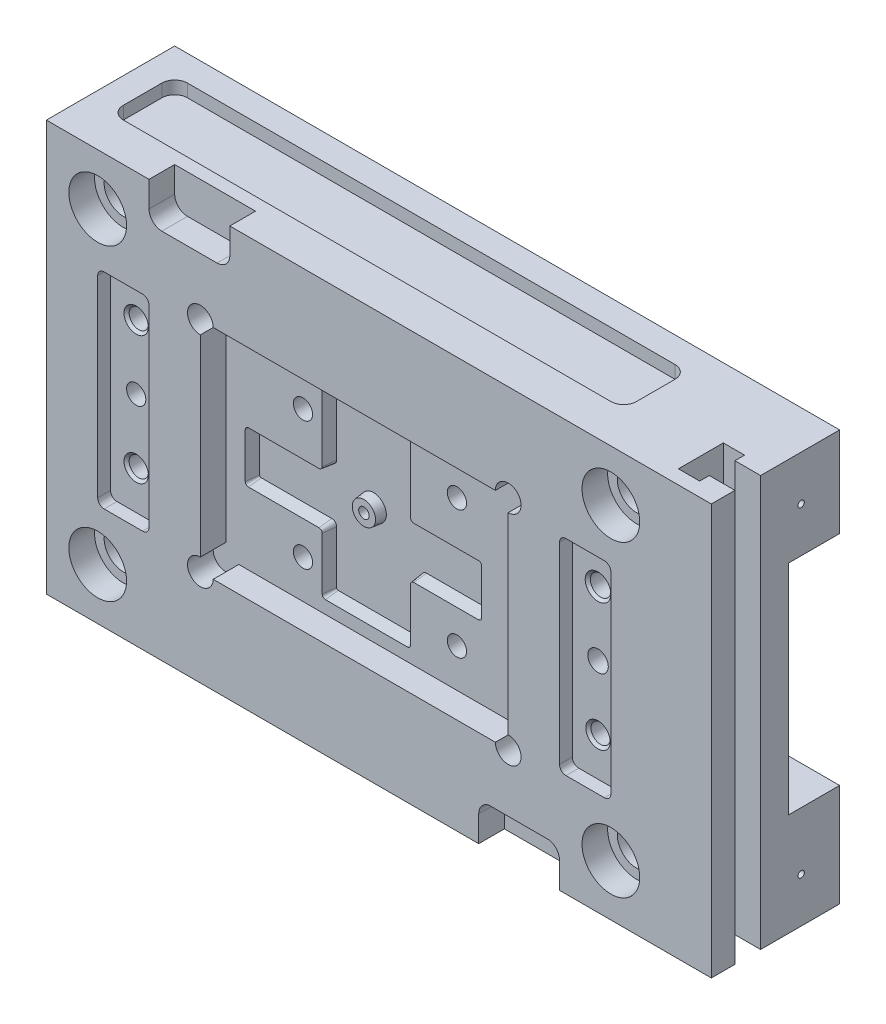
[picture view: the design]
ISO-10303-21;
HEADER;
FILE_DESCRIPTION(('STEP AP214'),'2;1');
FILE_NAME('part.step','',(''),(''),'','','');
FILE_SCHEMA(('AUTOMOTIVE_DESIGN { 1 0 10303 214 1 1 1 1 }'));
ENDSEC;
DATA;
#1=APPLICATION_CONTEXT('core data for automotive mechanical design processes');
#2=APPLICATION_PROTOCOL_DEFINITION('international standard','automotive_design',2000,#1);
#3=PRODUCT_CONTEXT('',#1,'mechanical');
#4=PRODUCT('Part','Part','',(#3));
#5=PRODUCT_RELATED_PRODUCT_CATEGORY('part','',(#4));
#6=PRODUCT_DEFINITION_FORMATION('','',#4);
#7=PRODUCT_DEFINITION_CONTEXT('part definition',#1,'design');
#8=PRODUCT_DEFINITION('design','',#6,#7);
#9=PRODUCT_DEFINITION_SHAPE('','',#8);
#10=(LENGTH_UNIT() NAMED_UNIT(*) SI_UNIT(.MILLI.,.METRE.));
#11=(NAMED_UNIT(*) PLANE_ANGLE_UNIT() SI_UNIT($,.RADIAN.));
#12=(NAMED_UNIT(*) SI_UNIT($,.STERADIAN.) SOLID_ANGLE_UNIT());
#13=UNCERTAINTY_MEASURE_WITH_UNIT(LENGTH_MEASURE(1.E-05),#10,'distance_accuracy_value','');
#14=(GEOMETRIC_REPRESENTATION_CONTEXT(3) GLOBAL_UNCERTAINTY_ASSIGNED_CONTEXT((#13)) GLOBAL_UNIT_ASSIGNED_CONTEXT((#10,
#11,#12)) REPRESENTATION_CONTEXT('',''));
#15=CARTESIAN_POINT('',(0.,0.,0.));
#16=DIRECTION('',(0.,0.,1.));
#17=DIRECTION('',(1.,0.,0.));
#18=AXIS2_PLACEMENT_3D('',#15,#16,#17);
#19=CARTESIAN_POINT('',(658.256146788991,406.4,0.));
#20=DIRECTION('',(1.,0.,0.));
#21=DIRECTION('',(0.,0.,-1.));
#22=AXIS2_PLACEMENT_3D('',#19,#20,#21);
#23=PLANE('',#22);
#24=CARTESIAN_POINT('',(658.256146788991,361.95,-88.9));
#25=DIRECTION('',(1.,0.,0.));
#26=DIRECTION('',(0.,0.,-1.));
#27=AXIS2_PLACEMENT_3D('',#24,#25,#26);
#28=CIRCLE('',#27,3.17500000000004);
#29=CARTESIAN_POINT('',(658.256146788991,361.95,-92.075));
#30=VERTEX_POINT('',#29);
#31=EDGE_CURVE('E745',#30,#30,#28,.T.);
#32=ORIENTED_EDGE('',*,*,#31,.F.);
#33=EDGE_LOOP('',(#32));
#34=FACE_BOUND('',#33,.T.);
#35=CARTESIAN_POINT('',(658.256146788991,44.45,-88.9));
#36=DIRECTION('',(1.,0.,0.));
#37=DIRECTION('',(0.,0.,-1.));
#38=AXIS2_PLACEMENT_3D('',#35,#36,#37);
#39=CIRCLE('',#38,3.17500000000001);
#40=CARTESIAN_POINT('',(658.256146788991,44.45,-92.075));
#41=VERTEX_POINT('',#40);
#42=EDGE_CURVE('E709',#41,#41,#39,.T.);
#43=ORIENTED_EDGE('',*,*,#42,.F.);
#44=EDGE_LOOP('',(#43));
#45=FACE_BOUND('',#44,.T.);
#46=DIRECTION('',(0.,1.,0.));
#47=VECTOR('',#46,1.);
#48=CARTESIAN_POINT('',(658.256146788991,406.4,-48.7717322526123));
#49=LINE('',#48,#47);
#50=CARTESIAN_POINT('',(658.256146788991,0.,-48.7717322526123));
#51=VERTEX_POINT('',#50);
#52=CARTESIAN_POINT('',(658.256146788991,406.4,-48.7717322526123));
#53=VERTEX_POINT('',#52);
#54=EDGE_CURVE('E760',#51,#53,#49,.T.);
#55=ORIENTED_EDGE('',*,*,#54,.F.);
#56=DIRECTION('',(0.,0.,-1.));
#57=VECTOR('',#56,1.);
#58=CARTESIAN_POINT('',(658.256146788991,0.,0.));
#59=LINE('',#58,#57);
#60=CARTESIAN_POINT('',(658.256146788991,0.,-127.));
#61=VERTEX_POINT('',#60);
#62=EDGE_CURVE('E763',#51,#61,#59,.T.);
#63=ORIENTED_EDGE('',*,*,#62,.T.);
#64=DIRECTION('',(0.,-1.,0.));
#65=VECTOR('',#64,1.);
#66=CARTESIAN_POINT('',(658.256146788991,406.4,-127.));
#67=LINE('',#66,#65);
#68=CARTESIAN_POINT('',(658.256146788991,101.6,-127.));
#69=VERTEX_POINT('',#68);
#70=EDGE_CURVE('E808',#69,#61,#67,.T.);
#71=ORIENTED_EDGE('',*,*,#70,.F.);
#72=DIRECTION('',(0.,0.,-1.));
#73=VECTOR('',#72,1.);
#74=CARTESIAN_POINT('',(658.256146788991,101.6,-76.2));
#75=LINE('',#74,#73);
#76=CARTESIAN_POINT('',(658.256146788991,101.6,-76.2));
#77=VERTEX_POINT('',#76);
#78=EDGE_CURVE('E1330',#77,#69,#75,.T.);
#79=ORIENTED_EDGE('',*,*,#78,.F.);
#80=DIRECTION('',(0.,-1.,0.));
#81=VECTOR('',#80,1.);
#82=CARTESIAN_POINT('',(658.256146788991,317.5,-76.2));
#83=LINE('',#82,#81);
#84=CARTESIAN_POINT('',(658.256146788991,317.5,-76.2));
#85=VERTEX_POINT('',#84);
#86=EDGE_CURVE('E1318',#85,#77,#83,.T.);
#87=ORIENTED_EDGE('',*,*,#86,.F.);
#88=DIRECTION('',(0.,0.,1.));
#89=VECTOR('',#88,1.);
#90=CARTESIAN_POINT('',(658.256146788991,317.5,-127.));
#91=LINE('',#90,#89);
#92=CARTESIAN_POINT('',(658.256146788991,317.5,-127.));
#93=VERTEX_POINT('',#92);
#94=EDGE_CURVE('E1328',#93,#85,#91,.T.);
#95=ORIENTED_EDGE('',*,*,#94,.F.);
#96=CARTESIAN_POINT('',(658.256146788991,406.4,-127.));
#97=VERTEX_POINT('',#96);
#98=EDGE_CURVE('E804',#97,#93,#67,.T.);
#99=ORIENTED_EDGE('',*,*,#98,.F.);
#100=DIRECTION('',(0.,0.,-1.));
#101=VECTOR('',#100,1.);
#102=CARTESIAN_POINT('',(658.256146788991,406.4,0.));
#103=LINE('',#102,#101);
#104=EDGE_CURVE('E766',#53,#97,#103,.T.);
#105=ORIENTED_EDGE('',*,*,#104,.F.);
#106=EDGE_LOOP('',(#55,#63,#71,#79,#87,#95,#99,#105));
#107=FACE_BOUND('',#106,.T.);
#108=ADVANCED_FACE('F39',(#34,#45,#107),#23,.T.);
#109=CARTESIAN_POINT('',(250.825,288.925,-38.1000000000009));
#110=DIRECTION('',(0.,0.,1.));
#111=DIRECTION('',(1.,0.,0.));
#112=AXIS2_PLACEMENT_3D('',#109,#110,#111);
#113=PLANE('',#112);
#114=CARTESIAN_POINT('',(250.825,288.925,-38.1000000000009));
#115=DIRECTION('',(0.,0.,1.));
#116=DIRECTION('',(1.,0.,0.));
#117=AXIS2_PLACEMENT_3D('',#114,#115,#116);
#118=CIRCLE('',#117,1.61563607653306);
#119=CARTESIAN_POINT('',(250.825,290.540636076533,-38.1000000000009));
#120=VERTEX_POINT('',#119);
#121=CARTESIAN_POINT('',(249.209363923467,288.925,-38.1000000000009));
#122=VERTEX_POINT('',#121);
#123=EDGE_CURVE('E3355',#120,#122,#118,.T.);
#124=ORIENTED_EDGE('',*,*,#123,.T.);
#125=DIRECTION('',(0.,-1.,0.));
#126=VECTOR('',#125,1.);
#127=CARTESIAN_POINT('',(249.209363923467,288.925,-38.1000000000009));
#128=LINE('',#127,#126);
#129=CARTESIAN_POINT('',(249.209363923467,220.400978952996,-38.1000000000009));
#130=VERTEX_POINT('',#129);
#131=EDGE_CURVE('E3359',#122,#130,#128,.T.);
#132=ORIENTED_EDGE('',*,*,#131,.T.);
#133=CARTESIAN_POINT('',(244.475,220.400978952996,-38.1000000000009));
#134=DIRECTION('',(0.,0.,1.));
#135=DIRECTION('',(1.,0.,0.));
#136=AXIS2_PLACEMENT_3D('',#133,#134,#135);
#137=CIRCLE('',#136,4.73436392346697);
#138=CARTESIAN_POINT('',(244.475,215.666615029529,-38.1000000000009));
#139=VERTEX_POINT('',#138);
#140=EDGE_CURVE('E3456',#130,#139,#137,.F.);
#141=ORIENTED_EDGE('',*,*,#140,.T.);
#142=DIRECTION('',(-1.,0.,0.));
#143=VECTOR('',#142,1.);
#144=CARTESIAN_POINT('',(250.825,215.666615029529,-38.1000000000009));
#145=LINE('',#144,#143);
#146=CARTESIAN_POINT('',(174.625,215.666615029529,-38.1000000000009));
#147=VERTEX_POINT('',#146);
#148=EDGE_CURVE('E3452',#139,#147,#145,.T.);
#149=ORIENTED_EDGE('',*,*,#148,.T.);
#150=CARTESIAN_POINT('',(174.625,214.050978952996,-38.1000000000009));
#151=DIRECTION('',(0.,0.,1.));
#152=DIRECTION('',(1.,0.,0.));
#153=AXIS2_PLACEMENT_3D('',#150,#151,#152);
#154=CIRCLE('',#153,1.61563607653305);
#155=CARTESIAN_POINT('',(173.009363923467,214.050978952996,-38.1000000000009));
#156=VERTEX_POINT('',#155);
#157=EDGE_CURVE('E3448',#147,#156,#154,.T.);
#158=ORIENTED_EDGE('',*,*,#157,.T.);
#159=DIRECTION('',(0.,-1.,0.));
#160=VECTOR('',#159,1.);
#161=CARTESIAN_POINT('',(173.009363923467,288.925,-38.1000000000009));
#162=LINE('',#161,#160);
#163=CARTESIAN_POINT('',(173.009363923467,169.600978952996,-38.1000000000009));
#164=VERTEX_POINT('',#163);
#165=EDGE_CURVE('E3445',#156,#164,#162,.T.);
#166=ORIENTED_EDGE('',*,*,#165,.T.);
#167=CARTESIAN_POINT('',(174.625,169.600978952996,-38.1000000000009));
#168=DIRECTION('',(0.,0.,1.));
#169=DIRECTION('',(1.,0.,0.));
#170=AXIS2_PLACEMENT_3D('',#167,#168,#169);
#171=CIRCLE('',#170,1.61563607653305);
#172=CARTESIAN_POINT('',(174.625,167.985342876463,-38.1000000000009));
#173=VERTEX_POINT('',#172);
#174=EDGE_CURVE('E3438',#164,#173,#171,.T.);
#175=ORIENTED_EDGE('',*,*,#174,.T.);
#176=DIRECTION('',(1.,0.,0.));
#177=VECTOR('',#176,1.);
#178=CARTESIAN_POINT('',(250.825,167.985342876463,-38.1000000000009));
#179=LINE('',#178,#177);
#180=CARTESIAN_POINT('',(244.475,167.985342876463,-38.1000000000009));
#181=VERTEX_POINT('',#180);
#182=EDGE_CURVE('E3434',#173,#181,#179,.T.);
#183=ORIENTED_EDGE('',*,*,#182,.T.);
#184=CARTESIAN_POINT('',(244.475,163.250978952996,-38.1000000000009));
#185=DIRECTION('',(0.,0.,1.));
#186=DIRECTION('',(1.,0.,0.));
#187=AXIS2_PLACEMENT_3D('',#184,#185,#186);
#188=CIRCLE('',#187,4.73436392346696);
#189=CARTESIAN_POINT('',(249.209363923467,163.250978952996,-38.1000000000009));
#190=VERTEX_POINT('',#189);
#191=EDGE_CURVE('E3431',#181,#190,#188,.F.);
#192=ORIENTED_EDGE('',*,*,#191,.T.);
#193=DIRECTION('',(0.,-1.,0.));
#194=VECTOR('',#193,1.);
#195=CARTESIAN_POINT('',(249.209363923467,288.925,-38.1000000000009));
#196=LINE('',#195,#194);
#197=CARTESIAN_POINT('',(249.209363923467,111.125,-38.1000000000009));
#198=VERTEX_POINT('',#197);
#199=EDGE_CURVE('E3427',#190,#198,#196,.T.);
#200=ORIENTED_EDGE('',*,*,#199,.T.);
#201=CARTESIAN_POINT('',(250.825,111.125,-38.1000000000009));
#202=DIRECTION('',(0.,0.,1.));
#203=DIRECTION('',(1.,0.,0.));
#204=AXIS2_PLACEMENT_3D('',#201,#202,#203);
#205=CIRCLE('',#204,1.61563607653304);
#206=CARTESIAN_POINT('',(250.825,109.509363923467,-38.1000000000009));
#207=VERTEX_POINT('',#206);
#208=EDGE_CURVE('E3424',#198,#207,#205,.T.);
#209=ORIENTED_EDGE('',*,*,#208,.T.);
#210=DIRECTION('',(1.,0.,0.));
#211=VECTOR('',#210,1.);
#212=CARTESIAN_POINT('',(250.825,109.509363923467,-38.1000000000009));
#213=LINE('',#212,#211);
#214=CARTESIAN_POINT('',(331.909563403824,109.509363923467,-38.1000000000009));
#215=VERTEX_POINT('',#214);
#216=EDGE_CURVE('E3416',#207,#215,#213,.T.);
#217=ORIENTED_EDGE('',*,*,#216,.T.);
#218=CARTESIAN_POINT('',(331.909563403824,111.125,-38.1000000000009));
#219=DIRECTION('',(0.,0.,1.));
#220=DIRECTION('',(1.,0.,0.));
#221=AXIS2_PLACEMENT_3D('',#218,#219,#220);
#222=CIRCLE('',#221,1.61563607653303);
#223=CARTESIAN_POINT('',(333.525199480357,111.125,-38.1000000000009));
#224=VERTEX_POINT('',#223);
#225=EDGE_CURVE('E3412',#215,#224,#222,.T.);
#226=ORIENTED_EDGE('',*,*,#225,.T.);
#227=DIRECTION('',(0.,1.,0.));
#228=VECTOR('',#227,1.);
#229=CARTESIAN_POINT('',(333.525199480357,288.925,-38.1000000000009));
#230=LINE('',#229,#228);
#231=CARTESIAN_POINT('',(333.525199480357,163.250978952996,-38.1000000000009));
#232=VERTEX_POINT('',#231);
#233=EDGE_CURVE('E3408',#224,#232,#230,.T.);
#234=ORIENTED_EDGE('',*,*,#233,.T.);
#235=CARTESIAN_POINT('',(338.259563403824,163.250978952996,-38.1000000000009));
#236=DIRECTION('',(0.,0.,1.));
#237=DIRECTION('',(1.,0.,0.));
#238=AXIS2_PLACEMENT_3D('',#235,#236,#237);
#239=CIRCLE('',#238,4.73436392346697);
#240=CARTESIAN_POINT('',(338.259563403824,167.985342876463,-38.1000000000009));
#241=VERTEX_POINT('',#240);
#242=EDGE_CURVE('E3406',#232,#241,#239,.F.);
#243=ORIENTED_EDGE('',*,*,#242,.T.);
#244=DIRECTION('',(1.,0.,0.));
#245=VECTOR('',#244,1.);
#246=CARTESIAN_POINT('',(250.824999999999,167.985342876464,-38.1000000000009));
#247=LINE('',#246,#245);
#248=CARTESIAN_POINT('',(402.352375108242,167.985342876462,-38.1000000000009));
#249=VERTEX_POINT('',#248);
#250=EDGE_CURVE('E3402',#241,#249,#247,.T.);
#251=ORIENTED_EDGE('',*,*,#250,.T.);
#252=CARTESIAN_POINT('',(402.352375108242,169.600978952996,-38.1000000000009));
#253=DIRECTION('',(0.,0.,1.));
#254=DIRECTION('',(1.,0.,0.));
#255=AXIS2_PLACEMENT_3D('',#252,#253,#254);
#256=CIRCLE('',#255,1.61563607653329);
#257=CARTESIAN_POINT('',(403.968011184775,169.600978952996,-38.1000000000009));
#258=VERTEX_POINT('',#257);
#259=EDGE_CURVE('E3394',#249,#258,#256,.T.);
#260=ORIENTED_EDGE('',*,*,#259,.T.);
#261=DIRECTION('',(0.,1.,0.));
#262=VECTOR('',#261,1.);
#263=CARTESIAN_POINT('',(403.968011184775,288.925,-38.1000000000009));
#264=LINE('',#263,#262);
#265=CARTESIAN_POINT('',(403.968011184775,214.050978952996,-38.1000000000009));
#266=VERTEX_POINT('',#265);
#267=EDGE_CURVE('E3390',#258,#266,#264,.T.);
#268=ORIENTED_EDGE('',*,*,#267,.T.);
#269=CARTESIAN_POINT('',(402.352375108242,214.050978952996,-38.1000000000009));
#270=DIRECTION('',(0.,0.,1.));
#271=DIRECTION('',(1.,0.,0.));
#272=AXIS2_PLACEMENT_3D('',#269,#270,#271);
#273=CIRCLE('',#272,1.61563607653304);
#274=CARTESIAN_POINT('',(402.352375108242,215.666615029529,-38.1000000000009));
#275=VERTEX_POINT('',#274);
#276=EDGE_CURVE('E3386',#266,#275,#273,.T.);
#277=ORIENTED_EDGE('',*,*,#276,.T.);
#278=DIRECTION('',(-1.,0.,0.));
#279=VECTOR('',#278,1.);
#280=CARTESIAN_POINT('',(250.825,215.666615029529,-38.1000000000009));
#281=LINE('',#280,#279);
#282=CARTESIAN_POINT('',(338.259563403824,215.666615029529,-38.1000000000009));
#283=VERTEX_POINT('',#282);
#284=EDGE_CURVE('E3382',#275,#283,#281,.T.);
#285=ORIENTED_EDGE('',*,*,#284,.T.);
#286=CARTESIAN_POINT('',(338.259563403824,220.400978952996,-38.1000000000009));
#287=DIRECTION('',(0.,0.,1.));
#288=DIRECTION('',(1.,0.,0.));
#289=AXIS2_PLACEMENT_3D('',#286,#287,#288);
#290=CIRCLE('',#289,4.73436392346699);
#291=CARTESIAN_POINT('',(333.525199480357,220.400978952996,-38.1000000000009));
#292=VERTEX_POINT('',#291);
#293=EDGE_CURVE('E3385',#283,#292,#290,.F.);
#294=ORIENTED_EDGE('',*,*,#293,.T.);
#295=DIRECTION('',(0.,1.,0.));
#296=VECTOR('',#295,1.);
#297=CARTESIAN_POINT('',(333.525199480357,288.925,-38.1000000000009));
#298=LINE('',#297,#296);
#299=CARTESIAN_POINT('',(333.525199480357,288.925,-38.1000000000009));
#300=VERTEX_POINT('',#299);
#301=EDGE_CURVE('E3373',#292,#300,#298,.T.);
#302=ORIENTED_EDGE('',*,*,#301,.T.);
#303=CARTESIAN_POINT('',(331.909563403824,288.925,-38.1000000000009));
#304=DIRECTION('',(0.,0.,1.));
#305=DIRECTION('',(1.,0.,0.));
#306=AXIS2_PLACEMENT_3D('',#303,#304,#305);
#307=CIRCLE('',#306,1.61563607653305);
#308=CARTESIAN_POINT('',(331.909563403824,290.540636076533,-38.1000000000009));
#309=VERTEX_POINT('',#308);
#310=EDGE_CURVE('E3369',#300,#309,#307,.T.);
#311=ORIENTED_EDGE('',*,*,#310,.T.);
#312=DIRECTION('',(-1.,0.,0.));
#313=VECTOR('',#312,1.);
#314=CARTESIAN_POINT('',(250.825,290.540636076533,-38.1000000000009));
#315=LINE('',#314,#313);
#316=EDGE_CURVE('E3364',#309,#120,#315,.T.);
#317=ORIENTED_EDGE('',*,*,#316,.T.);
#318=EDGE_LOOP('',(#124,#132,#141,#149,#158,#166,#175,#183,#192,#200,#209,#217,#226,#234,#243,
#251,#260,#268,#277,#285,#294,#302,#311,#317));
#319=FACE_BOUND('',#318,.T.);
#320=CARTESIAN_POINT('',(285.75,198.175978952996,-38.1000000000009));
#321=DIRECTION('',(0.,0.,1.));
#322=DIRECTION('',(1.,0.,0.));
#323=AXIS2_PLACEMENT_3D('',#320,#321,#322);
#324=CIRCLE('',#323,12.7);
#325=CARTESIAN_POINT('',(298.45,198.175978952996,-38.1000000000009));
#326=VERTEX_POINT('',#325);
#327=EDGE_CURVE('E3875',#326,#326,#324,.T.);
#328=ORIENTED_EDGE('',*,*,#327,.F.);
#329=EDGE_LOOP('',(#328));
#330=FACE_BOUND('',#329,.T.);
#331=ADVANCED_FACE('F756',(#319,#330),#113,.T.);
#332=CARTESIAN_POINT('',(152.4,95.25,-25.4));
#333=DIRECTION('',(0.,0.,1.));
#334=DIRECTION('',(1.,0.,0.));
#335=AXIS2_PLACEMENT_3D('',#332,#333,#334);
#336=PLANE('',#335);
#337=CARTESIAN_POINT('',(250.825,288.925,-25.4));
#338=DIRECTION('',(0.,0.,1.));
#339=DIRECTION('',(1.,0.,0.));
#340=AXIS2_PLACEMENT_3D('',#337,#338,#339);
#341=CIRCLE('',#340,3.17500000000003);
#342=CARTESIAN_POINT('',(250.825,292.1,-25.4));
#343=VERTEX_POINT('',#342);
#344=CARTESIAN_POINT('',(247.65,288.925,-25.4));
#345=VERTEX_POINT('',#344);
#346=EDGE_CURVE('E3888',#343,#345,#341,.T.);
#347=ORIENTED_EDGE('',*,*,#346,.F.);
#348=DIRECTION('',(-1.,0.,0.));
#349=VECTOR('',#348,1.);
#350=CARTESIAN_POINT('',(331.909563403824,292.1,-25.4));
#351=LINE('',#350,#349);
#352=CARTESIAN_POINT('',(331.909563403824,292.1,-25.4));
#353=VERTEX_POINT('',#352);
#354=EDGE_CURVE('E3360',#353,#343,#351,.T.);
#355=ORIENTED_EDGE('',*,*,#354,.F.);
#356=CARTESIAN_POINT('',(331.909563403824,288.925,-25.4));
#357=DIRECTION('',(0.,0.,1.));
#358=DIRECTION('',(1.,0.,0.));
#359=AXIS2_PLACEMENT_3D('',#356,#357,#358);
#360=CIRCLE('',#359,3.17500000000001);
#361=CARTESIAN_POINT('',(335.084563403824,288.925,-25.4));
#362=VERTEX_POINT('',#361);
#363=EDGE_CURVE('E3583',#362,#353,#360,.T.);
#364=ORIENTED_EDGE('',*,*,#363,.F.);
#365=DIRECTION('',(0.,1.,0.));
#366=VECTOR('',#365,1.);
#367=CARTESIAN_POINT('',(335.084563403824,220.400978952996,-25.4));
#368=LINE('',#367,#366);
#369=CARTESIAN_POINT('',(335.084563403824,220.400978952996,-25.4));
#370=VERTEX_POINT('',#369);
#371=EDGE_CURVE('E3580',#370,#362,#368,.T.);
#372=ORIENTED_EDGE('',*,*,#371,.F.);
#373=CARTESIAN_POINT('',(338.259563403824,220.400978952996,-25.4));
#374=DIRECTION('',(0.,0.,-1.));
#375=DIRECTION('',(-1.,0.,0.));
#376=AXIS2_PLACEMENT_3D('',#373,#374,#375);
#377=CIRCLE('',#376,3.17500000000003);
#378=CARTESIAN_POINT('',(338.259563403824,217.225978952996,-25.4));
#379=VERTEX_POINT('',#378);
#380=EDGE_CURVE('E3948',#379,#370,#377,.T.);
#381=ORIENTED_EDGE('',*,*,#380,.F.);
#382=DIRECTION('',(-1.,0.,0.));
#383=VECTOR('',#382,1.);
#384=CARTESIAN_POINT('',(402.352375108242,217.225978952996,-25.4));
#385=LINE('',#384,#383);
#386=CARTESIAN_POINT('',(402.352375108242,217.225978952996,-25.4));
#387=VERTEX_POINT('',#386);
#388=EDGE_CURVE('E3569',#387,#379,#385,.T.);
#389=ORIENTED_EDGE('',*,*,#388,.F.);
#390=CARTESIAN_POINT('',(402.352375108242,214.050978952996,-25.4));
#391=DIRECTION('',(0.,0.,1.));
#392=DIRECTION('',(1.,0.,0.));
#393=AXIS2_PLACEMENT_3D('',#390,#391,#392);
#394=CIRCLE('',#393,3.175);
#395=CARTESIAN_POINT('',(405.527375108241,214.050978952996,-25.4));
#396=VERTEX_POINT('',#395);
#397=EDGE_CURVE('E3943',#396,#387,#394,.T.);
#398=ORIENTED_EDGE('',*,*,#397,.F.);
#399=DIRECTION('',(0.,1.,0.));
#400=VECTOR('',#399,1.);
#401=CARTESIAN_POINT('',(405.527375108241,169.600978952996,-25.4));
#402=LINE('',#401,#400);
#403=CARTESIAN_POINT('',(405.527375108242,169.600978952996,-25.4));
#404=VERTEX_POINT('',#403);
#405=EDGE_CURVE('E3557',#404,#396,#402,.T.);
#406=ORIENTED_EDGE('',*,*,#405,.F.);
#407=CARTESIAN_POINT('',(402.352375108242,169.600978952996,-25.4));
#408=DIRECTION('',(0.,0.,1.));
#409=DIRECTION('',(1.,0.,0.));
#410=AXIS2_PLACEMENT_3D('',#407,#408,#409);
#411=CIRCLE('',#410,3.17500000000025);
#412=CARTESIAN_POINT('',(402.352375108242,166.425978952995,-25.4));
#413=VERTEX_POINT('',#412);
#414=EDGE_CURVE('E3551',#413,#404,#411,.T.);
#415=ORIENTED_EDGE('',*,*,#414,.F.);
#416=DIRECTION('',(1.,0.,0.));
#417=VECTOR('',#416,1.);
#418=CARTESIAN_POINT('',(338.259563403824,166.425978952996,-25.4));
#419=LINE('',#418,#417);
#420=CARTESIAN_POINT('',(338.259563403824,166.425978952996,-25.4));
#421=VERTEX_POINT('',#420);
#422=EDGE_CURVE('E3932',#421,#413,#419,.T.);
#423=ORIENTED_EDGE('',*,*,#422,.F.);
#424=CARTESIAN_POINT('',(338.259563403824,163.250978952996,-25.4));
#425=DIRECTION('',(0.,0.,-1.));
#426=DIRECTION('',(-1.,0.,0.));
#427=AXIS2_PLACEMENT_3D('',#424,#425,#426);
#428=CIRCLE('',#427,3.17500000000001);
#429=CARTESIAN_POINT('',(335.084563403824,163.250978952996,-25.4));
#430=VERTEX_POINT('',#429);
#431=EDGE_CURVE('E3540',#430,#421,#428,.T.);
#432=ORIENTED_EDGE('',*,*,#431,.F.);
#433=DIRECTION('',(0.,1.,0.));
#434=VECTOR('',#433,1.);
#435=CARTESIAN_POINT('',(335.084563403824,111.125,-25.4));
#436=LINE('',#435,#434);
#437=CARTESIAN_POINT('',(335.084563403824,111.125,-25.4));
#438=VERTEX_POINT('',#437);
#439=EDGE_CURVE('E3534',#438,#430,#436,.T.);
#440=ORIENTED_EDGE('',*,*,#439,.F.);
#441=CARTESIAN_POINT('',(331.909563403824,111.125,-25.4));
#442=DIRECTION('',(0.,0.,1.));
#443=DIRECTION('',(1.,0.,0.));
#444=AXIS2_PLACEMENT_3D('',#441,#442,#443);
#445=CIRCLE('',#444,3.17499999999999);
#446=CARTESIAN_POINT('',(331.909563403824,107.95,-25.4));
#447=VERTEX_POINT('',#446);
#448=EDGE_CURVE('E3921',#447,#438,#445,.T.);
#449=ORIENTED_EDGE('',*,*,#448,.F.);
#450=DIRECTION('',(1.,0.,0.));
#451=VECTOR('',#450,1.);
#452=CARTESIAN_POINT('',(250.825,107.95,-25.4));
#453=LINE('',#452,#451);
#454=CARTESIAN_POINT('',(250.825,107.95,-25.4));
#455=VERTEX_POINT('',#454);
#456=EDGE_CURVE('E3524',#455,#447,#453,.T.);
#457=ORIENTED_EDGE('',*,*,#456,.F.);
#458=CARTESIAN_POINT('',(250.825,111.125,-25.4));
#459=DIRECTION('',(0.,0.,1.));
#460=DIRECTION('',(1.,0.,0.));
#461=AXIS2_PLACEMENT_3D('',#458,#459,#460);
#462=CIRCLE('',#461,3.175);
#463=CARTESIAN_POINT('',(247.65,111.125,-25.4));
#464=VERTEX_POINT('',#463);
#465=EDGE_CURVE('E3518',#464,#455,#462,.T.);
#466=ORIENTED_EDGE('',*,*,#465,.F.);
#467=DIRECTION('',(0.,-1.,0.));
#468=VECTOR('',#467,1.);
#469=CARTESIAN_POINT('',(247.65,163.250978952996,-25.4));
#470=LINE('',#469,#468);
#471=CARTESIAN_POINT('',(247.65,163.250978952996,-25.4));
#472=VERTEX_POINT('',#471);
#473=EDGE_CURVE('E3915',#472,#464,#470,.T.);
#474=ORIENTED_EDGE('',*,*,#473,.F.);
#475=CARTESIAN_POINT('',(244.475,163.250978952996,-25.4));
#476=DIRECTION('',(0.,0.,-1.));
#477=DIRECTION('',(-1.,0.,0.));
#478=AXIS2_PLACEMENT_3D('',#475,#476,#477);
#479=CIRCLE('',#478,3.175);
#480=CARTESIAN_POINT('',(244.475,166.425978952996,-25.4));
#481=VERTEX_POINT('',#480);
#482=EDGE_CURVE('E3507',#481,#472,#479,.T.);
#483=ORIENTED_EDGE('',*,*,#482,.F.);
#484=DIRECTION('',(1.,0.,0.));
#485=VECTOR('',#484,1.);
#486=CARTESIAN_POINT('',(174.625,166.425978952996,-25.4));
#487=LINE('',#486,#485);
#488=CARTESIAN_POINT('',(174.625,166.425978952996,-25.4));
#489=VERTEX_POINT('',#488);
#490=EDGE_CURVE('E3501',#489,#481,#487,.T.);
#491=ORIENTED_EDGE('',*,*,#490,.F.);
#492=CARTESIAN_POINT('',(174.625,169.600978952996,-25.4));
#493=DIRECTION('',(0.,0.,1.));
#494=DIRECTION('',(1.,0.,0.));
#495=AXIS2_PLACEMENT_3D('',#492,#493,#494);
#496=CIRCLE('',#495,3.17500000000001);
#497=CARTESIAN_POINT('',(171.45,169.600978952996,-25.4));
#498=VERTEX_POINT('',#497);
#499=EDGE_CURVE('E3903',#498,#489,#496,.T.);
#500=ORIENTED_EDGE('',*,*,#499,.F.);
#501=DIRECTION('',(0.,-1.,0.));
#502=VECTOR('',#501,1.);
#503=CARTESIAN_POINT('',(171.45,214.050978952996,-25.4));
#504=LINE('',#503,#502);
#505=CARTESIAN_POINT('',(171.45,214.050978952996,-25.4));
#506=VERTEX_POINT('',#505);
#507=EDGE_CURVE('E3491',#506,#498,#504,.T.);
#508=ORIENTED_EDGE('',*,*,#507,.F.);
#509=CARTESIAN_POINT('',(174.625,214.050978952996,-25.4));
#510=DIRECTION('',(0.,0.,1.));
#511=DIRECTION('',(1.,0.,0.));
#512=AXIS2_PLACEMENT_3D('',#509,#510,#511);
#513=CIRCLE('',#512,3.17500000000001);
#514=CARTESIAN_POINT('',(174.625,217.225978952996,-25.4));
#515=VERTEX_POINT('',#514);
#516=EDGE_CURVE('E3485',#515,#506,#513,.T.);
#517=ORIENTED_EDGE('',*,*,#516,.F.);
#518=DIRECTION('',(-1.,0.,0.));
#519=VECTOR('',#518,1.);
#520=CARTESIAN_POINT('',(244.475,217.225978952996,-25.4));
#521=LINE('',#520,#519);
#522=CARTESIAN_POINT('',(244.475,217.225978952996,-25.4));
#523=VERTEX_POINT('',#522);
#524=EDGE_CURVE('E3892',#523,#515,#521,.T.);
#525=ORIENTED_EDGE('',*,*,#524,.F.);
#526=CARTESIAN_POINT('',(244.475,220.400978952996,-25.4));
#527=DIRECTION('',(0.,0.,-1.));
#528=DIRECTION('',(-1.,0.,0.));
#529=AXIS2_PLACEMENT_3D('',#526,#527,#528);
#530=CIRCLE('',#529,3.17500000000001);
#531=CARTESIAN_POINT('',(247.65,220.400978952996,-25.4));
#532=VERTEX_POINT('',#531);
#533=EDGE_CURVE('E3474',#532,#523,#530,.T.);
#534=ORIENTED_EDGE('',*,*,#533,.F.);
#535=DIRECTION('',(0.,-1.,0.));
#536=VECTOR('',#535,1.);
#537=CARTESIAN_POINT('',(247.65,288.925,-25.4));
#538=LINE('',#537,#536);
#539=EDGE_CURVE('E3468',#345,#532,#538,.T.);
#540=ORIENTED_EDGE('',*,*,#539,.F.);
#541=EDGE_LOOP('',(#347,#355,#364,#372,#381,#389,#398,#406,#415,#423,#432,#440,#449,#457,#466,
#474,#483,#491,#500,#508,#517,#525,#534,#540));
#542=FACE_BOUND('',#541,.T.);
#543=CARTESIAN_POINT('',(228.6,133.35,-25.4));
#544=DIRECTION('',(0.,0.,-1.));
#545=DIRECTION('',(-1.,0.,0.));
#546=AXIS2_PLACEMENT_3D('',#543,#544,#545);
#547=CIRCLE('',#546,9.52500000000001);
#548=CARTESIAN_POINT('',(219.075,133.35,-25.4));
#549=VERTEX_POINT('',#548);
#550=EDGE_CURVE('E3197',#549,#549,#547,.T.);
#551=ORIENTED_EDGE('',*,*,#550,.T.);
#552=EDGE_LOOP('',(#551));
#553=FACE_BOUND('',#552,.T.);
#554=CARTESIAN_POINT('',(381.,260.35,-25.4));
#555=DIRECTION('',(0.,0.,-1.));
#556=DIRECTION('',(-1.,0.,0.));
#557=AXIS2_PLACEMENT_3D('',#554,#555,#556);
#558=CIRCLE('',#557,9.52500000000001);
#559=CARTESIAN_POINT('',(371.475,260.35,-25.4));
#560=VERTEX_POINT('',#559);
#561=EDGE_CURVE('E3969',#560,#560,#558,.T.);
#562=ORIENTED_EDGE('',*,*,#561,.T.);
#563=EDGE_LOOP('',(#562));
#564=FACE_BOUND('',#563,.T.);
#565=CARTESIAN_POINT('',(152.4,95.25,-25.4));
#566=DIRECTION('',(0.,0.,1.));
#567=DIRECTION('',(1.,0.,0.));
#568=AXIS2_PLACEMENT_3D('',#565,#566,#567);
#569=CIRCLE('',#568,12.7);
#570=CARTESIAN_POINT('',(152.4,107.95,-25.4));
#571=VERTEX_POINT('',#570);
#572=CARTESIAN_POINT('',(165.1,95.25,-25.4));
#573=VERTEX_POINT('',#572);
#574=EDGE_CURVE('E3280',#571,#573,#569,.T.);
#575=ORIENTED_EDGE('',*,*,#574,.T.);
#576=DIRECTION('',(1.,0.,0.));
#577=VECTOR('',#576,1.);
#578=CARTESIAN_POINT('',(165.1,95.25,-25.4));
#579=LINE('',#578,#577);
#580=CARTESIAN_POINT('',(444.5,95.25,-25.4));
#581=VERTEX_POINT('',#580);
#582=EDGE_CURVE('E3287',#573,#581,#579,.T.);
#583=ORIENTED_EDGE('',*,*,#582,.T.);
#584=CARTESIAN_POINT('',(457.2,95.25,-25.4));
#585=DIRECTION('',(0.,0.,1.));
#586=DIRECTION('',(1.,0.,0.));
#587=AXIS2_PLACEMENT_3D('',#584,#585,#586);
#588=CIRCLE('',#587,12.7);
#589=CARTESIAN_POINT('',(457.2,107.95,-25.4));
#590=VERTEX_POINT('',#589);
#591=EDGE_CURVE('E3299',#581,#590,#588,.T.);
#592=ORIENTED_EDGE('',*,*,#591,.T.);
#593=DIRECTION('',(0.,1.,0.));
#594=VECTOR('',#593,1.);
#595=CARTESIAN_POINT('',(457.2,107.95,-25.4));
#596=LINE('',#595,#594);
#597=CARTESIAN_POINT('',(457.2,298.45,-25.4));
#598=VERTEX_POINT('',#597);
#599=EDGE_CURVE('E3302',#590,#598,#596,.T.);
#600=ORIENTED_EDGE('',*,*,#599,.T.);
#601=CARTESIAN_POINT('',(457.2,311.15,-25.4));
#602=DIRECTION('',(0.,0.,1.));
#603=DIRECTION('',(1.,0.,0.));
#604=AXIS2_PLACEMENT_3D('',#601,#602,#603);
#605=CIRCLE('',#604,12.7);
#606=CARTESIAN_POINT('',(444.5,311.15,-25.4));
#607=VERTEX_POINT('',#606);
#608=EDGE_CURVE('E3306',#598,#607,#605,.T.);
#609=ORIENTED_EDGE('',*,*,#608,.T.);
#610=DIRECTION('',(-1.,0.,0.));
#611=VECTOR('',#610,1.);
#612=CARTESIAN_POINT('',(444.5,311.15,-25.4));
#613=LINE('',#612,#611);
#614=CARTESIAN_POINT('',(165.1,311.15,-25.4));
#615=VERTEX_POINT('',#614);
#616=EDGE_CURVE('E3309',#607,#615,#613,.T.);
#617=ORIENTED_EDGE('',*,*,#616,.T.);
#618=CARTESIAN_POINT('',(152.4,311.15,-25.4));
#619=DIRECTION('',(0.,0.,1.));
#620=DIRECTION('',(1.,0.,0.));
#621=AXIS2_PLACEMENT_3D('',#618,#619,#620);
#622=CIRCLE('',#621,12.7);
#623=CARTESIAN_POINT('',(152.4,298.45,-25.4));
#624=VERTEX_POINT('',#623);
#625=EDGE_CURVE('E1191',#615,#624,#622,.T.);
#626=ORIENTED_EDGE('',*,*,#625,.T.);
#627=DIRECTION('',(0.,-1.,0.));
#628=VECTOR('',#627,1.);
#629=CARTESIAN_POINT('',(152.4,298.45,-25.4));
#630=LINE('',#629,#628);
#631=EDGE_CURVE('E1186',#624,#571,#630,.T.);
#632=ORIENTED_EDGE('',*,*,#631,.T.);
#633=EDGE_LOOP('',(#575,#583,#592,#600,#609,#617,#626,#632));
#634=FACE_BOUND('',#633,.T.);
#635=CARTESIAN_POINT('',(381.,133.35,-25.4));
#636=DIRECTION('',(0.,0.,-1.));
#637=DIRECTION('',(-1.,0.,0.));
#638=AXIS2_PLACEMENT_3D('',#635,#636,#637);
#639=CIRCLE('',#638,9.52500000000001);
#640=CARTESIAN_POINT('',(371.475,133.35,-25.4));
#641=VERTEX_POINT('',#640);
#642=EDGE_CURVE('E3239',#641,#641,#639,.T.);
#643=ORIENTED_EDGE('',*,*,#642,.T.);
#644=EDGE_LOOP('',(#643));
#645=FACE_BOUND('',#644,.T.);
#646=CARTESIAN_POINT('',(228.6,260.35,-25.4));
#647=DIRECTION('',(0.,0.,-1.));
#648=DIRECTION('',(-1.,0.,0.));
#649=AXIS2_PLACEMENT_3D('',#646,#647,#648);
#650=CIRCLE('',#649,9.52500000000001);
#651=CARTESIAN_POINT('',(219.075,260.35,-25.4));
#652=VERTEX_POINT('',#651);
#653=EDGE_CURVE('E3231',#652,#652,#650,.T.);
#654=ORIENTED_EDGE('',*,*,#653,.T.);
#655=EDGE_LOOP('',(#654));
#656=FACE_BOUND('',#655,.T.);
#657=ADVANCED_FACE('F1801',(#542,#553,#564,#634,#645,#656),#336,.T.);
#658=CARTESIAN_POINT('',(658.256146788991,0.,-127.));
#659=DIRECTION('',(0.,0.,-1.));
#660=DIRECTION('',(-1.,0.,0.));
#661=AXIS2_PLACEMENT_3D('',#658,#659,#660);
#662=PLANE('',#661);
#663=CARTESIAN_POINT('',(558.8,50.8,-127.));
#664=DIRECTION('',(0.,0.,1.));
#665=DIRECTION('',(1.,0.,0.));
#666=AXIS2_PLACEMENT_3D('',#663,#664,#665);
#667=CIRCLE('',#666,19.05);
#668=CARTESIAN_POINT('',(577.85,50.8,-127.));
#669=VERTEX_POINT('',#668);
#670=EDGE_CURVE('E3169',#669,#669,#667,.T.);
#671=ORIENTED_EDGE('',*,*,#670,.T.);
#672=EDGE_LOOP('',(#671));
#673=FACE_BOUND('',#672,.T.);
#674=CARTESIAN_POINT('',(50.8,50.8,-127.));
#675=DIRECTION('',(0.,0.,1.));
#676=DIRECTION('',(1.,0.,0.));
#677=AXIS2_PLACEMENT_3D('',#674,#675,#676);
#678=CIRCLE('',#677,19.05);
#679=CARTESIAN_POINT('',(69.85,50.8,-127.));
#680=VERTEX_POINT('',#679);
#681=EDGE_CURVE('E4059',#680,#680,#678,.T.);
#682=ORIENTED_EDGE('',*,*,#681,.T.);
#683=EDGE_LOOP('',(#682));
#684=FACE_BOUND('',#683,.T.);
#685=DIRECTION('',(1.,0.,0.));
#686=VECTOR('',#685,1.);
#687=CARTESIAN_POINT('',(-0.00100000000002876,101.6,-127.));
#688=LINE('',#687,#686);
#689=CARTESIAN_POINT('',(0.,101.6,-127.));
#690=VERTEX_POINT('',#689);
#691=EDGE_CURVE('E809',#690,#69,#688,.T.);
#692=ORIENTED_EDGE('',*,*,#691,.T.);
#693=ORIENTED_EDGE('',*,*,#70,.T.);
#694=DIRECTION('',(-1.,0.,0.));
#695=VECTOR('',#694,1.);
#696=CARTESIAN_POINT('',(658.256146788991,0.,-127.));
#697=LINE('',#696,#695);
#698=CARTESIAN_POINT('',(0.,0.,-127.));
#699=VERTEX_POINT('',#698);
#700=EDGE_CURVE('E776',#61,#699,#697,.T.);
#701=ORIENTED_EDGE('',*,*,#700,.T.);
#702=DIRECTION('',(0.,1.,0.));
#703=VECTOR('',#702,1.);
#704=CARTESIAN_POINT('',(0.,0.,-127.));
#705=LINE('',#704,#703);
#706=EDGE_CURVE('E815',#699,#690,#705,.T.);
#707=ORIENTED_EDGE('',*,*,#706,.T.);
#708=EDGE_LOOP('',(#692,#693,#701,#707));
#709=FACE_BOUND('',#708,.T.);
#710=ADVANCED_FACE('F1949',(#673,#684,#709),#662,.T.);
#711=DIRECTION('',(0.,-1.,0.));
#712=VECTOR('',#711,1.);
#713=CARTESIAN_POINT('',(658.256146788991,406.4,-23.3717322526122));
#714=LINE('',#713,#712);
#715=CARTESIAN_POINT('',(658.256146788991,406.4,-23.3717322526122));
#716=VERTEX_POINT('',#715);
#717=CARTESIAN_POINT('',(658.256146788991,0.,-23.3717322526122));
#718=VERTEX_POINT('',#717);
#719=EDGE_CURVE('E54',#716,#718,#714,.T.);
#720=ORIENTED_EDGE('',*,*,#719,.F.);
#721=CARTESIAN_POINT('',(658.256146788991,406.4,0.));
#722=VERTEX_POINT('',#721);
#723=EDGE_CURVE('E843',#722,#716,#103,.T.);
#724=ORIENTED_EDGE('',*,*,#723,.F.);
#725=DIRECTION('',(0.,-1.,0.));
#726=VECTOR('',#725,1.);
#727=CARTESIAN_POINT('',(658.256146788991,406.4,0.));
#728=LINE('',#727,#726);
#729=CARTESIAN_POINT('',(658.256146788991,0.,0.));
#730=VERTEX_POINT('',#729);
#731=EDGE_CURVE('E824',#722,#730,#728,.T.);
#732=ORIENTED_EDGE('',*,*,#731,.T.);
#733=EDGE_CURVE('E777',#730,#718,#59,.T.);
#734=ORIENTED_EDGE('',*,*,#733,.T.);
#735=EDGE_LOOP('',(#720,#724,#732,#734));
#736=FACE_BOUND('',#735,.T.);
#737=ADVANCED_FACE('F41',(#736),#23,.T.);
#738=CARTESIAN_POINT('',(0.,406.4,0.));
#739=DIRECTION('',(0.,1.,0.));
#740=DIRECTION('',(0.,0.,1.));
#741=AXIS2_PLACEMENT_3D('',#738,#739,#740);
#742=PLANE('',#741);
#743=DIRECTION('',(1.,0.,0.));
#744=VECTOR('',#743,1.);
#745=CARTESIAN_POINT('',(670.956146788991,406.4,-48.7717322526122));
#746=LINE('',#745,#744);
#747=CARTESIAN_POINT('',(632.856146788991,406.4,-48.7717322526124));
#748=VERTEX_POINT('',#747);
#749=EDGE_CURVE('E719',#748,#53,#746,.T.);
#750=ORIENTED_EDGE('',*,*,#749,.T.);
#751=ORIENTED_EDGE('',*,*,#104,.T.);
#752=DIRECTION('',(1.,0.,0.));
#753=VECTOR('',#752,1.);
#754=CARTESIAN_POINT('',(0.,406.4,-127.));
#755=LINE('',#754,#753);
#756=CARTESIAN_POINT('',(0.,406.4,-127.));
#757=VERTEX_POINT('',#756);
#758=EDGE_CURVE('E819',#757,#97,#755,.T.);
#759=ORIENTED_EDGE('',*,*,#758,.F.);
#760=DIRECTION('',(0.,0.,-1.));
#761=VECTOR('',#760,1.);
#762=CARTESIAN_POINT('',(0.,406.4,0.));
#763=LINE('',#762,#761);
#764=CARTESIAN_POINT('',(0.,406.4,0.));
#765=VERTEX_POINT('',#764);
#766=EDGE_CURVE('E1161',#765,#757,#763,.T.);
#767=ORIENTED_EDGE('',*,*,#766,.F.);
#768=DIRECTION('',(1.,0.,0.));
#769=VECTOR('',#768,1.);
#770=CARTESIAN_POINT('',(0.,406.4,0.));
#771=LINE('',#770,#769);
#772=CARTESIAN_POINT('',(101.6,406.4,-5.6843418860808E-11));
#773=VERTEX_POINT('',#772);
#774=EDGE_CURVE('E778',#765,#773,#771,.T.);
#775=ORIENTED_EDGE('',*,*,#774,.T.);
#776=DIRECTION('',(0.,0.,1.));
#777=VECTOR('',#776,1.);
#778=CARTESIAN_POINT('',(101.6,406.4,-25.4000000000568));
#779=LINE('',#778,#777);
#780=CARTESIAN_POINT('',(101.6,406.4,-25.4000000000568));
#781=VERTEX_POINT('',#780);
#782=EDGE_CURVE('E1138',#781,#773,#779,.T.);
#783=ORIENTED_EDGE('',*,*,#782,.F.);
#784=DIRECTION('',(-1.,0.,0.));
#785=VECTOR('',#784,1.);
#786=CARTESIAN_POINT('',(181.6,406.4,-25.4000000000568));
#787=LINE('',#786,#785);
#788=CARTESIAN_POINT('',(181.6,406.4,-25.4000000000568));
#789=VERTEX_POINT('',#788);
#790=EDGE_CURVE('E1132',#789,#781,#787,.T.);
#791=ORIENTED_EDGE('',*,*,#790,.F.);
#792=DIRECTION('',(0.,0.,-1.));
#793=VECTOR('',#792,1.);
#794=CARTESIAN_POINT('',(181.6,406.4,-5.6843418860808E-11));
#795=LINE('',#794,#793);
#796=CARTESIAN_POINT('',(181.6,406.4,-5.6843418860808E-11));
#797=VERTEX_POINT('',#796);
#798=EDGE_CURVE('E1129',#797,#789,#795,.T.);
#799=ORIENTED_EDGE('',*,*,#798,.F.);
#800=EDGE_CURVE('E782',#797,#722,#771,.T.);
#801=ORIENTED_EDGE('',*,*,#800,.T.);
#802=ORIENTED_EDGE('',*,*,#723,.T.);
#803=DIRECTION('',(-1.,0.,0.));
#804=VECTOR('',#803,1.);
#805=CARTESIAN_POINT('',(670.956146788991,406.4,-23.3717322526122));
#806=LINE('',#805,#804);
#807=CARTESIAN_POINT('',(632.856146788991,406.4,-23.3717322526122));
#808=VERTEX_POINT('',#807);
#809=EDGE_CURVE('E3132',#716,#808,#806,.T.);
#810=ORIENTED_EDGE('',*,*,#809,.T.);
#811=DIRECTION('',(0.,0.,1.));
#812=VECTOR('',#811,1.);
#813=CARTESIAN_POINT('',(632.856146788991,406.4,-13.8467322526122));
#814=LINE('',#813,#812);
#815=CARTESIAN_POINT('',(632.856146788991,406.4,-13.8467322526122));
#816=VERTEX_POINT('',#815);
#817=EDGE_CURVE('E716',#808,#816,#814,.T.);
#818=ORIENTED_EDGE('',*,*,#817,.T.);
#819=DIRECTION('',(-1.,0.,0.));
#820=VECTOR('',#819,1.);
#821=CARTESIAN_POINT('',(632.856146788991,406.4,-13.8467322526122));
#822=LINE('',#821,#820);
#823=CARTESIAN_POINT('',(611.821771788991,406.4,-13.8467322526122));
#824=VERTEX_POINT('',#823);
#825=EDGE_CURVE('E4230',#816,#824,#822,.T.);
#826=ORIENTED_EDGE('',*,*,#825,.T.);
#827=DIRECTION('',(0.,0.,-1.));
#828=VECTOR('',#827,1.);
#829=CARTESIAN_POINT('',(611.821771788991,406.4,-13.8467322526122));
#830=LINE('',#829,#828);
#831=CARTESIAN_POINT('',(611.821771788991,406.4,-58.2967322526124));
#832=VERTEX_POINT('',#831);
#833=EDGE_CURVE('E4234',#824,#832,#830,.T.);
#834=ORIENTED_EDGE('',*,*,#833,.T.);
#835=DIRECTION('',(1.,0.,0.));
#836=VECTOR('',#835,1.);
#837=CARTESIAN_POINT('',(632.856146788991,406.4,-58.2967322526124));
#838=LINE('',#837,#836);
#839=CARTESIAN_POINT('',(632.856146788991,406.4,-58.2967322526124));
#840=VERTEX_POINT('',#839);
#841=EDGE_CURVE('E4239',#832,#840,#838,.T.);
#842=ORIENTED_EDGE('',*,*,#841,.T.);
#843=DIRECTION('',(0.,0.,1.));
#844=VECTOR('',#843,1.);
#845=CARTESIAN_POINT('',(632.856146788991,406.4,-48.7717322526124));
#846=LINE('',#845,#844);
#847=EDGE_CURVE('E4243',#840,#748,#846,.T.);
#848=ORIENTED_EDGE('',*,*,#847,.T.);
#849=EDGE_LOOP('',(#750,#751,#759,#767,#775,#783,#791,#799,#801,#802,#810,#818,#826,#834,#842,#848));
#850=FACE_BOUND('',#849,.T.);
#851=DIRECTION('',(0.,0.,1.));
#852=VECTOR('',#851,1.);
#853=CARTESIAN_POINT('',(25.4,406.4,-101.6));
#854=LINE('',#853,#852);
#855=CARTESIAN_POINT('',(25.4,406.4,-88.9));
#856=VERTEX_POINT('',#855);
#857=CARTESIAN_POINT('',(25.4,406.4,-50.8));
#858=VERTEX_POINT('',#857);
#859=EDGE_CURVE('E770',#856,#858,#854,.T.);
#860=ORIENTED_EDGE('',*,*,#859,.F.);
#861=CARTESIAN_POINT('',(38.1,406.4,-88.9));
#862=DIRECTION('',(0.,1.,0.));
#863=DIRECTION('',(0.,0.,1.));
#864=AXIS2_PLACEMENT_3D('',#861,#862,#863);
#865=CIRCLE('',#864,12.7);
#866=CARTESIAN_POINT('',(38.1,406.4,-101.6));
#867=VERTEX_POINT('',#866);
#868=EDGE_CURVE('E1039',#856,#867,#865,.F.);
#869=ORIENTED_EDGE('',*,*,#868,.T.);
#870=DIRECTION('',(-1.,0.,0.));
#871=VECTOR('',#870,1.);
#872=CARTESIAN_POINT('',(533.4,406.4,-101.6));
#873=LINE('',#872,#871);
#874=CARTESIAN_POINT('',(520.7,406.4,-101.6));
#875=VERTEX_POINT('',#874);
#876=EDGE_CURVE('E967',#875,#867,#873,.T.);
#877=ORIENTED_EDGE('',*,*,#876,.F.);
#878=CARTESIAN_POINT('',(520.7,406.4,-88.9));
#879=DIRECTION('',(0.,1.,0.));
#880=DIRECTION('',(0.,0.,1.));
#881=AXIS2_PLACEMENT_3D('',#878,#879,#880);
#882=CIRCLE('',#881,12.7);
#883=CARTESIAN_POINT('',(533.4,406.4,-88.9));
#884=VERTEX_POINT('',#883);
#885=EDGE_CURVE('E1540',#875,#884,#882,.F.);
#886=ORIENTED_EDGE('',*,*,#885,.T.);
#887=DIRECTION('',(0.,0.,-1.));
#888=VECTOR('',#887,1.);
#889=CARTESIAN_POINT('',(533.4,406.4,-38.1));
#890=LINE('',#889,#888);
#891=CARTESIAN_POINT('',(533.4,406.4,-50.8));
#892=VERTEX_POINT('',#891);
#893=EDGE_CURVE('E973',#892,#884,#890,.T.);
#894=ORIENTED_EDGE('',*,*,#893,.F.);
#895=CARTESIAN_POINT('',(520.7,406.4,-50.8));
#896=DIRECTION('',(0.,1.,0.));
#897=DIRECTION('',(0.,0.,1.));
#898=AXIS2_PLACEMENT_3D('',#895,#896,#897);
#899=CIRCLE('',#898,12.7);
#900=CARTESIAN_POINT('',(520.7,406.4,-38.1));
#901=VERTEX_POINT('',#900);
#902=EDGE_CURVE('E1546',#892,#901,#899,.F.);
#903=ORIENTED_EDGE('',*,*,#902,.T.);
#904=DIRECTION('',(1.,0.,0.));
#905=VECTOR('',#904,1.);
#906=CARTESIAN_POINT('',(25.4,406.4,-38.1));
#907=LINE('',#906,#905);
#908=CARTESIAN_POINT('',(38.1,406.4,-38.1));
#909=VERTEX_POINT('',#908);
#910=EDGE_CURVE('E1525',#909,#901,#907,.T.);
#911=ORIENTED_EDGE('',*,*,#910,.F.);
#912=CARTESIAN_POINT('',(38.1,406.4,-50.8));
#913=DIRECTION('',(0.,1.,0.));
#914=DIRECTION('',(0.,0.,1.));
#915=AXIS2_PLACEMENT_3D('',#912,#913,#914);
#916=CIRCLE('',#915,12.7);
#917=EDGE_CURVE('E1557',#909,#858,#916,.F.);
#918=ORIENTED_EDGE('',*,*,#917,.T.);
#919=EDGE_LOOP('',(#860,#869,#877,#886,#894,#903,#911,#918));
#920=FACE_BOUND('',#919,.T.);
#921=ADVANCED_FACE('F1156',(#850,#920),#742,.T.);
#922=CARTESIAN_POINT('',(0.,0.,0.));
#923=DIRECTION('',(-1.,0.,0.));
#924=DIRECTION('',(0.,0.,1.));
#925=AXIS2_PLACEMENT_3D('',#922,#923,#924);
#926=PLANE('',#925);
#927=CARTESIAN_POINT('',(0.,19.05,-19.05));
#928=DIRECTION('',(-1.,0.,0.));
#929=DIRECTION('',(0.,0.,1.));
#930=AXIS2_PLACEMENT_3D('',#927,#928,#929);
#931=CIRCLE('',#930,6.35);
#932=CARTESIAN_POINT('',(0.,12.7,-19.05));
#933=VERTEX_POINT('',#932);
#934=CARTESIAN_POINT('',(0.,19.05,-12.7));
#935=VERTEX_POINT('',#934);
#936=EDGE_CURVE('E941',#933,#935,#931,.T.);
#937=ORIENTED_EDGE('',*,*,#936,.F.);
#938=DIRECTION('',(0.,0.,1.));
#939=VECTOR('',#938,1.);
#940=CARTESIAN_POINT('',(0.,12.7,-107.95));
#941=LINE('',#940,#939);
#942=CARTESIAN_POINT('',(0.,12.7,-107.95));
#943=VERTEX_POINT('',#942);
#944=EDGE_CURVE('E3669',#943,#933,#941,.T.);
#945=ORIENTED_EDGE('',*,*,#944,.F.);
#946=CARTESIAN_POINT('',(0.,19.05,-107.95));
#947=DIRECTION('',(-1.,0.,0.));
#948=DIRECTION('',(0.,0.,1.));
#949=AXIS2_PLACEMENT_3D('',#946,#947,#948);
#950=CIRCLE('',#949,6.35);
#951=CARTESIAN_POINT('',(0.,19.05,-114.3));
#952=VERTEX_POINT('',#951);
#953=EDGE_CURVE('E3672',#952,#943,#950,.T.);
#954=ORIENTED_EDGE('',*,*,#953,.F.);
#955=DIRECTION('',(0.,-1.,0.));
#956=VECTOR('',#955,1.);
#957=CARTESIAN_POINT('',(0.,82.55,-114.3));
#958=LINE('',#957,#956);
#959=CARTESIAN_POINT('',(0.,82.55,-114.3));
#960=VERTEX_POINT('',#959);
#961=EDGE_CURVE('E3676',#960,#952,#958,.T.);
#962=ORIENTED_EDGE('',*,*,#961,.F.);
#963=CARTESIAN_POINT('',(0.,82.55,-107.95));
#964=DIRECTION('',(-1.,0.,0.));
#965=DIRECTION('',(0.,0.,1.));
#966=AXIS2_PLACEMENT_3D('',#963,#964,#965);
#967=CIRCLE('',#966,6.35);
#968=CARTESIAN_POINT('',(0.,88.9,-107.95));
#969=VERTEX_POINT('',#968);
#970=EDGE_CURVE('E3680',#969,#960,#967,.T.);
#971=ORIENTED_EDGE('',*,*,#970,.F.);
#972=DIRECTION('',(0.,0.,-1.));
#973=VECTOR('',#972,1.);
#974=CARTESIAN_POINT('',(0.,88.9,-69.85));
#975=LINE('',#974,#973);
#976=CARTESIAN_POINT('',(0.,88.9,-69.85));
#977=VERTEX_POINT('',#976);
#978=EDGE_CURVE('E3688',#977,#969,#975,.T.);
#979=ORIENTED_EDGE('',*,*,#978,.F.);
#980=CARTESIAN_POINT('',(0.,95.25,-69.85));
#981=DIRECTION('',(1.,0.,0.));
#982=DIRECTION('',(0.,0.,-1.));
#983=AXIS2_PLACEMENT_3D('',#980,#981,#982);
#984=CIRCLE('',#983,6.34999999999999);
#985=CARTESIAN_POINT('',(0.,95.25,-63.5));
#986=VERTEX_POINT('',#985);
#987=EDGE_CURVE('E3691',#986,#977,#984,.T.);
#988=ORIENTED_EDGE('',*,*,#987,.F.);
#989=DIRECTION('',(0.,-1.,0.));
#990=VECTOR('',#989,1.);
#991=CARTESIAN_POINT('',(0.,323.85,-63.5));
#992=LINE('',#991,#990);
#993=CARTESIAN_POINT('',(0.,323.85,-63.5));
#994=VERTEX_POINT('',#993);
#995=EDGE_CURVE('E3695',#994,#986,#992,.T.);
#996=ORIENTED_EDGE('',*,*,#995,.F.);
#997=CARTESIAN_POINT('',(0.,323.85,-69.85));
#998=DIRECTION('',(1.,0.,0.));
#999=DIRECTION('',(0.,0.,-1.));
#1000=AXIS2_PLACEMENT_3D('',#997,#998,#999);
#1001=CIRCLE('',#1000,6.34999999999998);
#1002=CARTESIAN_POINT('',(0.,330.2,-69.85));
#1003=VERTEX_POINT('',#1002);
#1004=EDGE_CURVE('E3699',#1003,#994,#1001,.T.);
#1005=ORIENTED_EDGE('',*,*,#1004,.F.);
#1006=DIRECTION('',(0.,0.,1.));
#1007=VECTOR('',#1006,1.);
#1008=CARTESIAN_POINT('',(0.,330.2,-107.95));
#1009=LINE('',#1008,#1007);
#1010=CARTESIAN_POINT('',(0.,330.2,-107.95));
#1011=VERTEX_POINT('',#1010);
#1012=EDGE_CURVE('E3707',#1011,#1003,#1009,.T.);
#1013=ORIENTED_EDGE('',*,*,#1012,.F.);
#1014=CARTESIAN_POINT('',(0.,336.55,-107.95));
#1015=DIRECTION('',(-1.,0.,0.));
#1016=DIRECTION('',(0.,0.,1.));
#1017=AXIS2_PLACEMENT_3D('',#1014,#1015,#1016);
#1018=CIRCLE('',#1017,6.35000000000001);
#1019=CARTESIAN_POINT('',(0.,336.55,-114.3));
#1020=VERTEX_POINT('',#1019);
#1021=EDGE_CURVE('E3710',#1020,#1011,#1018,.T.);
#1022=ORIENTED_EDGE('',*,*,#1021,.F.);
#1023=DIRECTION('',(0.,-1.,0.));
#1024=VECTOR('',#1023,1.);
#1025=CARTESIAN_POINT('',(0.,387.35,-114.3));
#1026=LINE('',#1025,#1024);
#1027=CARTESIAN_POINT('',(0.,387.35,-114.3));
#1028=VERTEX_POINT('',#1027);
#1029=EDGE_CURVE('E3714',#1028,#1020,#1026,.T.);
#1030=ORIENTED_EDGE('',*,*,#1029,.F.);
#1031=CARTESIAN_POINT('',(0.,387.35,-107.95));
#1032=DIRECTION('',(-1.,0.,0.));
#1033=DIRECTION('',(0.,0.,1.));
#1034=AXIS2_PLACEMENT_3D('',#1031,#1032,#1033);
#1035=CIRCLE('',#1034,6.34999999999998);
#1036=CARTESIAN_POINT('',(0.,393.7,-107.95));
#1037=VERTEX_POINT('',#1036);
#1038=EDGE_CURVE('E3718',#1037,#1028,#1035,.T.);
#1039=ORIENTED_EDGE('',*,*,#1038,.F.);
#1040=DIRECTION('',(0.,0.,-1.));
#1041=VECTOR('',#1040,1.);
#1042=CARTESIAN_POINT('',(0.,393.7,-19.05));
#1043=LINE('',#1042,#1041);
#1044=CARTESIAN_POINT('',(0.,393.7,-19.05));
#1045=VERTEX_POINT('',#1044);
#1046=EDGE_CURVE('E3726',#1045,#1037,#1043,.T.);
#1047=ORIENTED_EDGE('',*,*,#1046,.F.);
#1048=CARTESIAN_POINT('',(0.,387.35,-19.05));
#1049=DIRECTION('',(-1.,0.,0.));
#1050=DIRECTION('',(0.,0.,1.));
#1051=AXIS2_PLACEMENT_3D('',#1048,#1049,#1050);
#1052=CIRCLE('',#1051,6.34999999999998);
#1053=CARTESIAN_POINT('',(0.,387.35,-12.7));
#1054=VERTEX_POINT('',#1053);
#1055=EDGE_CURVE('E3729',#1054,#1045,#1052,.T.);
#1056=ORIENTED_EDGE('',*,*,#1055,.F.);
#1057=DIRECTION('',(0.,1.,0.));
#1058=VECTOR('',#1057,1.);
#1059=CARTESIAN_POINT('',(0.,19.05,-12.7));
#1060=LINE('',#1059,#1058);
#1061=EDGE_CURVE('E3732',#935,#1054,#1060,.T.);
#1062=ORIENTED_EDGE('',*,*,#1061,.F.);
#1063=EDGE_LOOP('',(#937,#945,#954,#962,#971,#979,#988,#996,#1005,#1013,#1022,#1030,#1039,#1047,
#1056,#1062));
#1064=FACE_BOUND('',#1063,.T.);
#1065=DIRECTION('',(0.,0.,-1.));
#1066=VECTOR('',#1065,1.);
#1067=CARTESIAN_POINT('',(0.,101.6,-76.2));
#1068=LINE('',#1067,#1066);
#1069=CARTESIAN_POINT('',(0.,101.6,-76.2));
#1070=VERTEX_POINT('',#1069);
#1071=EDGE_CURVE('E1348',#1070,#690,#1068,.T.);
#1072=ORIENTED_EDGE('',*,*,#1071,.T.);
#1073=ORIENTED_EDGE('',*,*,#706,.F.);
#1074=DIRECTION('',(0.,0.,-1.));
#1075=VECTOR('',#1074,1.);
#1076=CARTESIAN_POINT('',(0.,0.,0.));
#1077=LINE('',#1076,#1075);
#1078=CARTESIAN_POINT('',(0.,0.,0.));
#1079=VERTEX_POINT('',#1078);
#1080=EDGE_CURVE('E780',#1079,#699,#1077,.T.);
#1081=ORIENTED_EDGE('',*,*,#1080,.F.);
#1082=DIRECTION('',(0.,1.,0.));
#1083=VECTOR('',#1082,1.);
#1084=CARTESIAN_POINT('',(0.,0.,0.));
#1085=LINE('',#1084,#1083);
#1086=EDGE_CURVE('E841',#1079,#765,#1085,.T.);
#1087=ORIENTED_EDGE('',*,*,#1086,.T.);
#1088=ORIENTED_EDGE('',*,*,#766,.T.);
#1089=CARTESIAN_POINT('',(0.,317.5,-127.));
#1090=VERTEX_POINT('',#1089);
#1091=EDGE_CURVE('E814',#1090,#757,#705,.T.);
#1092=ORIENTED_EDGE('',*,*,#1091,.F.);
#1093=DIRECTION('',(0.,0.,1.));
#1094=VECTOR('',#1093,1.);
#1095=CARTESIAN_POINT('',(0.,317.5,-127.));
#1096=LINE('',#1095,#1094);
#1097=CARTESIAN_POINT('',(0.,317.5,-76.2));
#1098=VERTEX_POINT('',#1097);
#1099=EDGE_CURVE('E1349',#1090,#1098,#1096,.T.);
#1100=ORIENTED_EDGE('',*,*,#1099,.T.);
#1101=DIRECTION('',(0.,-1.,0.));
#1102=VECTOR('',#1101,1.);
#1103=CARTESIAN_POINT('',(0.,317.5,-76.2));
#1104=LINE('',#1103,#1102);
#1105=EDGE_CURVE('E1321',#1098,#1070,#1104,.T.);
#1106=ORIENTED_EDGE('',*,*,#1105,.T.);
#1107=EDGE_LOOP('',(#1072,#1073,#1081,#1087,#1088,#1092,#1100,#1106));
#1108=FACE_BOUND('',#1107,.T.);
#1109=ADVANCED_FACE('F2139',(#1064,#1108),#926,.T.);
#1110=CARTESIAN_POINT('',(658.256146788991,0.,0.));
#1111=DIRECTION('',(0.,-1.,0.));
#1112=DIRECTION('',(0.,0.,-1.));
#1113=AXIS2_PLACEMENT_3D('',#1110,#1111,#1112);
#1114=PLANE('',#1113);
#1115=DIRECTION('',(1.,0.,0.));
#1116=VECTOR('',#1115,1.);
#1117=CARTESIAN_POINT('',(670.956146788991,0.,-48.7717322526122));
#1118=LINE('',#1117,#1116);
#1119=CARTESIAN_POINT('',(632.856146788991,0.,-48.7717322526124));
#1120=VERTEX_POINT('',#1119);
#1121=EDGE_CURVE('E774',#1120,#51,#1118,.T.);
#1122=ORIENTED_EDGE('',*,*,#1121,.F.);
#1123=DIRECTION('',(0.,0.,1.));
#1124=VECTOR('',#1123,1.);
#1125=CARTESIAN_POINT('',(632.856146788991,0.,-48.7717322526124));
#1126=LINE('',#1125,#1124);
#1127=CARTESIAN_POINT('',(632.856146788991,0.,-58.2967322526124));
#1128=VERTEX_POINT('',#1127);
#1129=EDGE_CURVE('E4259',#1128,#1120,#1126,.T.);
#1130=ORIENTED_EDGE('',*,*,#1129,.F.);
#1131=DIRECTION('',(1.,0.,0.));
#1132=VECTOR('',#1131,1.);
#1133=CARTESIAN_POINT('',(632.856146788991,0.,-58.2967322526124));
#1134=LINE('',#1133,#1132);
#1135=CARTESIAN_POINT('',(611.821771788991,0.,-58.2967322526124));
#1136=VERTEX_POINT('',#1135);
#1137=EDGE_CURVE('E4269',#1136,#1128,#1134,.T.);
#1138=ORIENTED_EDGE('',*,*,#1137,.F.);
#1139=DIRECTION('',(0.,0.,-1.));
#1140=VECTOR('',#1139,1.);
#1141=CARTESIAN_POINT('',(611.821771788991,0.,-13.8467322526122));
#1142=LINE('',#1141,#1140);
#1143=CARTESIAN_POINT('',(611.821771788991,0.,-13.8467322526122));
#1144=VERTEX_POINT('',#1143);
#1145=EDGE_CURVE('E727',#1144,#1136,#1142,.T.);
#1146=ORIENTED_EDGE('',*,*,#1145,.F.);
#1147=DIRECTION('',(-1.,0.,0.));
#1148=VECTOR('',#1147,1.);
#1149=CARTESIAN_POINT('',(632.856146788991,0.,-13.8467322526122));
#1150=LINE('',#1149,#1148);
#1151=CARTESIAN_POINT('',(632.856146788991,0.,-13.8467322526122));
#1152=VERTEX_POINT('',#1151);
#1153=EDGE_CURVE('E725',#1152,#1144,#1150,.T.);
#1154=ORIENTED_EDGE('',*,*,#1153,.F.);
#1155=DIRECTION('',(0.,0.,1.));
#1156=VECTOR('',#1155,1.);
#1157=CARTESIAN_POINT('',(632.856146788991,0.,-13.8467322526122));
#1158=LINE('',#1157,#1156);
#1159=CARTESIAN_POINT('',(632.856146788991,0.,-23.3717322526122));
#1160=VERTEX_POINT('',#1159);
#1161=EDGE_CURVE('E708',#1160,#1152,#1158,.T.);
#1162=ORIENTED_EDGE('',*,*,#1161,.F.);
#1163=DIRECTION('',(-1.,0.,0.));
#1164=VECTOR('',#1163,1.);
#1165=CARTESIAN_POINT('',(670.956146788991,0.,-23.3717322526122));
#1166=LINE('',#1165,#1164);
#1167=EDGE_CURVE('E700',#718,#1160,#1166,.T.);
#1168=ORIENTED_EDGE('',*,*,#1167,.F.);
#1169=ORIENTED_EDGE('',*,*,#733,.F.);
#1170=DIRECTION('',(-1.,0.,0.));
#1171=VECTOR('',#1170,1.);
#1172=CARTESIAN_POINT('',(658.256146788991,0.,0.));
#1173=LINE('',#1172,#1171);
#1174=CARTESIAN_POINT('',(508.,0.,0.));
#1175=VERTEX_POINT('',#1174);
#1176=EDGE_CURVE('E829',#730,#1175,#1173,.T.);
#1177=ORIENTED_EDGE('',*,*,#1176,.T.);
#1178=DIRECTION('',(0.,0.,1.));
#1179=VECTOR('',#1178,1.);
#1180=CARTESIAN_POINT('',(508.,0.,-25.4000000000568));
#1181=LINE('',#1180,#1179);
#1182=CARTESIAN_POINT('',(508.,0.,-25.4000000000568));
#1183=VERTEX_POINT('',#1182);
#1184=EDGE_CURVE('E4298',#1183,#1175,#1181,.T.);
#1185=ORIENTED_EDGE('',*,*,#1184,.F.);
#1186=DIRECTION('',(1.,0.,0.));
#1187=VECTOR('',#1186,1.);
#1188=CARTESIAN_POINT('',(428.,0.,-25.4000000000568));
#1189=LINE('',#1188,#1187);
#1190=CARTESIAN_POINT('',(428.,0.,-25.4000000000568));
#1191=VERTEX_POINT('',#1190);
#1192=EDGE_CURVE('E890',#1191,#1183,#1189,.T.);
#1193=ORIENTED_EDGE('',*,*,#1192,.F.);
#1194=DIRECTION('',(0.,0.,1.));
#1195=VECTOR('',#1194,1.);
#1196=CARTESIAN_POINT('',(428.,0.,-25.4000000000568));
#1197=LINE('',#1196,#1195);
#1198=CARTESIAN_POINT('',(428.,0.,0.));
#1199=VERTEX_POINT('',#1198);
#1200=EDGE_CURVE('E3652',#1191,#1199,#1197,.T.);
#1201=ORIENTED_EDGE('',*,*,#1200,.T.);
#1202=EDGE_CURVE('E828',#1199,#1079,#1173,.T.);
#1203=ORIENTED_EDGE('',*,*,#1202,.T.);
#1204=ORIENTED_EDGE('',*,*,#1080,.T.);
#1205=ORIENTED_EDGE('',*,*,#700,.F.);
#1206=ORIENTED_EDGE('',*,*,#62,.F.);
#1207=EDGE_LOOP('',(#1122,#1130,#1138,#1146,#1154,#1162,#1168,#1169,#1177,#1185,#1193,#1201,
#1203,#1204,#1205,#1206));
#1208=FACE_BOUND('',#1207,.T.);
#1209=DIRECTION('',(-1.,0.,0.));
#1210=VECTOR('',#1209,1.);
#1211=CARTESIAN_POINT('',(533.4,0.,-38.0999999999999));
#1212=LINE('',#1211,#1210);
#1213=CARTESIAN_POINT('',(520.7,0.,-38.0999999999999));
#1214=VERTEX_POINT('',#1213);
#1215=CARTESIAN_POINT('',(38.1,0.,-38.1));
#1216=VERTEX_POINT('',#1215);
#1217=EDGE_CURVE('E956',#1214,#1216,#1212,.T.);
#1218=ORIENTED_EDGE('',*,*,#1217,.F.);
#1219=CARTESIAN_POINT('',(520.7,0.,-50.7999999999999));
#1220=DIRECTION('',(0.,-1.,0.));
#1221=DIRECTION('',(0.,0.,-1.));
#1222=AXIS2_PLACEMENT_3D('',#1219,#1220,#1221);
#1223=CIRCLE('',#1222,12.7);
#1224=CARTESIAN_POINT('',(533.4,0.,-50.7999999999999));
#1225=VERTEX_POINT('',#1224);
#1226=EDGE_CURVE('E1078',#1214,#1225,#1223,.F.);
#1227=ORIENTED_EDGE('',*,*,#1226,.T.);
#1228=DIRECTION('',(0.,0.,1.));
#1229=VECTOR('',#1228,1.);
#1230=CARTESIAN_POINT('',(533.4,0.,-101.6));
#1231=LINE('',#1230,#1229);
#1232=CARTESIAN_POINT('',(533.4,0.,-88.9));
#1233=VERTEX_POINT('',#1232);
#1234=EDGE_CURVE('E961',#1233,#1225,#1231,.T.);
#1235=ORIENTED_EDGE('',*,*,#1234,.F.);
#1236=CARTESIAN_POINT('',(520.7,0.,-88.9));
#1237=DIRECTION('',(0.,-1.,0.));
#1238=DIRECTION('',(0.,0.,-1.));
#1239=AXIS2_PLACEMENT_3D('',#1236,#1237,#1238);
#1240=CIRCLE('',#1239,12.7);
#1241=CARTESIAN_POINT('',(520.7,0.,-101.6));
#1242=VERTEX_POINT('',#1241);
#1243=EDGE_CURVE('E1045',#1233,#1242,#1240,.F.);
#1244=ORIENTED_EDGE('',*,*,#1243,.T.);
#1245=DIRECTION('',(1.,0.,0.));
#1246=VECTOR('',#1245,1.);
#1247=CARTESIAN_POINT('',(25.4,0.,-101.6));
#1248=LINE('',#1247,#1246);
#1249=CARTESIAN_POINT('',(38.1,0.,-101.6));
#1250=VERTEX_POINT('',#1249);
#1251=EDGE_CURVE('E955',#1250,#1242,#1248,.T.);
#1252=ORIENTED_EDGE('',*,*,#1251,.F.);
#1253=CARTESIAN_POINT('',(38.1,0.,-88.9));
#1254=DIRECTION('',(0.,-1.,0.));
#1255=DIRECTION('',(0.,0.,-1.));
#1256=AXIS2_PLACEMENT_3D('',#1253,#1254,#1255);
#1257=CIRCLE('',#1256,12.7);
#1258=CARTESIAN_POINT('',(25.4,0.,-88.9));
#1259=VERTEX_POINT('',#1258);
#1260=EDGE_CURVE('E12',#1250,#1259,#1257,.F.);
#1261=ORIENTED_EDGE('',*,*,#1260,.T.);
#1262=DIRECTION('',(0.,0.,-1.));
#1263=VECTOR('',#1262,1.);
#1264=CARTESIAN_POINT('',(25.4,0.,-38.1));
#1265=LINE('',#1264,#1263);
#1266=CARTESIAN_POINT('',(25.4,0.,-50.8));
#1267=VERTEX_POINT('',#1266);
#1268=EDGE_CURVE('E951',#1267,#1259,#1265,.T.);
#1269=ORIENTED_EDGE('',*,*,#1268,.F.);
#1270=CARTESIAN_POINT('',(38.1,0.,-50.8));
#1271=DIRECTION('',(0.,-1.,0.));
#1272=DIRECTION('',(0.,0.,-1.));
#1273=AXIS2_PLACEMENT_3D('',#1270,#1271,#1272);
#1274=CIRCLE('',#1273,12.7);
#1275=EDGE_CURVE('E1005',#1267,#1216,#1274,.F.);
#1276=ORIENTED_EDGE('',*,*,#1275,.T.);
#1277=EDGE_LOOP('',(#1218,#1227,#1235,#1244,#1252,#1261,#1269,#1276));
#1278=FACE_BOUND('',#1277,.T.);
#1279=ADVANCED_FACE('F722',(#1208,#1278),#1114,.T.);
#1280=CARTESIAN_POINT('',(658.256146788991,0.,0.));
#1281=DIRECTION('',(0.,0.,-1.));
#1282=DIRECTION('',(-1.,0.,0.));
#1283=AXIS2_PLACEMENT_3D('',#1280,#1281,#1282);
#1284=PLANE('',#1283);
#1285=DIRECTION('',(1.,0.,0.));
#1286=VECTOR('',#1285,1.);
#1287=CARTESIAN_POINT('',(165.1,95.25,0.));
#1288=LINE('',#1287,#1286);
#1289=CARTESIAN_POINT('',(165.1,95.25,0.));
#1290=VERTEX_POINT('',#1289);
#1291=CARTESIAN_POINT('',(444.5,95.25,0.));
#1292=VERTEX_POINT('',#1291);
#1293=EDGE_CURVE('E3267',#1290,#1292,#1288,.T.);
#1294=ORIENTED_EDGE('',*,*,#1293,.F.);
#1295=CARTESIAN_POINT('',(152.4,95.25,0.));
#1296=DIRECTION('',(0.,0.,1.));
#1297=DIRECTION('',(1.,0.,0.));
#1298=AXIS2_PLACEMENT_3D('',#1295,#1296,#1297);
#1299=CIRCLE('',#1298,12.7);
#1300=CARTESIAN_POINT('',(152.4,107.95,0.));
#1301=VERTEX_POINT('',#1300);
#1302=EDGE_CURVE('E3261',#1301,#1290,#1299,.T.);
#1303=ORIENTED_EDGE('',*,*,#1302,.F.);
#1304=DIRECTION('',(0.,-1.,0.));
#1305=VECTOR('',#1304,1.);
#1306=CARTESIAN_POINT('',(152.4,298.45,0.));
#1307=LINE('',#1306,#1305);
#1308=CARTESIAN_POINT('',(152.4,298.45,0.));
#1309=VERTEX_POINT('',#1308);
#1310=EDGE_CURVE('E3276',#1309,#1301,#1307,.T.);
#1311=ORIENTED_EDGE('',*,*,#1310,.F.);
#1312=CARTESIAN_POINT('',(152.4,311.15,0.));
#1313=DIRECTION('',(0.,0.,1.));
#1314=DIRECTION('',(1.,0.,0.));
#1315=AXIS2_PLACEMENT_3D('',#1312,#1313,#1314);
#1316=CIRCLE('',#1315,12.7);
#1317=CARTESIAN_POINT('',(165.1,311.15,0.));
#1318=VERTEX_POINT('',#1317);
#1319=EDGE_CURVE('E3281',#1318,#1309,#1316,.T.);
#1320=ORIENTED_EDGE('',*,*,#1319,.F.);
#1321=DIRECTION('',(-1.,0.,0.));
#1322=VECTOR('',#1321,1.);
#1323=CARTESIAN_POINT('',(444.5,311.15,0.));
#1324=LINE('',#1323,#1322);
#1325=CARTESIAN_POINT('',(444.5,311.15,0.));
#1326=VERTEX_POINT('',#1325);
#1327=EDGE_CURVE('E3339',#1326,#1318,#1324,.T.);
#1328=ORIENTED_EDGE('',*,*,#1327,.F.);
#1329=CARTESIAN_POINT('',(457.2,311.15,0.));
#1330=DIRECTION('',(0.,0.,1.));
#1331=DIRECTION('',(1.,0.,0.));
#1332=AXIS2_PLACEMENT_3D('',#1329,#1330,#1331);
#1333=CIRCLE('',#1332,12.7);
#1334=CARTESIAN_POINT('',(457.2,298.45,0.));
#1335=VERTEX_POINT('',#1334);
#1336=EDGE_CURVE('E3336',#1335,#1326,#1333,.T.);
#1337=ORIENTED_EDGE('',*,*,#1336,.F.);
#1338=DIRECTION('',(0.,1.,0.));
#1339=VECTOR('',#1338,1.);
#1340=CARTESIAN_POINT('',(457.2,107.95,0.));
#1341=LINE('',#1340,#1339);
#1342=CARTESIAN_POINT('',(457.2,107.95,0.));
#1343=VERTEX_POINT('',#1342);
#1344=EDGE_CURVE('E3343',#1343,#1335,#1341,.T.);
#1345=ORIENTED_EDGE('',*,*,#1344,.F.);
#1346=CARTESIAN_POINT('',(457.2,95.25,0.));
#1347=DIRECTION('',(0.,0.,1.));
#1348=DIRECTION('',(1.,0.,0.));
#1349=AXIS2_PLACEMENT_3D('',#1346,#1347,#1348);
#1350=CIRCLE('',#1349,12.7);
#1351=EDGE_CURVE('E3330',#1292,#1343,#1350,.T.);
#1352=ORIENTED_EDGE('',*,*,#1351,.F.);
#1353=EDGE_LOOP('',(#1294,#1303,#1311,#1320,#1328,#1337,#1345,#1352));
#1354=FACE_BOUND('',#1353,.T.);
#1355=DIRECTION('',(1.,0.,0.));
#1356=VECTOR('',#1355,1.);
#1357=CARTESIAN_POINT('',(508.,101.6,0.));
#1358=LINE('',#1357,#1356);
#1359=CARTESIAN_POINT('',(514.35,101.6,0.));
#1360=VERTEX_POINT('',#1359);
#1361=CARTESIAN_POINT('',(552.45,101.6,0.));
#1362=VERTEX_POINT('',#1361);
#1363=EDGE_CURVE('E3994',#1360,#1362,#1358,.T.);
#1364=ORIENTED_EDGE('',*,*,#1363,.F.);
#1365=CARTESIAN_POINT('',(514.35,107.95,0.));
#1366=DIRECTION('',(0.,0.,-1.));
#1367=DIRECTION('',(-1.,0.,0.));
#1368=AXIS2_PLACEMENT_3D('',#1365,#1366,#1367);
#1369=CIRCLE('',#1368,6.35);
#1370=CARTESIAN_POINT('',(508.,107.95,0.));
#1371=VERTEX_POINT('',#1370);
#1372=EDGE_CURVE('E1452',#1360,#1371,#1369,.T.);
#1373=ORIENTED_EDGE('',*,*,#1372,.T.);
#1374=DIRECTION('',(0.,-1.,0.));
#1375=VECTOR('',#1374,1.);
#1376=CARTESIAN_POINT('',(508.,304.8,0.));
#1377=LINE('',#1376,#1375);
#1378=CARTESIAN_POINT('',(508.,298.45,0.));
#1379=VERTEX_POINT('',#1378);
#1380=EDGE_CURVE('E3992',#1379,#1371,#1377,.T.);
#1381=ORIENTED_EDGE('',*,*,#1380,.F.);
#1382=CARTESIAN_POINT('',(514.35,298.45,0.));
#1383=DIRECTION('',(0.,0.,-1.));
#1384=DIRECTION('',(-1.,0.,0.));
#1385=AXIS2_PLACEMENT_3D('',#1382,#1383,#1384);
#1386=CIRCLE('',#1385,6.35);
#1387=CARTESIAN_POINT('',(514.35,304.8,0.));
#1388=VERTEX_POINT('',#1387);
#1389=EDGE_CURVE('E1015',#1379,#1388,#1386,.T.);
#1390=ORIENTED_EDGE('',*,*,#1389,.T.);
#1391=DIRECTION('',(-1.,0.,0.));
#1392=VECTOR('',#1391,1.);
#1393=CARTESIAN_POINT('',(558.8,304.8,0.));
#1394=LINE('',#1393,#1392);
#1395=CARTESIAN_POINT('',(552.45,304.8,0.));
#1396=VERTEX_POINT('',#1395);
#1397=EDGE_CURVE('E1268',#1396,#1388,#1394,.T.);
#1398=ORIENTED_EDGE('',*,*,#1397,.F.);
#1399=CARTESIAN_POINT('',(552.45,298.45,0.));
#1400=DIRECTION('',(0.,0.,-1.));
#1401=DIRECTION('',(-1.,0.,0.));
#1402=AXIS2_PLACEMENT_3D('',#1399,#1400,#1401);
#1403=CIRCLE('',#1402,6.35);
#1404=CARTESIAN_POINT('',(558.8,298.45,0.));
#1405=VERTEX_POINT('',#1404);
#1406=EDGE_CURVE('E1435',#1396,#1405,#1403,.T.);
#1407=ORIENTED_EDGE('',*,*,#1406,.T.);
#1408=DIRECTION('',(0.,1.,0.));
#1409=VECTOR('',#1408,1.);
#1410=CARTESIAN_POINT('',(558.8,101.6,0.));
#1411=LINE('',#1410,#1409);
#1412=CARTESIAN_POINT('',(558.8,107.95,0.));
#1413=VERTEX_POINT('',#1412);
#1414=EDGE_CURVE('E1274',#1413,#1405,#1411,.T.);
#1415=ORIENTED_EDGE('',*,*,#1414,.F.);
#1416=CARTESIAN_POINT('',(552.45,107.95,0.));
#1417=DIRECTION('',(0.,0.,-1.));
#1418=DIRECTION('',(-1.,0.,0.));
#1419=AXIS2_PLACEMENT_3D('',#1416,#1417,#1418);
#1420=CIRCLE('',#1419,6.35);
#1421=EDGE_CURVE('E1441',#1413,#1362,#1420,.T.);
#1422=ORIENTED_EDGE('',*,*,#1421,.T.);
#1423=EDGE_LOOP('',(#1364,#1373,#1381,#1390,#1398,#1407,#1415,#1422));
#1424=FACE_BOUND('',#1423,.T.);
#1425=DIRECTION('',(1.,0.,0.));
#1426=VECTOR('',#1425,1.);
#1427=CARTESIAN_POINT('',(50.8,101.6,0.));
#1428=LINE('',#1427,#1426);
#1429=CARTESIAN_POINT('',(57.15,101.6,0.));
#1430=VERTEX_POINT('',#1429);
#1431=CARTESIAN_POINT('',(95.25,101.6,0.));
#1432=VERTEX_POINT('',#1431);
#1433=EDGE_CURVE('E1467',#1430,#1432,#1428,.T.);
#1434=ORIENTED_EDGE('',*,*,#1433,.F.);
#1435=CARTESIAN_POINT('',(57.15,107.95,0.));
#1436=DIRECTION('',(0.,0.,-1.));
#1437=DIRECTION('',(-1.,0.,0.));
#1438=AXIS2_PLACEMENT_3D('',#1435,#1436,#1437);
#1439=CIRCLE('',#1438,6.35);
#1440=CARTESIAN_POINT('',(50.8,107.95,0.));
#1441=VERTEX_POINT('',#1440);
#1442=EDGE_CURVE('E1393',#1430,#1441,#1439,.T.);
#1443=ORIENTED_EDGE('',*,*,#1442,.T.);
#1444=DIRECTION('',(0.,-1.,0.));
#1445=VECTOR('',#1444,1.);
#1446=CARTESIAN_POINT('',(50.8,304.8,0.));
#1447=LINE('',#1446,#1445);
#1448=CARTESIAN_POINT('',(50.8,298.45,0.));
#1449=VERTEX_POINT('',#1448);
#1450=EDGE_CURVE('E1470',#1449,#1441,#1447,.T.);
#1451=ORIENTED_EDGE('',*,*,#1450,.F.);
#1452=CARTESIAN_POINT('',(57.15,298.45,0.));
#1453=DIRECTION('',(0.,0.,-1.));
#1454=DIRECTION('',(-1.,0.,0.));
#1455=AXIS2_PLACEMENT_3D('',#1452,#1453,#1454);
#1456=CIRCLE('',#1455,6.35);
#1457=CARTESIAN_POINT('',(57.15,304.8,0.));
#1458=VERTEX_POINT('',#1457);
#1459=EDGE_CURVE('E1411',#1449,#1458,#1456,.T.);
#1460=ORIENTED_EDGE('',*,*,#1459,.T.);
#1461=DIRECTION('',(-1.,0.,0.));
#1462=VECTOR('',#1461,1.);
#1463=CARTESIAN_POINT('',(101.6,304.8,0.));
#1464=LINE('',#1463,#1462);
#1465=CARTESIAN_POINT('',(95.25,304.8,0.));
#1466=VERTEX_POINT('',#1465);
#1467=EDGE_CURVE('E1367',#1466,#1458,#1464,.T.);
#1468=ORIENTED_EDGE('',*,*,#1467,.F.);
#1469=CARTESIAN_POINT('',(95.25,298.45,0.));
#1470=DIRECTION('',(0.,0.,-1.));
#1471=DIRECTION('',(-1.,0.,0.));
#1472=AXIS2_PLACEMENT_3D('',#1469,#1470,#1471);
#1473=CIRCLE('',#1472,6.35);
#1474=CARTESIAN_POINT('',(101.6,298.45,0.));
#1475=VERTEX_POINT('',#1474);
#1476=EDGE_CURVE('E1484',#1466,#1475,#1473,.T.);
#1477=ORIENTED_EDGE('',*,*,#1476,.T.);
#1478=DIRECTION('',(0.,1.,0.));
#1479=VECTOR('',#1478,1.);
#1480=CARTESIAN_POINT('',(101.6,101.6,0.));
#1481=LINE('',#1480,#1479);
#1482=CARTESIAN_POINT('',(101.6,107.95,0.));
#1483=VERTEX_POINT('',#1482);
#1484=EDGE_CURVE('E1373',#1483,#1475,#1481,.T.);
#1485=ORIENTED_EDGE('',*,*,#1484,.F.);
#1486=CARTESIAN_POINT('',(95.25,107.95,0.));
#1487=DIRECTION('',(0.,0.,-1.));
#1488=DIRECTION('',(-1.,0.,0.));
#1489=AXIS2_PLACEMENT_3D('',#1486,#1487,#1488);
#1490=CIRCLE('',#1489,6.35);
#1491=EDGE_CURVE('E1491',#1483,#1432,#1490,.T.);
#1492=ORIENTED_EDGE('',*,*,#1491,.T.);
#1493=EDGE_LOOP('',(#1434,#1443,#1451,#1460,#1468,#1477,#1485,#1492));
#1494=FACE_BOUND('',#1493,.T.);
#1495=CARTESIAN_POINT('',(558.8,50.8,0.));
#1496=DIRECTION('',(0.,0.,1.));
#1497=DIRECTION('',(1.,0.,0.));
#1498=AXIS2_PLACEMENT_3D('',#1495,#1496,#1497);
#1499=CIRCLE('',#1498,28.575);
#1500=CARTESIAN_POINT('',(587.375,50.8,0.));
#1501=VERTEX_POINT('',#1500);
#1502=EDGE_CURVE('E1501',#1501,#1501,#1499,.T.);
#1503=ORIENTED_EDGE('',*,*,#1502,.F.);
#1504=EDGE_LOOP('',(#1503));
#1505=FACE_BOUND('',#1504,.T.);
#1506=CARTESIAN_POINT('',(50.8,50.8,0.));
#1507=DIRECTION('',(0.,0.,1.));
#1508=DIRECTION('',(1.,0.,0.));
#1509=AXIS2_PLACEMENT_3D('',#1506,#1507,#1508);
#1510=CIRCLE('',#1509,28.575);
#1511=CARTESIAN_POINT('',(79.375,50.8,0.));
#1512=VERTEX_POINT('',#1511);
#1513=EDGE_CURVE('E4039',#1512,#1512,#1510,.T.);
#1514=ORIENTED_EDGE('',*,*,#1513,.F.);
#1515=EDGE_LOOP('',(#1514));
#1516=FACE_BOUND('',#1515,.T.);
#1517=CARTESIAN_POINT('',(558.8,355.6,0.));
#1518=DIRECTION('',(0.,0.,1.));
#1519=DIRECTION('',(1.,0.,0.));
#1520=AXIS2_PLACEMENT_3D('',#1517,#1518,#1519);
#1521=CIRCLE('',#1520,28.575);
#1522=CARTESIAN_POINT('',(587.375,355.6,0.));
#1523=VERTEX_POINT('',#1522);
#1524=EDGE_CURVE('E3183',#1523,#1523,#1521,.T.);
#1525=ORIENTED_EDGE('',*,*,#1524,.F.);
#1526=EDGE_LOOP('',(#1525));
#1527=FACE_BOUND('',#1526,.T.);
#1528=CARTESIAN_POINT('',(50.8,355.6,0.));
#1529=DIRECTION('',(0.,0.,1.));
#1530=DIRECTION('',(1.,0.,0.));
#1531=AXIS2_PLACEMENT_3D('',#1528,#1529,#1530);
#1532=CIRCLE('',#1531,28.575);
#1533=CARTESIAN_POINT('',(79.375,355.6,0.));
#1534=VERTEX_POINT('',#1533);
#1535=EDGE_CURVE('E4045',#1534,#1534,#1532,.T.);
#1536=ORIENTED_EDGE('',*,*,#1535,.F.);
#1537=EDGE_LOOP('',(#1536));
#1538=FACE_BOUND('',#1537,.T.);
#1539=DIRECTION('',(1.,0.,0.));
#1540=VECTOR('',#1539,1.);
#1541=CARTESIAN_POINT('',(101.6,368.3,-5.6843418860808E-11));
#1542=LINE('',#1541,#1540);
#1543=CARTESIAN_POINT('',(114.3,368.3,-5.6843418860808E-11));
#1544=VERTEX_POINT('',#1543);
#1545=CARTESIAN_POINT('',(168.9,368.3,-5.6843418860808E-11));
#1546=VERTEX_POINT('',#1545);
#1547=EDGE_CURVE('E914',#1544,#1546,#1542,.T.);
#1548=ORIENTED_EDGE('',*,*,#1547,.F.);
#1549=CARTESIAN_POINT('',(114.3,381.,0.));
#1550=DIRECTION('',(0.,0.,-1.));
#1551=DIRECTION('',(-1.,0.,0.));
#1552=AXIS2_PLACEMENT_3D('',#1549,#1550,#1551);
#1553=CIRCLE('',#1552,12.7);
#1554=CARTESIAN_POINT('',(101.6,381.,-5.6843418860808E-11));
#1555=VERTEX_POINT('',#1554);
#1556=EDGE_CURVE('E1168',#1544,#1555,#1553,.T.);
#1557=ORIENTED_EDGE('',*,*,#1556,.T.);
#1558=DIRECTION('',(0.,1.,0.));
#1559=VECTOR('',#1558,1.);
#1560=CARTESIAN_POINT('',(101.6,368.3,-5.6843418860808E-11));
#1561=LINE('',#1560,#1559);
#1562=EDGE_CURVE('E917',#1555,#773,#1561,.T.);
#1563=ORIENTED_EDGE('',*,*,#1562,.T.);
#1564=ORIENTED_EDGE('',*,*,#774,.F.);
#1565=ORIENTED_EDGE('',*,*,#1086,.F.);
#1566=ORIENTED_EDGE('',*,*,#1202,.F.);
#1567=DIRECTION('',(0.,-1.,0.));
#1568=VECTOR('',#1567,1.);
#1569=CARTESIAN_POINT('',(428.,25.6903263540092,0.));
#1570=LINE('',#1569,#1568);
#1571=CARTESIAN_POINT('',(428.,25.6903263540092,0.));
#1572=VERTEX_POINT('',#1571);
#1573=EDGE_CURVE('E857',#1572,#1199,#1570,.T.);
#1574=ORIENTED_EDGE('',*,*,#1573,.F.);
#1575=CARTESIAN_POINT('',(440.7,25.6903263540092,-5.6843418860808E-11));
#1576=DIRECTION('',(0.,0.,1.));
#1577=DIRECTION('',(1.,0.,0.));
#1578=AXIS2_PLACEMENT_3D('',#1575,#1576,#1577);
#1579=CIRCLE('',#1578,12.7);
#1580=CARTESIAN_POINT('',(438.,38.1,0.));
#1581=VERTEX_POINT('',#1580);
#1582=EDGE_CURVE('E861',#1581,#1572,#1579,.T.);
#1583=ORIENTED_EDGE('',*,*,#1582,.F.);
#1584=DIRECTION('',(-1.,0.,9.473903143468E-13));
#1585=VECTOR('',#1584,1.);
#1586=CARTESIAN_POINT('',(498.,38.1,-5.6843418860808E-11));
#1587=LINE('',#1586,#1585);
#1588=CARTESIAN_POINT('',(498.,38.1,-5.6843418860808E-11));
#1589=VERTEX_POINT('',#1588);
#1590=EDGE_CURVE('E870',#1589,#1581,#1587,.T.);
#1591=ORIENTED_EDGE('',*,*,#1590,.F.);
#1592=CARTESIAN_POINT('',(495.3,25.6903263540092,-5.6843418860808E-11));
#1593=DIRECTION('',(0.,0.,1.));
#1594=DIRECTION('',(1.,0.,0.));
#1595=AXIS2_PLACEMENT_3D('',#1592,#1593,#1594);
#1596=CIRCLE('',#1595,12.7);
#1597=CARTESIAN_POINT('',(508.,25.6903263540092,0.));
#1598=VERTEX_POINT('',#1597);
#1599=EDGE_CURVE('E866',#1598,#1589,#1596,.T.);
#1600=ORIENTED_EDGE('',*,*,#1599,.F.);
#1601=DIRECTION('',(0.,1.,0.));
#1602=VECTOR('',#1601,1.);
#1603=CARTESIAN_POINT('',(508.,0.,0.));
#1604=LINE('',#1603,#1602);
#1605=EDGE_CURVE('E860',#1175,#1598,#1604,.T.);
#1606=ORIENTED_EDGE('',*,*,#1605,.F.);
#1607=ORIENTED_EDGE('',*,*,#1176,.F.);
#1608=ORIENTED_EDGE('',*,*,#731,.F.);
#1609=ORIENTED_EDGE('',*,*,#800,.F.);
#1610=DIRECTION('',(0.,1.,0.));
#1611=VECTOR('',#1610,1.);
#1612=CARTESIAN_POINT('',(181.6,368.3,-5.6843418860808E-11));
#1613=LINE('',#1612,#1611);
#1614=CARTESIAN_POINT('',(181.6,381.,-5.6843418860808E-11));
#1615=VERTEX_POINT('',#1614);
#1616=EDGE_CURVE('E913',#1615,#797,#1613,.T.);
#1617=ORIENTED_EDGE('',*,*,#1616,.F.);
#1618=CARTESIAN_POINT('',(168.9,381.,0.));
#1619=DIRECTION('',(0.,0.,-1.));
#1620=DIRECTION('',(-1.,0.,0.));
#1621=AXIS2_PLACEMENT_3D('',#1618,#1619,#1620);
#1622=CIRCLE('',#1621,12.7);
#1623=EDGE_CURVE('E1505',#1615,#1546,#1622,.T.);
#1624=ORIENTED_EDGE('',*,*,#1623,.T.);
#1625=EDGE_LOOP('',(#1548,#1557,#1563,#1564,#1565,#1566,#1574,#1583,#1591,#1600,#1606,#1607,
#1608,#1609,#1617,#1624));
#1626=FACE_BOUND('',#1625,.T.);
#1627=ADVANCED_FACE('F1166',(#1354,#1424,#1494,#1505,#1516,#1527,#1538,#1626),#1284,.F.);
#1628=CARTESIAN_POINT('',(558.8,355.6,-127.));
#1629=DIRECTION('',(0.,0.,1.));
#1630=DIRECTION('',(1.,0.,0.));
#1631=AXIS2_PLACEMENT_3D('',#1628,#1629,#1630);
#1632=CIRCLE('',#1631,19.05);
#1633=CARTESIAN_POINT('',(577.85,355.6,-127.));
#1634=VERTEX_POINT('',#1633);
#1635=EDGE_CURVE('E3189',#1634,#1634,#1632,.T.);
#1636=ORIENTED_EDGE('',*,*,#1635,.T.);
#1637=EDGE_LOOP('',(#1636));
#1638=FACE_BOUND('',#1637,.T.);
#1639=CARTESIAN_POINT('',(50.8,355.6,-127.));
#1640=DIRECTION('',(0.,0.,1.));
#1641=DIRECTION('',(1.,0.,0.));
#1642=AXIS2_PLACEMENT_3D('',#1639,#1640,#1641);
#1643=CIRCLE('',#1642,19.05);
#1644=CARTESIAN_POINT('',(69.85,355.6,-127.));
#1645=VERTEX_POINT('',#1644);
#1646=EDGE_CURVE('E3142',#1645,#1645,#1643,.T.);
#1647=ORIENTED_EDGE('',*,*,#1646,.T.);
#1648=EDGE_LOOP('',(#1647));
#1649=FACE_BOUND('',#1648,.T.);
#1650=DIRECTION('',(1.,0.,0.));
#1651=VECTOR('',#1650,1.);
#1652=CARTESIAN_POINT('',(-0.00100000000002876,317.5,-127.));
#1653=LINE('',#1652,#1651);
#1654=EDGE_CURVE('E1325',#1090,#93,#1653,.T.);
#1655=ORIENTED_EDGE('',*,*,#1654,.F.);
#1656=ORIENTED_EDGE('',*,*,#1091,.T.);
#1657=ORIENTED_EDGE('',*,*,#758,.T.);
#1658=ORIENTED_EDGE('',*,*,#98,.T.);
#1659=EDGE_LOOP('',(#1655,#1656,#1657,#1658));
#1660=FACE_BOUND('',#1659,.T.);
#1661=ADVANCED_FACE('F2129',(#1638,#1649,#1660),#662,.T.);
#1662=CARTESIAN_POINT('',(-0.00100000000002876,101.6,-76.2));
#1663=DIRECTION('',(0.,-1.,0.));
#1664=DIRECTION('',(0.,0.,-1.));
#1665=AXIS2_PLACEMENT_3D('',#1662,#1663,#1664);
#1666=PLANE('',#1665);
#1667=DIRECTION('',(1.,0.,0.));
#1668=VECTOR('',#1667,1.);
#1669=CARTESIAN_POINT('',(-0.00100000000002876,101.6,-76.2));
#1670=LINE('',#1669,#1668);
#1671=EDGE_CURVE('E1324',#1070,#77,#1670,.T.);
#1672=ORIENTED_EDGE('',*,*,#1671,.T.);
#1673=ORIENTED_EDGE('',*,*,#78,.T.);
#1674=ORIENTED_EDGE('',*,*,#691,.F.);
#1675=ORIENTED_EDGE('',*,*,#1071,.F.);
#1676=EDGE_LOOP('',(#1672,#1673,#1674,#1675));
#1677=FACE_BOUND('',#1676,.T.);
#1678=ADVANCED_FACE('F1303',(#1677),#1666,.F.);
#1679=CARTESIAN_POINT('',(-0.00100000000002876,317.5,-76.2));
#1680=DIRECTION('',(0.,0.,1.));
#1681=DIRECTION('',(1.,0.,0.));
#1682=AXIS2_PLACEMENT_3D('',#1679,#1680,#1681);
#1683=PLANE('',#1682);
#1684=CARTESIAN_POINT('',(285.75,198.175978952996,-76.2000000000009));
#1685=DIRECTION('',(0.,0.,1.));
#1686=DIRECTION('',(1.,0.,0.));
#1687=AXIS2_PLACEMENT_3D('',#1684,#1685,#1686);
#1688=CIRCLE('',#1687,5.18047705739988);
#1689=CARTESIAN_POINT('',(290.9304770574,198.175978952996,-76.2000000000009));
#1690=VERTEX_POINT('',#1689);
#1691=EDGE_CURVE('E3659',#1690,#1690,#1688,.T.);
#1692=ORIENTED_EDGE('',*,*,#1691,.T.);
#1693=EDGE_LOOP('',(#1692));
#1694=FACE_BOUND('',#1693,.T.);
#1695=CARTESIAN_POINT('',(228.6,260.35,-76.2));
#1696=DIRECTION('',(0.,0.,-1.));
#1697=DIRECTION('',(-1.,0.,0.));
#1698=AXIS2_PLACEMENT_3D('',#1695,#1696,#1697);
#1699=CIRCLE('',#1698,22.225);
#1700=CARTESIAN_POINT('',(206.375,260.35,-76.2));
#1701=VERTEX_POINT('',#1700);
#1702=EDGE_CURVE('E3202',#1701,#1701,#1699,.T.);
#1703=ORIENTED_EDGE('',*,*,#1702,.F.);
#1704=EDGE_LOOP('',(#1703));
#1705=FACE_BOUND('',#1704,.T.);
#1706=CARTESIAN_POINT('',(228.6,133.35,-76.2));
#1707=DIRECTION('',(0.,0.,-1.));
#1708=DIRECTION('',(-1.,0.,0.));
#1709=AXIS2_PLACEMENT_3D('',#1706,#1707,#1708);
#1710=CIRCLE('',#1709,22.225);
#1711=CARTESIAN_POINT('',(206.375,133.35,-76.2));
#1712=VERTEX_POINT('',#1711);
#1713=EDGE_CURVE('E3212',#1712,#1712,#1710,.T.);
#1714=ORIENTED_EDGE('',*,*,#1713,.F.);
#1715=EDGE_LOOP('',(#1714));
#1716=FACE_BOUND('',#1715,.T.);
#1717=CARTESIAN_POINT('',(381.,133.35,-76.2));
#1718=DIRECTION('',(0.,0.,-1.));
#1719=DIRECTION('',(-1.,0.,0.));
#1720=AXIS2_PLACEMENT_3D('',#1717,#1718,#1719);
#1721=CIRCLE('',#1720,22.225);
#1722=CARTESIAN_POINT('',(358.775,133.35,-76.2));
#1723=VERTEX_POINT('',#1722);
#1724=EDGE_CURVE('E3250',#1723,#1723,#1721,.T.);
#1725=ORIENTED_EDGE('',*,*,#1724,.F.);
#1726=EDGE_LOOP('',(#1725));
#1727=FACE_BOUND('',#1726,.T.);
#1728=CARTESIAN_POINT('',(381.,260.35,-76.2));
#1729=DIRECTION('',(0.,0.,-1.));
#1730=DIRECTION('',(-1.,0.,0.));
#1731=AXIS2_PLACEMENT_3D('',#1728,#1729,#1730);
#1732=CIRCLE('',#1731,22.225);
#1733=CARTESIAN_POINT('',(358.775,260.35,-76.2));
#1734=VERTEX_POINT('',#1733);
#1735=EDGE_CURVE('E3257',#1734,#1734,#1732,.T.);
#1736=ORIENTED_EDGE('',*,*,#1735,.F.);
#1737=EDGE_LOOP('',(#1736));
#1738=FACE_BOUND('',#1737,.T.);
#1739=CARTESIAN_POINT('',(533.4,203.2,-76.2));
#1740=DIRECTION('',(0.,0.,-1.));
#1741=DIRECTION('',(-1.,0.,0.));
#1742=AXIS2_PLACEMENT_3D('',#1739,#1740,#1741);
#1743=CIRCLE('',#1742,10.1461503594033);
#1744=CARTESIAN_POINT('',(523.253849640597,203.2,-76.2));
#1745=VERTEX_POINT('',#1744);
#1746=EDGE_CURVE('E1197',#1745,#1745,#1743,.T.);
#1747=ORIENTED_EDGE('',*,*,#1746,.F.);
#1748=EDGE_LOOP('',(#1747));
#1749=FACE_BOUND('',#1748,.T.);
#1750=CARTESIAN_POINT('',(533.4,266.7,-76.2));
#1751=DIRECTION('',(0.,0.,-1.));
#1752=DIRECTION('',(-1.,0.,0.));
#1753=AXIS2_PLACEMENT_3D('',#1750,#1751,#1752);
#1754=CIRCLE('',#1753,12.6861503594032);
#1755=CARTESIAN_POINT('',(520.713849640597,266.7,-76.2));
#1756=VERTEX_POINT('',#1755);
#1757=EDGE_CURVE('E3987',#1756,#1756,#1754,.T.);
#1758=ORIENTED_EDGE('',*,*,#1757,.F.);
#1759=EDGE_LOOP('',(#1758));
#1760=FACE_BOUND('',#1759,.T.);
#1761=CARTESIAN_POINT('',(533.4,139.7,-76.2));
#1762=DIRECTION('',(0.,0.,-1.));
#1763=DIRECTION('',(-1.,0.,0.));
#1764=AXIS2_PLACEMENT_3D('',#1761,#1762,#1763);
#1765=CIRCLE('',#1764,12.065);
#1766=CARTESIAN_POINT('',(521.335,139.7,-76.2));
#1767=VERTEX_POINT('',#1766);
#1768=EDGE_CURVE('E3990',#1767,#1767,#1765,.T.);
#1769=ORIENTED_EDGE('',*,*,#1768,.F.);
#1770=EDGE_LOOP('',(#1769));
#1771=FACE_BOUND('',#1770,.T.);
#1772=CARTESIAN_POINT('',(76.2,203.2,-76.2));
#1773=DIRECTION('',(0.,0.,-1.));
#1774=DIRECTION('',(-1.,0.,0.));
#1775=AXIS2_PLACEMENT_3D('',#1772,#1773,#1774);
#1776=CIRCLE('',#1775,9.52500000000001);
#1777=CARTESIAN_POINT('',(66.675,203.2,-76.2));
#1778=VERTEX_POINT('',#1777);
#1779=EDGE_CURVE('E1250',#1778,#1778,#1776,.T.);
#1780=ORIENTED_EDGE('',*,*,#1779,.F.);
#1781=EDGE_LOOP('',(#1780));
#1782=FACE_BOUND('',#1781,.T.);
#1783=CARTESIAN_POINT('',(76.2,266.7,-76.2));
#1784=DIRECTION('',(0.,0.,-1.));
#1785=DIRECTION('',(-1.,0.,0.));
#1786=AXIS2_PLACEMENT_3D('',#1783,#1784,#1785);
#1787=CIRCLE('',#1786,12.065);
#1788=CARTESIAN_POINT('',(64.135,266.7,-76.2));
#1789=VERTEX_POINT('',#1788);
#1790=EDGE_CURVE('E1249',#1789,#1789,#1787,.T.);
#1791=ORIENTED_EDGE('',*,*,#1790,.F.);
#1792=EDGE_LOOP('',(#1791));
#1793=FACE_BOUND('',#1792,.T.);
#1794=CARTESIAN_POINT('',(76.2,139.7,-76.2));
#1795=DIRECTION('',(0.,0.,-1.));
#1796=DIRECTION('',(-1.,0.,0.));
#1797=AXIS2_PLACEMENT_3D('',#1794,#1795,#1796);
#1798=CIRCLE('',#1797,12.065);
#1799=CARTESIAN_POINT('',(64.135,139.7,-76.2));
#1800=VERTEX_POINT('',#1799);
#1801=EDGE_CURVE('E1311',#1800,#1800,#1798,.T.);
#1802=ORIENTED_EDGE('',*,*,#1801,.F.);
#1803=EDGE_LOOP('',(#1802));
#1804=FACE_BOUND('',#1803,.T.);
#1805=DIRECTION('',(1.,0.,0.));
#1806=VECTOR('',#1805,1.);
#1807=CARTESIAN_POINT('',(-0.00100000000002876,317.5,-76.2));
#1808=LINE('',#1807,#1806);
#1809=EDGE_CURVE('E1314',#1098,#85,#1808,.T.);
#1810=ORIENTED_EDGE('',*,*,#1809,.T.);
#1811=ORIENTED_EDGE('',*,*,#86,.T.);
#1812=ORIENTED_EDGE('',*,*,#1671,.F.);
#1813=ORIENTED_EDGE('',*,*,#1105,.F.);
#1814=EDGE_LOOP('',(#1810,#1811,#1812,#1813));
#1815=FACE_BOUND('',#1814,.T.);
#1816=ADVANCED_FACE('F1299',(#1694,#1705,#1716,#1727,#1738,#1749,#1760,#1771,#1782,#1793,#1804,
#1815),#1683,.F.);
#1817=CARTESIAN_POINT('',(-0.00100000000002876,317.5,-127.));
#1818=DIRECTION('',(0.,1.,0.));
#1819=DIRECTION('',(0.,0.,1.));
#1820=AXIS2_PLACEMENT_3D('',#1817,#1818,#1819);
#1821=PLANE('',#1820);
#1822=ORIENTED_EDGE('',*,*,#1654,.T.);
#1823=ORIENTED_EDGE('',*,*,#94,.T.);
#1824=ORIENTED_EDGE('',*,*,#1809,.F.);
#1825=ORIENTED_EDGE('',*,*,#1099,.F.);
#1826=EDGE_LOOP('',(#1822,#1823,#1824,#1825));
#1827=FACE_BOUND('',#1826,.T.);
#1828=ADVANCED_FACE('F1302',(#1827),#1821,.F.);
#1829=CARTESIAN_POINT('',(50.8,355.6,0.));
#1830=DIRECTION('',(0.,0.,1.));
#1831=DIRECTION('',(1.,0.,0.));
#1832=AXIS2_PLACEMENT_3D('',#1829,#1830,#1831);
#1833=CYLINDRICAL_SURFACE('',#1832,19.05);
#1834=ORIENTED_EDGE('',*,*,#1646,.F.);
#1835=EDGE_LOOP('',(#1834));
#1836=FACE_BOUND('',#1835,.T.);
#1837=CARTESIAN_POINT('',(50.8,355.6,-25.4));
#1838=DIRECTION('',(0.,0.,1.));
#1839=DIRECTION('',(1.,0.,0.));
#1840=AXIS2_PLACEMENT_3D('',#1837,#1838,#1839);
#1841=CIRCLE('',#1840,19.05);
#1842=CARTESIAN_POINT('',(69.85,355.6,-25.4));
#1843=VERTEX_POINT('',#1842);
#1844=EDGE_CURVE('E3144',#1843,#1843,#1841,.T.);
#1845=ORIENTED_EDGE('',*,*,#1844,.T.);
#1846=EDGE_LOOP('',(#1845));
#1847=FACE_BOUND('',#1846,.T.);
#1848=ADVANCED_FACE('F2120',(#1836,#1847),#1833,.F.);
#1849=CARTESIAN_POINT('',(69.85,355.6,-25.4));
#1850=DIRECTION('',(0.,0.,-1.));
#1851=DIRECTION('',(-1.,0.,0.));
#1852=AXIS2_PLACEMENT_3D('',#1849,#1850,#1851);
#1853=PLANE('',#1852);
#1854=ORIENTED_EDGE('',*,*,#1844,.F.);
#1855=EDGE_LOOP('',(#1854));
#1856=FACE_BOUND('',#1855,.T.);
#1857=CARTESIAN_POINT('',(50.8,355.6,-25.4));
#1858=DIRECTION('',(0.,0.,1.));
#1859=DIRECTION('',(1.,0.,0.));
#1860=AXIS2_PLACEMENT_3D('',#1857,#1858,#1859);
#1861=CIRCLE('',#1860,28.575);
#1862=CARTESIAN_POINT('',(79.375,355.6,-25.4));
#1863=VERTEX_POINT('',#1862);
#1864=EDGE_CURVE('E3148',#1863,#1863,#1861,.T.);
#1865=ORIENTED_EDGE('',*,*,#1864,.T.);
#1866=EDGE_LOOP('',(#1865));
#1867=FACE_BOUND('',#1866,.T.);
#1868=ADVANCED_FACE('F2116',(#1856,#1867),#1853,.F.);
#1869=CARTESIAN_POINT('',(50.8,355.6,0.));
#1870=DIRECTION('',(0.,0.,1.));
#1871=DIRECTION('',(1.,0.,0.));
#1872=AXIS2_PLACEMENT_3D('',#1869,#1870,#1871);
#1873=CYLINDRICAL_SURFACE('',#1872,28.575);
#1874=ORIENTED_EDGE('',*,*,#1864,.F.);
#1875=EDGE_LOOP('',(#1874));
#1876=FACE_BOUND('',#1875,.T.);
#1877=ORIENTED_EDGE('',*,*,#1535,.T.);
#1878=EDGE_LOOP('',(#1877));
#1879=FACE_BOUND('',#1878,.T.);
#1880=ADVANCED_FACE('F2112',(#1876,#1879),#1873,.F.);
#1881=CARTESIAN_POINT('',(558.8,355.6,0.));
#1882=DIRECTION('',(0.,0.,1.));
#1883=DIRECTION('',(1.,0.,0.));
#1884=AXIS2_PLACEMENT_3D('',#1881,#1882,#1883);
#1885=CYLINDRICAL_SURFACE('',#1884,19.05);
#1886=ORIENTED_EDGE('',*,*,#1635,.F.);
#1887=EDGE_LOOP('',(#1886));
#1888=FACE_BOUND('',#1887,.T.);
#1889=CARTESIAN_POINT('',(558.8,355.6,-25.4));
#1890=DIRECTION('',(0.,0.,1.));
#1891=DIRECTION('',(1.,0.,0.));
#1892=AXIS2_PLACEMENT_3D('',#1889,#1890,#1891);
#1893=CIRCLE('',#1892,19.05);
#1894=CARTESIAN_POINT('',(577.85,355.6,-25.4));
#1895=VERTEX_POINT('',#1894);
#1896=EDGE_CURVE('E3182',#1895,#1895,#1893,.T.);
#1897=ORIENTED_EDGE('',*,*,#1896,.T.);
#1898=EDGE_LOOP('',(#1897));
#1899=FACE_BOUND('',#1898,.T.);
#1900=ADVANCED_FACE('F2108',(#1888,#1899),#1885,.F.);
#1901=CARTESIAN_POINT('',(577.85,355.6,-25.4));
#1902=DIRECTION('',(0.,0.,-1.));
#1903=DIRECTION('',(-1.,0.,0.));
#1904=AXIS2_PLACEMENT_3D('',#1901,#1902,#1903);
#1905=PLANE('',#1904);
#1906=ORIENTED_EDGE('',*,*,#1896,.F.);
#1907=EDGE_LOOP('',(#1906));
#1908=FACE_BOUND('',#1907,.T.);
#1909=CARTESIAN_POINT('',(558.8,355.6,-25.4));
#1910=DIRECTION('',(0.,0.,1.));
#1911=DIRECTION('',(1.,0.,0.));
#1912=AXIS2_PLACEMENT_3D('',#1909,#1910,#1911);
#1913=CIRCLE('',#1912,28.575);
#1914=CARTESIAN_POINT('',(587.375,355.6,-25.4));
#1915=VERTEX_POINT('',#1914);
#1916=EDGE_CURVE('E3178',#1915,#1915,#1913,.T.);
#1917=ORIENTED_EDGE('',*,*,#1916,.T.);
#1918=EDGE_LOOP('',(#1917));
#1919=FACE_BOUND('',#1918,.T.);
#1920=ADVANCED_FACE('F2104',(#1908,#1919),#1905,.F.);
#1921=CARTESIAN_POINT('',(558.8,355.6,0.));
#1922=DIRECTION('',(0.,0.,1.));
#1923=DIRECTION('',(1.,0.,0.));
#1924=AXIS2_PLACEMENT_3D('',#1921,#1922,#1923);
#1925=CYLINDRICAL_SURFACE('',#1924,28.575);
#1926=ORIENTED_EDGE('',*,*,#1916,.F.);
#1927=EDGE_LOOP('',(#1926));
#1928=FACE_BOUND('',#1927,.T.);
#1929=ORIENTED_EDGE('',*,*,#1524,.T.);
#1930=EDGE_LOOP('',(#1929));
#1931=FACE_BOUND('',#1930,.T.);
#1932=ADVANCED_FACE('F2100',(#1928,#1931),#1925,.F.);
#1933=CARTESIAN_POINT('',(50.8,50.8,0.));
#1934=DIRECTION('',(0.,0.,1.));
#1935=DIRECTION('',(1.,0.,0.));
#1936=AXIS2_PLACEMENT_3D('',#1933,#1934,#1935);
#1937=CYLINDRICAL_SURFACE('',#1936,19.05);
#1938=ORIENTED_EDGE('',*,*,#681,.F.);
#1939=EDGE_LOOP('',(#1938));
#1940=FACE_BOUND('',#1939,.T.);
#1941=CARTESIAN_POINT('',(50.8,50.8,-25.4));
#1942=DIRECTION('',(0.,0.,1.));
#1943=DIRECTION('',(1.,0.,0.));
#1944=AXIS2_PLACEMENT_3D('',#1941,#1942,#1943);
#1945=CIRCLE('',#1944,19.05);
#1946=CARTESIAN_POINT('',(69.85,50.8,-25.4));
#1947=VERTEX_POINT('',#1946);
#1948=EDGE_CURVE('E4055',#1947,#1947,#1945,.T.);
#1949=ORIENTED_EDGE('',*,*,#1948,.T.);
#1950=EDGE_LOOP('',(#1949));
#1951=FACE_BOUND('',#1950,.T.);
#1952=ADVANCED_FACE('F2096',(#1940,#1951),#1937,.F.);
#1953=CARTESIAN_POINT('',(69.85,50.8,-25.4));
#1954=DIRECTION('',(0.,0.,-1.));
#1955=DIRECTION('',(-1.,0.,0.));
#1956=AXIS2_PLACEMENT_3D('',#1953,#1954,#1955);
#1957=PLANE('',#1956);
#1958=ORIENTED_EDGE('',*,*,#1948,.F.);
#1959=EDGE_LOOP('',(#1958));
#1960=FACE_BOUND('',#1959,.T.);
#1961=CARTESIAN_POINT('',(50.8,50.8,-25.4));
#1962=DIRECTION('',(0.,0.,1.));
#1963=DIRECTION('',(1.,0.,0.));
#1964=AXIS2_PLACEMENT_3D('',#1961,#1962,#1963);
#1965=CIRCLE('',#1964,28.575);
#1966=CARTESIAN_POINT('',(79.375,50.8,-25.4));
#1967=VERTEX_POINT('',#1966);
#1968=EDGE_CURVE('E4060',#1967,#1967,#1965,.T.);
#1969=ORIENTED_EDGE('',*,*,#1968,.T.);
#1970=EDGE_LOOP('',(#1969));
#1971=FACE_BOUND('',#1970,.T.);
#1972=ADVANCED_FACE('F2092',(#1960,#1971),#1957,.F.);
#1973=CARTESIAN_POINT('',(50.8,50.8,0.));
#1974=DIRECTION('',(0.,0.,1.));
#1975=DIRECTION('',(1.,0.,0.));
#1976=AXIS2_PLACEMENT_3D('',#1973,#1974,#1975);
#1977=CYLINDRICAL_SURFACE('',#1976,28.575);
#1978=ORIENTED_EDGE('',*,*,#1968,.F.);
#1979=EDGE_LOOP('',(#1978));
#1980=FACE_BOUND('',#1979,.T.);
#1981=ORIENTED_EDGE('',*,*,#1513,.T.);
#1982=EDGE_LOOP('',(#1981));
#1983=FACE_BOUND('',#1982,.T.);
#1984=ADVANCED_FACE('F2088',(#1980,#1983),#1977,.F.);
#1985=CARTESIAN_POINT('',(558.8,50.8,0.));
#1986=DIRECTION('',(0.,0.,1.));
#1987=DIRECTION('',(1.,0.,0.));
#1988=AXIS2_PLACEMENT_3D('',#1985,#1986,#1987);
#1989=CYLINDRICAL_SURFACE('',#1988,19.05);
#1990=ORIENTED_EDGE('',*,*,#670,.F.);
#1991=EDGE_LOOP('',(#1990));
#1992=FACE_BOUND('',#1991,.T.);
#1993=CARTESIAN_POINT('',(558.8,50.8,-25.4));
#1994=DIRECTION('',(0.,0.,1.));
#1995=DIRECTION('',(1.,0.,0.));
#1996=AXIS2_PLACEMENT_3D('',#1993,#1994,#1995);
#1997=CIRCLE('',#1996,19.05);
#1998=CARTESIAN_POINT('',(577.85,50.8,-25.4));
#1999=VERTEX_POINT('',#1998);
#2000=EDGE_CURVE('E3165',#1999,#1999,#1997,.T.);
#2001=ORIENTED_EDGE('',*,*,#2000,.T.);
#2002=EDGE_LOOP('',(#2001));
#2003=FACE_BOUND('',#2002,.T.);
#2004=ADVANCED_FACE('F2084',(#1992,#2003),#1989,.F.);
#2005=CARTESIAN_POINT('',(577.85,50.8,-25.4));
#2006=DIRECTION('',(0.,0.,-1.));
#2007=DIRECTION('',(-1.,0.,0.));
#2008=AXIS2_PLACEMENT_3D('',#2005,#2006,#2007);
#2009=PLANE('',#2008);
#2010=ORIENTED_EDGE('',*,*,#2000,.F.);
#2011=EDGE_LOOP('',(#2010));
#2012=FACE_BOUND('',#2011,.T.);
#2013=CARTESIAN_POINT('',(558.8,50.8,-25.4));
#2014=DIRECTION('',(0.,0.,1.));
#2015=DIRECTION('',(1.,0.,0.));
#2016=AXIS2_PLACEMENT_3D('',#2013,#2014,#2015);
#2017=CIRCLE('',#2016,28.575);
#2018=CARTESIAN_POINT('',(587.375,50.8,-25.4));
#2019=VERTEX_POINT('',#2018);
#2020=EDGE_CURVE('E3161',#2019,#2019,#2017,.T.);
#2021=ORIENTED_EDGE('',*,*,#2020,.T.);
#2022=EDGE_LOOP('',(#2021));
#2023=FACE_BOUND('',#2022,.T.);
#2024=ADVANCED_FACE('F2080',(#2012,#2023),#2009,.F.);
#2025=CARTESIAN_POINT('',(558.8,50.8,0.));
#2026=DIRECTION('',(0.,0.,1.));
#2027=DIRECTION('',(1.,0.,0.));
#2028=AXIS2_PLACEMENT_3D('',#2025,#2026,#2027);
#2029=CYLINDRICAL_SURFACE('',#2028,28.575);
#2030=ORIENTED_EDGE('',*,*,#2020,.F.);
#2031=EDGE_LOOP('',(#2030));
#2032=FACE_BOUND('',#2031,.T.);
#2033=ORIENTED_EDGE('',*,*,#1502,.T.);
#2034=EDGE_LOOP('',(#2033));
#2035=FACE_BOUND('',#2034,.T.);
#2036=ADVANCED_FACE('F2076',(#2032,#2035),#2029,.F.);
#2037=CARTESIAN_POINT('',(50.8,304.8,-12.7));
#2038=DIRECTION('',(-1.,0.,0.));
#2039=DIRECTION('',(0.,-1.,0.));
#2040=AXIS2_PLACEMENT_3D('',#2037,#2038,#2039);
#2041=PLANE('',#2040);
#2042=DIRECTION('',(0.,-1.,0.));
#2043=VECTOR('',#2042,1.);
#2044=CARTESIAN_POINT('',(50.8,304.8,-12.7));
#2045=LINE('',#2044,#2043);
#2046=CARTESIAN_POINT('',(50.8,298.45,-12.7));
#2047=VERTEX_POINT('',#2046);
#2048=CARTESIAN_POINT('',(50.8,107.95,-12.7));
#2049=VERTEX_POINT('',#2048);
#2050=EDGE_CURVE('E1372',#2047,#2049,#2045,.T.);
#2051=ORIENTED_EDGE('',*,*,#2050,.F.);
#2052=DIRECTION('',(0.,0.,1.));
#2053=VECTOR('',#2052,1.);
#2054=CARTESIAN_POINT('',(50.8,298.45,-12.7));
#2055=LINE('',#2054,#2053);
#2056=EDGE_CURVE('E1399',#2047,#1449,#2055,.T.);
#2057=ORIENTED_EDGE('',*,*,#2056,.T.);
#2058=ORIENTED_EDGE('',*,*,#1450,.T.);
#2059=DIRECTION('',(0.,0.,1.));
#2060=VECTOR('',#2059,1.);
#2061=CARTESIAN_POINT('',(50.8,107.95,-12.7));
#2062=LINE('',#2061,#2060);
#2063=EDGE_CURVE('E1394',#1441,#2049,#2062,.F.);
#2064=ORIENTED_EDGE('',*,*,#2063,.T.);
#2065=EDGE_LOOP('',(#2051,#2057,#2058,#2064));
#2066=FACE_BOUND('',#2065,.T.);
#2067=ADVANCED_FACE('F2066',(#2066),#2041,.F.);
#2068=CARTESIAN_POINT('',(101.6,304.8,-12.7));
#2069=DIRECTION('',(0.,1.,0.));
#2070=DIRECTION('',(0.,0.,1.));
#2071=AXIS2_PLACEMENT_3D('',#2068,#2069,#2070);
#2072=PLANE('',#2071);
#2073=ORIENTED_EDGE('',*,*,#1467,.T.);
#2074=DIRECTION('',(0.,0.,1.));
#2075=VECTOR('',#2074,1.);
#2076=CARTESIAN_POINT('',(57.15,304.8,-12.7));
#2077=LINE('',#2076,#2075);
#2078=CARTESIAN_POINT('',(57.15,304.8,-12.7));
#2079=VERTEX_POINT('',#2078);
#2080=EDGE_CURVE('E4134',#1458,#2079,#2077,.F.);
#2081=ORIENTED_EDGE('',*,*,#2080,.T.);
#2082=DIRECTION('',(-1.,0.,0.));
#2083=VECTOR('',#2082,1.);
#2084=CARTESIAN_POINT('',(101.6,304.8,-12.7));
#2085=LINE('',#2084,#2083);
#2086=CARTESIAN_POINT('',(95.25,304.8,-12.7));
#2087=VERTEX_POINT('',#2086);
#2088=EDGE_CURVE('E1497',#2087,#2079,#2085,.T.);
#2089=ORIENTED_EDGE('',*,*,#2088,.F.);
#2090=DIRECTION('',(0.,0.,1.));
#2091=VECTOR('',#2090,1.);
#2092=CARTESIAN_POINT('',(95.25,304.8,-12.7));
#2093=LINE('',#2092,#2091);
#2094=EDGE_CURVE('E789',#2087,#1466,#2093,.T.);
#2095=ORIENTED_EDGE('',*,*,#2094,.T.);
#2096=EDGE_LOOP('',(#2073,#2081,#2089,#2095));
#2097=FACE_BOUND('',#2096,.T.);
#2098=ADVANCED_FACE('F2062',(#2097),#2072,.F.);
#2099=CARTESIAN_POINT('',(101.6,101.6,-12.7));
#2100=DIRECTION('',(1.,0.,0.));
#2101=DIRECTION('',(0.,1.,0.));
#2102=AXIS2_PLACEMENT_3D('',#2099,#2100,#2101);
#2103=PLANE('',#2102);
#2104=DIRECTION('',(0.,1.,0.));
#2105=VECTOR('',#2104,1.);
#2106=CARTESIAN_POINT('',(101.6,101.6,-12.7));
#2107=LINE('',#2106,#2105);
#2108=CARTESIAN_POINT('',(101.6,107.95,-12.7));
#2109=VERTEX_POINT('',#2108);
#2110=CARTESIAN_POINT('',(101.6,298.45,-12.7));
#2111=VERTEX_POINT('',#2110);
#2112=EDGE_CURVE('E1494',#2109,#2111,#2107,.T.);
#2113=ORIENTED_EDGE('',*,*,#2112,.F.);
#2114=DIRECTION('',(0.,0.,1.));
#2115=VECTOR('',#2114,1.);
#2116=CARTESIAN_POINT('',(101.6,107.95,-12.7));
#2117=LINE('',#2116,#2115);
#2118=EDGE_CURVE('E1478',#2109,#1483,#2117,.T.);
#2119=ORIENTED_EDGE('',*,*,#2118,.T.);
#2120=ORIENTED_EDGE('',*,*,#1484,.T.);
#2121=DIRECTION('',(0.,0.,1.));
#2122=VECTOR('',#2121,1.);
#2123=CARTESIAN_POINT('',(101.6,298.45,-12.7));
#2124=LINE('',#2123,#2122);
#2125=EDGE_CURVE('E3135',#1475,#2111,#2124,.F.);
#2126=ORIENTED_EDGE('',*,*,#2125,.T.);
#2127=EDGE_LOOP('',(#2113,#2119,#2120,#2126));
#2128=FACE_BOUND('',#2127,.T.);
#2129=ADVANCED_FACE('F2065',(#2128),#2103,.F.);
#2130=CARTESIAN_POINT('',(50.8,101.6,-12.7));
#2131=DIRECTION('',(0.,-1.,0.));
#2132=DIRECTION('',(1.,0.,0.));
#2133=AXIS2_PLACEMENT_3D('',#2130,#2131,#2132);
#2134=PLANE('',#2133);
#2135=DIRECTION('',(1.,0.,0.));
#2136=VECTOR('',#2135,1.);
#2137=CARTESIAN_POINT('',(50.8,101.6,-12.7));
#2138=LINE('',#2137,#2136);
#2139=CARTESIAN_POINT('',(57.15,101.6,-12.7));
#2140=VERTEX_POINT('',#2139);
#2141=CARTESIAN_POINT('',(95.25,101.6,-12.7));
#2142=VERTEX_POINT('',#2141);
#2143=EDGE_CURVE('E1378',#2140,#2142,#2138,.T.);
#2144=ORIENTED_EDGE('',*,*,#2143,.F.);
#2145=DIRECTION('',(0.,0.,1.));
#2146=VECTOR('',#2145,1.);
#2147=CARTESIAN_POINT('',(57.15,101.6,-12.7));
#2148=LINE('',#2147,#2146);
#2149=EDGE_CURVE('E4143',#2140,#1430,#2148,.T.);
#2150=ORIENTED_EDGE('',*,*,#2149,.T.);
#2151=ORIENTED_EDGE('',*,*,#1433,.T.);
#2152=DIRECTION('',(0.,0.,1.));
#2153=VECTOR('',#2152,1.);
#2154=CARTESIAN_POINT('',(95.25,101.6,-12.7));
#2155=LINE('',#2154,#2153);
#2156=EDGE_CURVE('E1483',#1432,#2142,#2155,.F.);
#2157=ORIENTED_EDGE('',*,*,#2156,.T.);
#2158=EDGE_LOOP('',(#2144,#2150,#2151,#2157));
#2159=FACE_BOUND('',#2158,.T.);
#2160=ADVANCED_FACE('F2060',(#2159),#2134,.F.);
#2161=CARTESIAN_POINT('',(50.8,101.6,-12.7));
#2162=DIRECTION('',(0.,0.,1.));
#2163=DIRECTION('',(1.,0.,0.));
#2164=AXIS2_PLACEMENT_3D('',#2161,#2162,#2163);
#2165=PLANE('',#2164);
#2166=CARTESIAN_POINT('',(76.2,203.2,-12.7));
#2167=DIRECTION('',(0.,0.,-1.));
#2168=DIRECTION('',(-1.,0.,0.));
#2169=AXIS2_PLACEMENT_3D('',#2166,#2167,#2168);
#2170=CIRCLE('',#2169,9.52500000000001);
#2171=CARTESIAN_POINT('',(66.675,203.2,-12.7));
#2172=VERTEX_POINT('',#2171);
#2173=EDGE_CURVE('E1245',#2172,#2172,#2170,.T.);
#2174=ORIENTED_EDGE('',*,*,#2173,.T.);
#2175=EDGE_LOOP('',(#2174));
#2176=FACE_BOUND('',#2175,.T.);
#2177=CARTESIAN_POINT('',(76.2,266.7,-12.7));
#2178=DIRECTION('',(0.,0.,1.));
#2179=DIRECTION('',(1.,0.,0.));
#2180=AXIS2_PLACEMENT_3D('',#2177,#2178,#2179);
#2181=CIRCLE('',#2180,12.065);
#2182=CARTESIAN_POINT('',(88.265,266.7,-12.7));
#2183=VERTEX_POINT('',#2182);
#2184=EDGE_CURVE('E4101',#2183,#2183,#2181,.T.);
#2185=ORIENTED_EDGE('',*,*,#2184,.F.);
#2186=EDGE_LOOP('',(#2185));
#2187=FACE_BOUND('',#2186,.T.);
#2188=CARTESIAN_POINT('',(76.2,139.7,-12.7));
#2189=DIRECTION('',(0.,0.,1.));
#2190=DIRECTION('',(1.,0.,0.));
#2191=AXIS2_PLACEMENT_3D('',#2188,#2189,#2190);
#2192=CIRCLE('',#2191,12.065);
#2193=CARTESIAN_POINT('',(88.265,139.7,-12.7));
#2194=VERTEX_POINT('',#2193);
#2195=EDGE_CURVE('E4105',#2194,#2194,#2192,.T.);
#2196=ORIENTED_EDGE('',*,*,#2195,.F.);
#2197=EDGE_LOOP('',(#2196));
#2198=FACE_BOUND('',#2197,.T.);
#2199=ORIENTED_EDGE('',*,*,#2088,.T.);
#2200=CARTESIAN_POINT('',(57.15,298.45,-12.7));
#2201=DIRECTION('',(0.,0.,1.));
#2202=DIRECTION('',(1.,0.,0.));
#2203=AXIS2_PLACEMENT_3D('',#2200,#2201,#2202);
#2204=CIRCLE('',#2203,6.35);
#2205=EDGE_CURVE('E1415',#2079,#2047,#2204,.T.);
#2206=ORIENTED_EDGE('',*,*,#2205,.T.);
#2207=ORIENTED_EDGE('',*,*,#2050,.T.);
#2208=CARTESIAN_POINT('',(57.15,107.95,-12.7));
#2209=DIRECTION('',(0.,0.,1.));
#2210=DIRECTION('',(1.,0.,0.));
#2211=AXIS2_PLACEMENT_3D('',#2208,#2209,#2210);
#2212=CIRCLE('',#2211,6.35);
#2213=EDGE_CURVE('E1389',#2049,#2140,#2212,.T.);
#2214=ORIENTED_EDGE('',*,*,#2213,.T.);
#2215=ORIENTED_EDGE('',*,*,#2143,.T.);
#2216=CARTESIAN_POINT('',(95.25,107.95,-12.7));
#2217=DIRECTION('',(0.,0.,1.));
#2218=DIRECTION('',(1.,0.,0.));
#2219=AXIS2_PLACEMENT_3D('',#2216,#2217,#2218);
#2220=CIRCLE('',#2219,6.35);
#2221=EDGE_CURVE('E1489',#2142,#2109,#2220,.T.);
#2222=ORIENTED_EDGE('',*,*,#2221,.T.);
#2223=ORIENTED_EDGE('',*,*,#2112,.T.);
#2224=CARTESIAN_POINT('',(95.25,298.45,-12.7));
#2225=DIRECTION('',(0.,0.,1.));
#2226=DIRECTION('',(1.,0.,0.));
#2227=AXIS2_PLACEMENT_3D('',#2224,#2225,#2226);
#2228=CIRCLE('',#2227,6.35);
#2229=EDGE_CURVE('E4130',#2111,#2087,#2228,.T.);
#2230=ORIENTED_EDGE('',*,*,#2229,.T.);
#2231=EDGE_LOOP('',(#2199,#2206,#2207,#2214,#2215,#2222,#2223,#2230));
#2232=FACE_BOUND('',#2231,.T.);
#2233=ADVANCED_FACE('F2056',(#2176,#2187,#2198,#2232),#2165,.T.);
#2234=CARTESIAN_POINT('',(76.2,139.7,-76.2));
#2235=DIRECTION('',(0.,0.,-1.));
#2236=DIRECTION('',(-1.,0.,0.));
#2237=AXIS2_PLACEMENT_3D('',#2234,#2235,#2236);
#2238=CONICAL_SURFACE('',#2237,12.065,0.78539816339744);
#2239=CARTESIAN_POINT('',(76.2,139.7,-73.66));
#2240=DIRECTION('',(0.,0.,-1.));
#2241=DIRECTION('',(-1.,0.,0.));
#2242=AXIS2_PLACEMENT_3D('',#2239,#2240,#2241);
#2243=CIRCLE('',#2242,9.52500000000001);
#2244=CARTESIAN_POINT('',(66.675,139.7,-73.66));
#2245=VERTEX_POINT('',#2244);
#2246=EDGE_CURVE('E4115',#2245,#2245,#2243,.T.);
#2247=ORIENTED_EDGE('',*,*,#2246,.F.);
#2248=EDGE_LOOP('',(#2247));
#2249=FACE_BOUND('',#2248,.T.);
#2250=ORIENTED_EDGE('',*,*,#1801,.T.);
#2251=EDGE_LOOP('',(#2250));
#2252=FACE_BOUND('',#2251,.T.);
#2253=ADVANCED_FACE('F2052',(#2249,#2252),#2238,.F.);
#2254=CARTESIAN_POINT('',(76.2,139.7,-15.24));
#2255=DIRECTION('',(0.,0.,-1.));
#2256=DIRECTION('',(-1.,0.,0.));
#2257=AXIS2_PLACEMENT_3D('',#2254,#2255,#2256);
#2258=CYLINDRICAL_SURFACE('',#2257,9.52500000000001);
#2259=CARTESIAN_POINT('',(76.2,139.7,-15.24));
#2260=DIRECTION('',(0.,0.,1.));
#2261=DIRECTION('',(1.,0.,0.));
#2262=AXIS2_PLACEMENT_3D('',#2259,#2260,#2261);
#2263=CIRCLE('',#2262,9.52500000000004);
#2264=CARTESIAN_POINT('',(85.7250000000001,139.7,-15.24));
#2265=VERTEX_POINT('',#2264);
#2266=EDGE_CURVE('E4111',#2265,#2265,#2263,.T.);
#2267=ORIENTED_EDGE('',*,*,#2266,.T.);
#2268=EDGE_LOOP('',(#2267));
#2269=FACE_BOUND('',#2268,.T.);
#2270=ORIENTED_EDGE('',*,*,#2246,.T.);
#2271=EDGE_LOOP('',(#2270));
#2272=FACE_BOUND('',#2271,.T.);
#2273=ADVANCED_FACE('F2048',(#2269,#2272),#2258,.F.);
#2274=CARTESIAN_POINT('',(76.2,139.7,-12.7));
#2275=DIRECTION('',(0.,0.,1.));
#2276=DIRECTION('',(1.,0.,0.));
#2277=AXIS2_PLACEMENT_3D('',#2274,#2275,#2276);
#2278=CONICAL_SURFACE('',#2277,12.065,0.78539816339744);
#2279=ORIENTED_EDGE('',*,*,#2266,.F.);
#2280=EDGE_LOOP('',(#2279));
#2281=FACE_BOUND('',#2280,.T.);
#2282=ORIENTED_EDGE('',*,*,#2195,.T.);
#2283=EDGE_LOOP('',(#2282));
#2284=FACE_BOUND('',#2283,.T.);
#2285=ADVANCED_FACE('F2044',(#2281,#2284),#2278,.F.);
#2286=CARTESIAN_POINT('',(76.2,266.7,-12.7));
#2287=DIRECTION('',(0.,0.,1.));
#2288=DIRECTION('',(1.,0.,0.));
#2289=AXIS2_PLACEMENT_3D('',#2286,#2287,#2288);
#2290=CONICAL_SURFACE('',#2289,12.065,0.78539816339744);
#2291=CARTESIAN_POINT('',(76.2,266.7,-15.24));
#2292=DIRECTION('',(0.,0.,1.));
#2293=DIRECTION('',(1.,0.,0.));
#2294=AXIS2_PLACEMENT_3D('',#2291,#2292,#2293);
#2295=CIRCLE('',#2294,9.52500000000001);
#2296=CARTESIAN_POINT('',(85.725,266.7,-15.24));
#2297=VERTEX_POINT('',#2296);
#2298=EDGE_CURVE('E4106',#2297,#2297,#2295,.T.);
#2299=ORIENTED_EDGE('',*,*,#2298,.F.);
#2300=EDGE_LOOP('',(#2299));
#2301=FACE_BOUND('',#2300,.T.);
#2302=ORIENTED_EDGE('',*,*,#2184,.T.);
#2303=EDGE_LOOP('',(#2302));
#2304=FACE_BOUND('',#2303,.T.);
#2305=ADVANCED_FACE('F2040',(#2301,#2304),#2290,.F.);
#2306=CARTESIAN_POINT('',(76.2,266.7,-73.66));
#2307=DIRECTION('',(0.,0.,1.));
#2308=DIRECTION('',(1.,0.,0.));
#2309=AXIS2_PLACEMENT_3D('',#2306,#2307,#2308);
#2310=CYLINDRICAL_SURFACE('',#2309,9.52500000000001);
#2311=CARTESIAN_POINT('',(76.2,266.7,-73.66));
#2312=DIRECTION('',(0.,0.,-1.));
#2313=DIRECTION('',(-1.,0.,0.));
#2314=AXIS2_PLACEMENT_3D('',#2311,#2312,#2313);
#2315=CIRCLE('',#2314,9.52500000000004);
#2316=CARTESIAN_POINT('',(66.675,266.7,-73.66));
#2317=VERTEX_POINT('',#2316);
#2318=EDGE_CURVE('E1256',#2317,#2317,#2315,.T.);
#2319=ORIENTED_EDGE('',*,*,#2318,.T.);
#2320=EDGE_LOOP('',(#2319));
#2321=FACE_BOUND('',#2320,.T.);
#2322=ORIENTED_EDGE('',*,*,#2298,.T.);
#2323=EDGE_LOOP('',(#2322));
#2324=FACE_BOUND('',#2323,.T.);
#2325=ADVANCED_FACE('F2036',(#2321,#2324),#2310,.F.);
#2326=CARTESIAN_POINT('',(76.2,266.7,-76.2));
#2327=DIRECTION('',(0.,0.,-1.));
#2328=DIRECTION('',(-1.,0.,0.));
#2329=AXIS2_PLACEMENT_3D('',#2326,#2327,#2328);
#2330=CONICAL_SURFACE('',#2329,12.065,0.78539816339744);
#2331=ORIENTED_EDGE('',*,*,#2318,.F.);
#2332=EDGE_LOOP('',(#2331));
#2333=FACE_BOUND('',#2332,.T.);
#2334=ORIENTED_EDGE('',*,*,#1790,.T.);
#2335=EDGE_LOOP('',(#2334));
#2336=FACE_BOUND('',#2335,.T.);
#2337=ADVANCED_FACE('F2032',(#2333,#2336),#2330,.F.);
#2338=CARTESIAN_POINT('',(76.2,203.2,-12.7));
#2339=DIRECTION('',(0.,0.,-1.));
#2340=DIRECTION('',(-1.,0.,0.));
#2341=AXIS2_PLACEMENT_3D('',#2338,#2339,#2340);
#2342=CYLINDRICAL_SURFACE('',#2341,9.52500000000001);
#2343=ORIENTED_EDGE('',*,*,#2173,.F.);
#2344=EDGE_LOOP('',(#2343));
#2345=FACE_BOUND('',#2344,.T.);
#2346=ORIENTED_EDGE('',*,*,#1779,.T.);
#2347=EDGE_LOOP('',(#2346));
#2348=FACE_BOUND('',#2347,.T.);
#2349=ADVANCED_FACE('F1297',(#2345,#2348),#2342,.F.);
#2350=CARTESIAN_POINT('',(508.,304.8,-12.7));
#2351=DIRECTION('',(-1.,0.,0.));
#2352=DIRECTION('',(0.,-1.,0.));
#2353=AXIS2_PLACEMENT_3D('',#2350,#2351,#2352);
#2354=PLANE('',#2353);
#2355=DIRECTION('',(0.,-1.,0.));
#2356=VECTOR('',#2355,1.);
#2357=CARTESIAN_POINT('',(508.,304.8,-12.7));
#2358=LINE('',#2357,#2356);
#2359=CARTESIAN_POINT('',(508.,298.45,-12.7));
#2360=VERTEX_POINT('',#2359);
#2361=CARTESIAN_POINT('',(508.,107.95,-12.7));
#2362=VERTEX_POINT('',#2361);
#2363=EDGE_CURVE('E1273',#2360,#2362,#2358,.T.);
#2364=ORIENTED_EDGE('',*,*,#2363,.F.);
#2365=DIRECTION('',(0.,0.,1.));
#2366=VECTOR('',#2365,1.);
#2367=CARTESIAN_POINT('',(508.,298.45,-12.7));
#2368=LINE('',#2367,#2366);
#2369=EDGE_CURVE('E1457',#2360,#1379,#2368,.T.);
#2370=ORIENTED_EDGE('',*,*,#2369,.T.);
#2371=ORIENTED_EDGE('',*,*,#1380,.T.);
#2372=DIRECTION('',(0.,0.,1.));
#2373=VECTOR('',#2372,1.);
#2374=CARTESIAN_POINT('',(508.,107.95,-12.7));
#2375=LINE('',#2374,#2373);
#2376=EDGE_CURVE('E4024',#1371,#2362,#2375,.F.);
#2377=ORIENTED_EDGE('',*,*,#2376,.T.);
#2378=EDGE_LOOP('',(#2364,#2370,#2371,#2377));
#2379=FACE_BOUND('',#2378,.T.);
#2380=ADVANCED_FACE('F2019',(#2379),#2354,.F.);
#2381=CARTESIAN_POINT('',(558.8,304.8,-12.7));
#2382=DIRECTION('',(0.,1.,0.));
#2383=DIRECTION('',(0.,0.,1.));
#2384=AXIS2_PLACEMENT_3D('',#2381,#2382,#2383);
#2385=PLANE('',#2384);
#2386=ORIENTED_EDGE('',*,*,#1397,.T.);
#2387=DIRECTION('',(0.,0.,1.));
#2388=VECTOR('',#2387,1.);
#2389=CARTESIAN_POINT('',(514.35,304.8,-12.7));
#2390=LINE('',#2389,#2388);
#2391=CARTESIAN_POINT('',(514.35,304.8,-12.7));
#2392=VERTEX_POINT('',#2391);
#2393=EDGE_CURVE('E1462',#1388,#2392,#2390,.F.);
#2394=ORIENTED_EDGE('',*,*,#2393,.T.);
#2395=DIRECTION('',(-1.,0.,0.));
#2396=VECTOR('',#2395,1.);
#2397=CARTESIAN_POINT('',(558.8,304.8,-12.7));
#2398=LINE('',#2397,#2396);
#2399=CARTESIAN_POINT('',(552.45,304.8,-12.7));
#2400=VERTEX_POINT('',#2399);
#2401=EDGE_CURVE('E1288',#2400,#2392,#2398,.T.);
#2402=ORIENTED_EDGE('',*,*,#2401,.F.);
#2403=DIRECTION('',(0.,0.,1.));
#2404=VECTOR('',#2403,1.);
#2405=CARTESIAN_POINT('',(552.45,304.8,-12.7));
#2406=LINE('',#2405,#2404);
#2407=EDGE_CURVE('E1414',#2400,#1396,#2406,.T.);
#2408=ORIENTED_EDGE('',*,*,#2407,.T.);
#2409=EDGE_LOOP('',(#2386,#2394,#2402,#2408));
#2410=FACE_BOUND('',#2409,.T.);
#2411=ADVANCED_FACE('F2015',(#2410),#2385,.F.);
#2412=CARTESIAN_POINT('',(558.8,101.6,-12.7));
#2413=DIRECTION('',(1.,0.,0.));
#2414=DIRECTION('',(0.,1.,0.));
#2415=AXIS2_PLACEMENT_3D('',#2412,#2413,#2414);
#2416=PLANE('',#2415);
#2417=DIRECTION('',(0.,1.,0.));
#2418=VECTOR('',#2417,1.);
#2419=CARTESIAN_POINT('',(558.8,101.6,-12.7));
#2420=LINE('',#2419,#2418);
#2421=CARTESIAN_POINT('',(558.8,107.95,-12.7));
#2422=VERTEX_POINT('',#2421);
#2423=CARTESIAN_POINT('',(558.8,298.45,-12.7));
#2424=VERTEX_POINT('',#2423);
#2425=EDGE_CURVE('E1286',#2422,#2424,#2420,.T.);
#2426=ORIENTED_EDGE('',*,*,#2425,.F.);
#2427=DIRECTION('',(0.,0.,1.));
#2428=VECTOR('',#2427,1.);
#2429=CARTESIAN_POINT('',(558.8,107.95,-12.7));
#2430=LINE('',#2429,#2428);
#2431=EDGE_CURVE('E1430',#2422,#1413,#2430,.T.);
#2432=ORIENTED_EDGE('',*,*,#2431,.T.);
#2433=ORIENTED_EDGE('',*,*,#1414,.T.);
#2434=DIRECTION('',(0.,0.,1.));
#2435=VECTOR('',#2434,1.);
#2436=CARTESIAN_POINT('',(558.8,298.45,-12.7));
#2437=LINE('',#2436,#2435);
#2438=EDGE_CURVE('E1420',#1405,#2424,#2437,.F.);
#2439=ORIENTED_EDGE('',*,*,#2438,.T.);
#2440=EDGE_LOOP('',(#2426,#2432,#2433,#2439));
#2441=FACE_BOUND('',#2440,.T.);
#2442=ADVANCED_FACE('F2018',(#2441),#2416,.F.);
#2443=CARTESIAN_POINT('',(508.,101.6,-12.7));
#2444=DIRECTION('',(0.,-1.,0.));
#2445=DIRECTION('',(1.,0.,0.));
#2446=AXIS2_PLACEMENT_3D('',#2443,#2444,#2445);
#2447=PLANE('',#2446);
#2448=DIRECTION('',(1.,0.,0.));
#2449=VECTOR('',#2448,1.);
#2450=CARTESIAN_POINT('',(508.,101.6,-12.7));
#2451=LINE('',#2450,#2449);
#2452=CARTESIAN_POINT('',(514.35,101.6,-12.7));
#2453=VERTEX_POINT('',#2452);
#2454=CARTESIAN_POINT('',(552.45,101.6,-12.7));
#2455=VERTEX_POINT('',#2454);
#2456=EDGE_CURVE('E1279',#2453,#2455,#2451,.T.);
#2457=ORIENTED_EDGE('',*,*,#2456,.F.);
#2458=DIRECTION('',(0.,0.,1.));
#2459=VECTOR('',#2458,1.);
#2460=CARTESIAN_POINT('',(514.35,101.6,-12.7));
#2461=LINE('',#2460,#2459);
#2462=EDGE_CURVE('E1445',#2453,#1360,#2461,.T.);
#2463=ORIENTED_EDGE('',*,*,#2462,.T.);
#2464=ORIENTED_EDGE('',*,*,#1363,.T.);
#2465=DIRECTION('',(0.,0.,1.));
#2466=VECTOR('',#2465,1.);
#2467=CARTESIAN_POINT('',(552.45,101.6,-12.7));
#2468=LINE('',#2467,#2466);
#2469=EDGE_CURVE('E1434',#1362,#2455,#2468,.F.);
#2470=ORIENTED_EDGE('',*,*,#2469,.T.);
#2471=EDGE_LOOP('',(#2457,#2463,#2464,#2470));
#2472=FACE_BOUND('',#2471,.T.);
#2473=ADVANCED_FACE('F2013',(#2472),#2447,.F.);
#2474=CARTESIAN_POINT('',(508.,304.8,-12.7));
#2475=DIRECTION('',(0.,0.,-1.));
#2476=DIRECTION('',(-1.,0.,0.));
#2477=AXIS2_PLACEMENT_3D('',#2474,#2475,#2476);
#2478=PLANE('',#2477);
#2479=CARTESIAN_POINT('',(533.4,203.2,-12.7));
#2480=DIRECTION('',(0.,0.,-1.));
#2481=DIRECTION('',(-1.,0.,0.));
#2482=AXIS2_PLACEMENT_3D('',#2479,#2480,#2481);
#2483=CIRCLE('',#2482,10.1461503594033);
#2484=CARTESIAN_POINT('',(523.253849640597,203.2,-12.7));
#2485=VERTEX_POINT('',#2484);
#2486=EDGE_CURVE('E1234',#2485,#2485,#2483,.T.);
#2487=ORIENTED_EDGE('',*,*,#2486,.T.);
#2488=EDGE_LOOP('',(#2487));
#2489=FACE_BOUND('',#2488,.T.);
#2490=CARTESIAN_POINT('',(533.4,266.7,-12.7));
#2491=DIRECTION('',(0.,0.,1.));
#2492=DIRECTION('',(1.,0.,0.));
#2493=AXIS2_PLACEMENT_3D('',#2490,#2491,#2492);
#2494=CIRCLE('',#2493,12.6861503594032);
#2495=CARTESIAN_POINT('',(546.086150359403,266.7,-12.7));
#2496=VERTEX_POINT('',#2495);
#2497=EDGE_CURVE('E4174',#2496,#2496,#2494,.T.);
#2498=ORIENTED_EDGE('',*,*,#2497,.F.);
#2499=EDGE_LOOP('',(#2498));
#2500=FACE_BOUND('',#2499,.T.);
#2501=CARTESIAN_POINT('',(533.4,139.7,-12.7));
#2502=DIRECTION('',(0.,0.,1.));
#2503=DIRECTION('',(1.,0.,0.));
#2504=AXIS2_PLACEMENT_3D('',#2501,#2502,#2503);
#2505=CIRCLE('',#2504,12.065);
#2506=CARTESIAN_POINT('',(545.465,139.7,-12.7));
#2507=VERTEX_POINT('',#2506);
#2508=EDGE_CURVE('E4089',#2507,#2507,#2505,.T.);
#2509=ORIENTED_EDGE('',*,*,#2508,.F.);
#2510=EDGE_LOOP('',(#2509));
#2511=FACE_BOUND('',#2510,.T.);
#2512=ORIENTED_EDGE('',*,*,#2401,.T.);
#2513=CARTESIAN_POINT('',(514.35,298.45,-12.7));
#2514=DIRECTION('',(0.,0.,-1.));
#2515=DIRECTION('',(-1.,0.,0.));
#2516=AXIS2_PLACEMENT_3D('',#2513,#2514,#2515);
#2517=CIRCLE('',#2516,6.35);
#2518=EDGE_CURVE('E4017',#2392,#2360,#2517,.F.);
#2519=ORIENTED_EDGE('',*,*,#2518,.T.);
#2520=ORIENTED_EDGE('',*,*,#2363,.T.);
#2521=CARTESIAN_POINT('',(514.35,107.95,-12.7));
#2522=DIRECTION('',(0.,0.,-1.));
#2523=DIRECTION('',(-1.,0.,0.));
#2524=AXIS2_PLACEMENT_3D('',#2521,#2522,#2523);
#2525=CIRCLE('',#2524,6.35);
#2526=EDGE_CURVE('E1458',#2362,#2453,#2525,.F.);
#2527=ORIENTED_EDGE('',*,*,#2526,.T.);
#2528=ORIENTED_EDGE('',*,*,#2456,.T.);
#2529=CARTESIAN_POINT('',(552.45,107.95,-12.7));
#2530=DIRECTION('',(0.,0.,-1.));
#2531=DIRECTION('',(-1.,0.,0.));
#2532=AXIS2_PLACEMENT_3D('',#2529,#2530,#2531);
#2533=CIRCLE('',#2532,6.35);
#2534=EDGE_CURVE('E1439',#2455,#2422,#2533,.F.);
#2535=ORIENTED_EDGE('',*,*,#2534,.T.);
#2536=ORIENTED_EDGE('',*,*,#2425,.T.);
#2537=CARTESIAN_POINT('',(552.45,298.45,-12.7));
#2538=DIRECTION('',(0.,0.,-1.));
#2539=DIRECTION('',(-1.,0.,0.));
#2540=AXIS2_PLACEMENT_3D('',#2537,#2538,#2539);
#2541=CIRCLE('',#2540,6.35);
#2542=EDGE_CURVE('E4015',#2424,#2400,#2541,.F.);
#2543=ORIENTED_EDGE('',*,*,#2542,.T.);
#2544=EDGE_LOOP('',(#2512,#2519,#2520,#2527,#2528,#2535,#2536,#2543));
#2545=FACE_BOUND('',#2544,.T.);
#2546=ADVANCED_FACE('F2009',(#2489,#2500,#2511,#2545),#2478,.F.);
#2547=CARTESIAN_POINT('',(533.4,139.7,-76.2));
#2548=DIRECTION('',(0.,0.,-1.));
#2549=DIRECTION('',(-1.,0.,0.));
#2550=AXIS2_PLACEMENT_3D('',#2547,#2548,#2549);
#2551=CONICAL_SURFACE('',#2550,12.065,0.785398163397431);
#2552=CARTESIAN_POINT('',(533.4,139.7,-73.66));
#2553=DIRECTION('',(0.,0.,-1.));
#2554=DIRECTION('',(-1.,0.,0.));
#2555=AXIS2_PLACEMENT_3D('',#2552,#2553,#2554);
#2556=CIRCLE('',#2555,9.52500000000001);
#2557=CARTESIAN_POINT('',(523.875,139.7,-73.66));
#2558=VERTEX_POINT('',#2557);
#2559=EDGE_CURVE('E3993',#2558,#2558,#2556,.T.);
#2560=ORIENTED_EDGE('',*,*,#2559,.F.);
#2561=EDGE_LOOP('',(#2560));
#2562=FACE_BOUND('',#2561,.T.);
#2563=ORIENTED_EDGE('',*,*,#1768,.T.);
#2564=EDGE_LOOP('',(#2563));
#2565=FACE_BOUND('',#2564,.T.);
#2566=ADVANCED_FACE('F2005',(#2562,#2565),#2551,.F.);
#2567=CARTESIAN_POINT('',(533.4,139.7,-15.24));
#2568=DIRECTION('',(0.,0.,-1.));
#2569=DIRECTION('',(-1.,0.,0.));
#2570=AXIS2_PLACEMENT_3D('',#2567,#2568,#2569);
#2571=CYLINDRICAL_SURFACE('',#2570,9.52500000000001);
#2572=CARTESIAN_POINT('',(533.4,139.7,-15.24));
#2573=DIRECTION('',(0.,0.,1.));
#2574=DIRECTION('',(1.,0.,0.));
#2575=AXIS2_PLACEMENT_3D('',#2572,#2573,#2574);
#2576=CIRCLE('',#2575,9.52500000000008);
#2577=CARTESIAN_POINT('',(542.925,139.7,-15.24));
#2578=VERTEX_POINT('',#2577);
#2579=EDGE_CURVE('E3996',#2578,#2578,#2576,.T.);
#2580=ORIENTED_EDGE('',*,*,#2579,.T.);
#2581=EDGE_LOOP('',(#2580));
#2582=FACE_BOUND('',#2581,.T.);
#2583=ORIENTED_EDGE('',*,*,#2559,.T.);
#2584=EDGE_LOOP('',(#2583));
#2585=FACE_BOUND('',#2584,.T.);
#2586=ADVANCED_FACE('F2001',(#2582,#2585),#2571,.F.);
#2587=CARTESIAN_POINT('',(533.4,139.7,-12.7));
#2588=DIRECTION('',(0.,0.,1.));
#2589=DIRECTION('',(1.,0.,0.));
#2590=AXIS2_PLACEMENT_3D('',#2587,#2588,#2589);
#2591=CONICAL_SURFACE('',#2590,12.065,0.785398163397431);
#2592=ORIENTED_EDGE('',*,*,#2579,.F.);
#2593=EDGE_LOOP('',(#2592));
#2594=FACE_BOUND('',#2593,.T.);
#2595=ORIENTED_EDGE('',*,*,#2508,.T.);
#2596=EDGE_LOOP('',(#2595));
#2597=FACE_BOUND('',#2596,.T.);
#2598=ADVANCED_FACE('F1997',(#2594,#2597),#2591,.F.);
#2599=CARTESIAN_POINT('',(533.4,266.7,-76.2));
#2600=DIRECTION('',(0.,0.,-1.));
#2601=DIRECTION('',(-1.,0.,0.));
#2602=AXIS2_PLACEMENT_3D('',#2599,#2600,#2601);
#2603=CONICAL_SURFACE('',#2602,12.6861503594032,0.785398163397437);
#2604=CARTESIAN_POINT('',(533.4,266.7,-73.66));
#2605=DIRECTION('',(0.,0.,-1.));
#2606=DIRECTION('',(-1.,0.,0.));
#2607=AXIS2_PLACEMENT_3D('',#2604,#2605,#2606);
#2608=CIRCLE('',#2607,10.1461503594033);
#2609=CARTESIAN_POINT('',(523.253849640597,266.7,-73.66));
#2610=VERTEX_POINT('',#2609);
#2611=EDGE_CURVE('E4080',#2610,#2610,#2608,.T.);
#2612=ORIENTED_EDGE('',*,*,#2611,.F.);
#2613=EDGE_LOOP('',(#2612));
#2614=FACE_BOUND('',#2613,.T.);
#2615=ORIENTED_EDGE('',*,*,#1757,.T.);
#2616=EDGE_LOOP('',(#2615));
#2617=FACE_BOUND('',#2616,.T.);
#2618=ADVANCED_FACE('F1993',(#2614,#2617),#2603,.F.);
#2619=CARTESIAN_POINT('',(533.4,266.7,-15.24));
#2620=DIRECTION('',(0.,0.,-1.));
#2621=DIRECTION('',(-1.,0.,0.));
#2622=AXIS2_PLACEMENT_3D('',#2619,#2620,#2621);
#2623=CYLINDRICAL_SURFACE('',#2622,10.1461503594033);
#2624=CARTESIAN_POINT('',(533.4,266.7,-15.24));
#2625=DIRECTION('',(0.,0.,1.));
#2626=DIRECTION('',(1.,0.,0.));
#2627=AXIS2_PLACEMENT_3D('',#2624,#2625,#2626);
#2628=CIRCLE('',#2627,10.1461503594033);
#2629=CARTESIAN_POINT('',(543.546150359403,266.7,-15.24));
#2630=VERTEX_POINT('',#2629);
#2631=EDGE_CURVE('E4085',#2630,#2630,#2628,.T.);
#2632=ORIENTED_EDGE('',*,*,#2631,.T.);
#2633=EDGE_LOOP('',(#2632));
#2634=FACE_BOUND('',#2633,.T.);
#2635=ORIENTED_EDGE('',*,*,#2611,.T.);
#2636=EDGE_LOOP('',(#2635));
#2637=FACE_BOUND('',#2636,.T.);
#2638=ADVANCED_FACE('F1989',(#2634,#2637),#2623,.F.);
#2639=CARTESIAN_POINT('',(533.4,266.7,-12.7));
#2640=DIRECTION('',(0.,0.,1.));
#2641=DIRECTION('',(1.,0.,0.));
#2642=AXIS2_PLACEMENT_3D('',#2639,#2640,#2641);
#2643=CONICAL_SURFACE('',#2642,12.6861503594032,0.785398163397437);
#2644=ORIENTED_EDGE('',*,*,#2631,.F.);
#2645=EDGE_LOOP('',(#2644));
#2646=FACE_BOUND('',#2645,.T.);
#2647=ORIENTED_EDGE('',*,*,#2497,.T.);
#2648=EDGE_LOOP('',(#2647));
#2649=FACE_BOUND('',#2648,.T.);
#2650=ADVANCED_FACE('F1985',(#2646,#2649),#2643,.F.);
#2651=CARTESIAN_POINT('',(533.4,203.2,-12.7));
#2652=DIRECTION('',(0.,0.,-1.));
#2653=DIRECTION('',(-1.,0.,0.));
#2654=AXIS2_PLACEMENT_3D('',#2651,#2652,#2653);
#2655=CYLINDRICAL_SURFACE('',#2654,10.1461503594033);
#2656=ORIENTED_EDGE('',*,*,#2486,.F.);
#2657=EDGE_LOOP('',(#2656));
#2658=FACE_BOUND('',#2657,.T.);
#2659=ORIENTED_EDGE('',*,*,#1746,.T.);
#2660=EDGE_LOOP('',(#2659));
#2661=FACE_BOUND('',#2660,.T.);
#2662=ADVANCED_FACE('F1981',(#2658,#2661),#2655,.F.);
#2663=CARTESIAN_POINT('',(152.4,95.25,-25.4));
#2664=DIRECTION('',(0.,0.,1.));
#2665=DIRECTION('',(1.,0.,0.));
#2666=AXIS2_PLACEMENT_3D('',#2663,#2664,#2665);
#2667=CYLINDRICAL_SURFACE('',#2666,12.7);
#2668=ORIENTED_EDGE('',*,*,#1302,.T.);
#2669=DIRECTION('',(0.,0.,1.));
#2670=VECTOR('',#2669,1.);
#2671=CARTESIAN_POINT('',(165.1,95.25,-25.4));
#2672=LINE('',#2671,#2670);
#2673=EDGE_CURVE('E1190',#573,#1290,#2672,.T.);
#2674=ORIENTED_EDGE('',*,*,#2673,.F.);
#2675=ORIENTED_EDGE('',*,*,#574,.F.);
#2676=DIRECTION('',(0.,0.,1.));
#2677=VECTOR('',#2676,1.);
#2678=CARTESIAN_POINT('',(152.4,107.95,-25.4));
#2679=LINE('',#2678,#2677);
#2680=EDGE_CURVE('E1194',#571,#1301,#2679,.T.);
#2681=ORIENTED_EDGE('',*,*,#2680,.T.);
#2682=EDGE_LOOP('',(#2668,#2674,#2675,#2681));
#2683=FACE_BOUND('',#2682,.T.);
#2684=ADVANCED_FACE('F1955',(#2683),#2667,.F.);
#2685=CARTESIAN_POINT('',(152.4,298.45,-25.4));
#2686=DIRECTION('',(-1.,0.,0.));
#2687=DIRECTION('',(0.,0.,1.));
#2688=AXIS2_PLACEMENT_3D('',#2685,#2686,#2687);
#2689=PLANE('',#2688);
#2690=ORIENTED_EDGE('',*,*,#1310,.T.);
#2691=ORIENTED_EDGE('',*,*,#2680,.F.);
#2692=ORIENTED_EDGE('',*,*,#631,.F.);
#2693=DIRECTION('',(0.,0.,1.));
#2694=VECTOR('',#2693,1.);
#2695=CARTESIAN_POINT('',(152.4,298.45,-25.4));
#2696=LINE('',#2695,#2694);
#2697=EDGE_CURVE('E1198',#624,#1309,#2696,.T.);
#2698=ORIENTED_EDGE('',*,*,#2697,.T.);
#2699=EDGE_LOOP('',(#2690,#2691,#2692,#2698));
#2700=FACE_BOUND('',#2699,.T.);
#2701=ADVANCED_FACE('F1951',(#2700),#2689,.F.);
#2702=CARTESIAN_POINT('',(152.4,311.15,-25.4));
#2703=DIRECTION('',(0.,0.,1.));
#2704=DIRECTION('',(1.,0.,0.));
#2705=AXIS2_PLACEMENT_3D('',#2702,#2703,#2704);
#2706=CYLINDRICAL_SURFACE('',#2705,12.7);
#2707=ORIENTED_EDGE('',*,*,#1319,.T.);
#2708=ORIENTED_EDGE('',*,*,#2697,.F.);
#2709=ORIENTED_EDGE('',*,*,#625,.F.);
#2710=DIRECTION('',(0.,0.,1.));
#2711=VECTOR('',#2710,1.);
#2712=CARTESIAN_POINT('',(165.1,311.15,-25.4));
#2713=LINE('',#2712,#2711);
#2714=EDGE_CURVE('E1210',#615,#1318,#2713,.T.);
#2715=ORIENTED_EDGE('',*,*,#2714,.T.);
#2716=EDGE_LOOP('',(#2707,#2708,#2709,#2715));
#2717=FACE_BOUND('',#2716,.T.);
#2718=ADVANCED_FACE('F1954',(#2717),#2706,.F.);
#2719=CARTESIAN_POINT('',(444.5,311.15,-25.4));
#2720=DIRECTION('',(0.,1.,0.));
#2721=DIRECTION('',(0.,0.,1.));
#2722=AXIS2_PLACEMENT_3D('',#2719,#2720,#2721);
#2723=PLANE('',#2722);
#2724=ORIENTED_EDGE('',*,*,#1327,.T.);
#2725=ORIENTED_EDGE('',*,*,#2714,.F.);
#2726=ORIENTED_EDGE('',*,*,#616,.F.);
#2727=DIRECTION('',(0.,0.,1.));
#2728=VECTOR('',#2727,1.);
#2729=CARTESIAN_POINT('',(444.5,311.15,-25.4));
#2730=LINE('',#2729,#2728);
#2731=EDGE_CURVE('E1212',#607,#1326,#2730,.T.);
#2732=ORIENTED_EDGE('',*,*,#2731,.T.);
#2733=EDGE_LOOP('',(#2724,#2725,#2726,#2732));
#2734=FACE_BOUND('',#2733,.T.);
#2735=ADVANCED_FACE('F1959',(#2734),#2723,.F.);
#2736=CARTESIAN_POINT('',(457.2,311.15,-25.4));
#2737=DIRECTION('',(0.,0.,1.));
#2738=DIRECTION('',(1.,0.,0.));
#2739=AXIS2_PLACEMENT_3D('',#2736,#2737,#2738);
#2740=CYLINDRICAL_SURFACE('',#2739,12.7);
#2741=ORIENTED_EDGE('',*,*,#1336,.T.);
#2742=ORIENTED_EDGE('',*,*,#2731,.F.);
#2743=ORIENTED_EDGE('',*,*,#608,.F.);
#2744=DIRECTION('',(0.,0.,1.));
#2745=VECTOR('',#2744,1.);
#2746=CARTESIAN_POINT('',(457.2,298.45,-25.4));
#2747=LINE('',#2746,#2745);
#2748=EDGE_CURVE('E1215',#598,#1335,#2747,.T.);
#2749=ORIENTED_EDGE('',*,*,#2748,.T.);
#2750=EDGE_LOOP('',(#2741,#2742,#2743,#2749));
#2751=FACE_BOUND('',#2750,.T.);
#2752=ADVANCED_FACE('F1963',(#2751),#2740,.F.);
#2753=CARTESIAN_POINT('',(457.2,107.95,-25.4));
#2754=DIRECTION('',(1.,0.,0.));
#2755=DIRECTION('',(0.,0.,-1.));
#2756=AXIS2_PLACEMENT_3D('',#2753,#2754,#2755);
#2757=PLANE('',#2756);
#2758=ORIENTED_EDGE('',*,*,#1344,.T.);
#2759=ORIENTED_EDGE('',*,*,#2748,.F.);
#2760=ORIENTED_EDGE('',*,*,#599,.F.);
#2761=DIRECTION('',(0.,0.,1.));
#2762=VECTOR('',#2761,1.);
#2763=CARTESIAN_POINT('',(457.2,107.95,-25.4));
#2764=LINE('',#2763,#2762);
#2765=EDGE_CURVE('E1218',#590,#1343,#2764,.T.);
#2766=ORIENTED_EDGE('',*,*,#2765,.T.);
#2767=EDGE_LOOP('',(#2758,#2759,#2760,#2766));
#2768=FACE_BOUND('',#2767,.T.);
#2769=ADVANCED_FACE('F1967',(#2768),#2757,.F.);
#2770=CARTESIAN_POINT('',(457.2,95.25,-25.4));
#2771=DIRECTION('',(0.,0.,1.));
#2772=DIRECTION('',(1.,0.,0.));
#2773=AXIS2_PLACEMENT_3D('',#2770,#2771,#2772);
#2774=CYLINDRICAL_SURFACE('',#2773,12.7);
#2775=ORIENTED_EDGE('',*,*,#1351,.T.);
#2776=ORIENTED_EDGE('',*,*,#2765,.F.);
#2777=ORIENTED_EDGE('',*,*,#591,.F.);
#2778=DIRECTION('',(0.,0.,1.));
#2779=VECTOR('',#2778,1.);
#2780=CARTESIAN_POINT('',(444.5,95.25,-25.4));
#2781=LINE('',#2780,#2779);
#2782=EDGE_CURVE('E1226',#581,#1292,#2781,.T.);
#2783=ORIENTED_EDGE('',*,*,#2782,.T.);
#2784=EDGE_LOOP('',(#2775,#2776,#2777,#2783));
#2785=FACE_BOUND('',#2784,.T.);
#2786=ADVANCED_FACE('F1971',(#2785),#2774,.F.);
#2787=CARTESIAN_POINT('',(165.1,95.25,-25.4));
#2788=DIRECTION('',(0.,-1.,0.));
#2789=DIRECTION('',(0.,0.,-1.));
#2790=AXIS2_PLACEMENT_3D('',#2787,#2788,#2789);
#2791=PLANE('',#2790);
#2792=ORIENTED_EDGE('',*,*,#1293,.T.);
#2793=ORIENTED_EDGE('',*,*,#2782,.F.);
#2794=ORIENTED_EDGE('',*,*,#582,.F.);
#2795=ORIENTED_EDGE('',*,*,#2673,.T.);
#2796=EDGE_LOOP('',(#2792,#2793,#2794,#2795));
#2797=FACE_BOUND('',#2796,.T.);
#2798=ADVANCED_FACE('F1945',(#2797),#2791,.F.);
#2799=CARTESIAN_POINT('',(381.,260.35,-76.2));
#2800=DIRECTION('',(0.,0.,-1.));
#2801=DIRECTION('',(-1.,0.,0.));
#2802=AXIS2_PLACEMENT_3D('',#2799,#2800,#2801);
#2803=CYLINDRICAL_SURFACE('',#2802,22.225);
#2804=CARTESIAN_POINT('',(381.,260.35,-63.5));
#2805=DIRECTION('',(0.,0.,-1.));
#2806=DIRECTION('',(-1.,0.,0.));
#2807=AXIS2_PLACEMENT_3D('',#2804,#2805,#2806);
#2808=CIRCLE('',#2807,22.225);
#2809=CARTESIAN_POINT('',(358.775,260.35,-63.5));
#2810=VERTEX_POINT('',#2809);
#2811=EDGE_CURVE('E3262',#2810,#2810,#2808,.T.);
#2812=ORIENTED_EDGE('',*,*,#2811,.F.);
#2813=EDGE_LOOP('',(#2812));
#2814=FACE_BOUND('',#2813,.T.);
#2815=ORIENTED_EDGE('',*,*,#1735,.T.);
#2816=EDGE_LOOP('',(#2815));
#2817=FACE_BOUND('',#2816,.T.);
#2818=ADVANCED_FACE('F1941',(#2814,#2817),#2803,.F.);
#2819=CARTESIAN_POINT('',(390.525,260.35,-63.5));
#2820=DIRECTION('',(0.,0.,1.));
#2821=DIRECTION('',(1.,0.,0.));
#2822=AXIS2_PLACEMENT_3D('',#2819,#2820,#2821);
#2823=PLANE('',#2822);
#2824=CARTESIAN_POINT('',(381.,260.35,-63.5));
#2825=DIRECTION('',(0.,0.,-1.));
#2826=DIRECTION('',(-1.,0.,0.));
#2827=AXIS2_PLACEMENT_3D('',#2824,#2825,#2826);
#2828=CIRCLE('',#2827,9.52500000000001);
#2829=CARTESIAN_POINT('',(371.475,260.35,-63.5));
#2830=VERTEX_POINT('',#2829);
#2831=EDGE_CURVE('E3970',#2830,#2830,#2828,.T.);
#2832=ORIENTED_EDGE('',*,*,#2831,.F.);
#2833=EDGE_LOOP('',(#2832));
#2834=FACE_BOUND('',#2833,.T.);
#2835=ORIENTED_EDGE('',*,*,#2811,.T.);
#2836=EDGE_LOOP('',(#2835));
#2837=FACE_BOUND('',#2836,.T.);
#2838=ADVANCED_FACE('F1937',(#2834,#2837),#2823,.F.);
#2839=CARTESIAN_POINT('',(381.,260.35,-76.2));
#2840=DIRECTION('',(0.,0.,-1.));
#2841=DIRECTION('',(-1.,0.,0.));
#2842=AXIS2_PLACEMENT_3D('',#2839,#2840,#2841);
#2843=CYLINDRICAL_SURFACE('',#2842,9.52500000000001);
#2844=ORIENTED_EDGE('',*,*,#561,.F.);
#2845=EDGE_LOOP('',(#2844));
#2846=FACE_BOUND('',#2845,.T.);
#2847=ORIENTED_EDGE('',*,*,#2831,.T.);
#2848=EDGE_LOOP('',(#2847));
#2849=FACE_BOUND('',#2848,.T.);
#2850=ADVANCED_FACE('F1933',(#2846,#2849),#2843,.F.);
#2851=CARTESIAN_POINT('',(381.,133.35,-76.2));
#2852=DIRECTION('',(0.,0.,-1.));
#2853=DIRECTION('',(-1.,0.,0.));
#2854=AXIS2_PLACEMENT_3D('',#2851,#2852,#2853);
#2855=CYLINDRICAL_SURFACE('',#2854,22.225);
#2856=CARTESIAN_POINT('',(381.,133.35,-63.5));
#2857=DIRECTION('',(0.,0.,-1.));
#2858=DIRECTION('',(-1.,0.,0.));
#2859=AXIS2_PLACEMENT_3D('',#2856,#2857,#2858);
#2860=CIRCLE('',#2859,22.225);
#2861=CARTESIAN_POINT('',(358.775,133.35,-63.5));
#2862=VERTEX_POINT('',#2861);
#2863=EDGE_CURVE('E3247',#2862,#2862,#2860,.T.);
#2864=ORIENTED_EDGE('',*,*,#2863,.F.);
#2865=EDGE_LOOP('',(#2864));
#2866=FACE_BOUND('',#2865,.T.);
#2867=ORIENTED_EDGE('',*,*,#1724,.T.);
#2868=EDGE_LOOP('',(#2867));
#2869=FACE_BOUND('',#2868,.T.);
#2870=ADVANCED_FACE('F1929',(#2866,#2869),#2855,.F.);
#2871=CARTESIAN_POINT('',(390.525,133.35,-63.5));
#2872=DIRECTION('',(0.,0.,1.));
#2873=DIRECTION('',(1.,0.,0.));
#2874=AXIS2_PLACEMENT_3D('',#2871,#2872,#2873);
#2875=PLANE('',#2874);
#2876=CARTESIAN_POINT('',(381.,133.35,-63.5));
#2877=DIRECTION('',(0.,0.,-1.));
#2878=DIRECTION('',(-1.,0.,0.));
#2879=AXIS2_PLACEMENT_3D('',#2876,#2877,#2878);
#2880=CIRCLE('',#2879,9.52500000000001);
#2881=CARTESIAN_POINT('',(371.475,133.35,-63.5));
#2882=VERTEX_POINT('',#2881);
#2883=EDGE_CURVE('E3243',#2882,#2882,#2880,.T.);
#2884=ORIENTED_EDGE('',*,*,#2883,.F.);
#2885=EDGE_LOOP('',(#2884));
#2886=FACE_BOUND('',#2885,.T.);
#2887=ORIENTED_EDGE('',*,*,#2863,.T.);
#2888=EDGE_LOOP('',(#2887));
#2889=FACE_BOUND('',#2888,.T.);
#2890=ADVANCED_FACE('F1925',(#2886,#2889),#2875,.F.);
#2891=CARTESIAN_POINT('',(381.,133.35,-76.2));
#2892=DIRECTION('',(0.,0.,-1.));
#2893=DIRECTION('',(-1.,0.,0.));
#2894=AXIS2_PLACEMENT_3D('',#2891,#2892,#2893);
#2895=CYLINDRICAL_SURFACE('',#2894,9.52500000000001);
#2896=ORIENTED_EDGE('',*,*,#642,.F.);
#2897=EDGE_LOOP('',(#2896));
#2898=FACE_BOUND('',#2897,.T.);
#2899=ORIENTED_EDGE('',*,*,#2883,.T.);
#2900=EDGE_LOOP('',(#2899));
#2901=FACE_BOUND('',#2900,.T.);
#2902=ADVANCED_FACE('F1921',(#2898,#2901),#2895,.F.);
#2903=CARTESIAN_POINT('',(228.6,133.35,-76.2));
#2904=DIRECTION('',(0.,0.,-1.));
#2905=DIRECTION('',(-1.,0.,0.));
#2906=AXIS2_PLACEMENT_3D('',#2903,#2904,#2905);
#2907=CYLINDRICAL_SURFACE('',#2906,22.225);
#2908=CARTESIAN_POINT('',(228.6,133.35,-63.5));
#2909=DIRECTION('',(0.,0.,-1.));
#2910=DIRECTION('',(-1.,0.,0.));
#2911=AXIS2_PLACEMENT_3D('',#2908,#2909,#2910);
#2912=CIRCLE('',#2911,22.225);
#2913=CARTESIAN_POINT('',(206.375,133.35,-63.5));
#2914=VERTEX_POINT('',#2913);
#2915=EDGE_CURVE('E3208',#2914,#2914,#2912,.T.);
#2916=ORIENTED_EDGE('',*,*,#2915,.F.);
#2917=EDGE_LOOP('',(#2916));
#2918=FACE_BOUND('',#2917,.T.);
#2919=ORIENTED_EDGE('',*,*,#1713,.T.);
#2920=EDGE_LOOP('',(#2919));
#2921=FACE_BOUND('',#2920,.T.);
#2922=ADVANCED_FACE('F1917',(#2918,#2921),#2907,.F.);
#2923=CARTESIAN_POINT('',(238.125,133.35,-63.5));
#2924=DIRECTION('',(0.,0.,1.));
#2925=DIRECTION('',(1.,0.,0.));
#2926=AXIS2_PLACEMENT_3D('',#2923,#2924,#2925);
#2927=PLANE('',#2926);
#2928=CARTESIAN_POINT('',(228.6,133.35,-63.5));
#2929=DIRECTION('',(0.,0.,-1.));
#2930=DIRECTION('',(-1.,0.,0.));
#2931=AXIS2_PLACEMENT_3D('',#2928,#2929,#2930);
#2932=CIRCLE('',#2931,9.52500000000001);
#2933=CARTESIAN_POINT('',(219.075,133.35,-63.5));
#2934=VERTEX_POINT('',#2933);
#2935=EDGE_CURVE('E3201',#2934,#2934,#2932,.T.);
#2936=ORIENTED_EDGE('',*,*,#2935,.F.);
#2937=EDGE_LOOP('',(#2936));
#2938=FACE_BOUND('',#2937,.T.);
#2939=ORIENTED_EDGE('',*,*,#2915,.T.);
#2940=EDGE_LOOP('',(#2939));
#2941=FACE_BOUND('',#2940,.T.);
#2942=ADVANCED_FACE('F1913',(#2938,#2941),#2927,.F.);
#2943=CARTESIAN_POINT('',(228.6,133.35,-76.2));
#2944=DIRECTION('',(0.,0.,-1.));
#2945=DIRECTION('',(-1.,0.,0.));
#2946=AXIS2_PLACEMENT_3D('',#2943,#2944,#2945);
#2947=CYLINDRICAL_SURFACE('',#2946,9.52500000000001);
#2948=ORIENTED_EDGE('',*,*,#550,.F.);
#2949=EDGE_LOOP('',(#2948));
#2950=FACE_BOUND('',#2949,.T.);
#2951=ORIENTED_EDGE('',*,*,#2935,.T.);
#2952=EDGE_LOOP('',(#2951));
#2953=FACE_BOUND('',#2952,.T.);
#2954=ADVANCED_FACE('F1909',(#2950,#2953),#2947,.F.);
#2955=CARTESIAN_POINT('',(228.6,260.35,-76.2));
#2956=DIRECTION('',(0.,0.,-1.));
#2957=DIRECTION('',(-1.,0.,0.));
#2958=AXIS2_PLACEMENT_3D('',#2955,#2956,#2957);
#2959=CYLINDRICAL_SURFACE('',#2958,22.225);
#2960=CARTESIAN_POINT('',(228.6,260.35,-63.5));
#2961=DIRECTION('',(0.,0.,-1.));
#2962=DIRECTION('',(-1.,0.,0.));
#2963=AXIS2_PLACEMENT_3D('',#2960,#2961,#2962);
#2964=CIRCLE('',#2963,22.225);
#2965=CARTESIAN_POINT('',(206.375,260.35,-63.5));
#2966=VERTEX_POINT('',#2965);
#2967=EDGE_CURVE('E3223',#2966,#2966,#2964,.T.);
#2968=ORIENTED_EDGE('',*,*,#2967,.F.);
#2969=EDGE_LOOP('',(#2968));
#2970=FACE_BOUND('',#2969,.T.);
#2971=ORIENTED_EDGE('',*,*,#1702,.T.);
#2972=EDGE_LOOP('',(#2971));
#2973=FACE_BOUND('',#2972,.T.);
#2974=ADVANCED_FACE('F1905',(#2970,#2973),#2959,.F.);
#2975=CARTESIAN_POINT('',(238.125,260.35,-63.5));
#2976=DIRECTION('',(0.,0.,1.));
#2977=DIRECTION('',(1.,0.,0.));
#2978=AXIS2_PLACEMENT_3D('',#2975,#2976,#2977);
#2979=PLANE('',#2978);
#2980=CARTESIAN_POINT('',(228.6,260.35,-63.5));
#2981=DIRECTION('',(0.,0.,-1.));
#2982=DIRECTION('',(-1.,0.,0.));
#2983=AXIS2_PLACEMENT_3D('',#2980,#2981,#2982);
#2984=CIRCLE('',#2983,9.52500000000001);
#2985=CARTESIAN_POINT('',(219.075,260.35,-63.5));
#2986=VERTEX_POINT('',#2985);
#2987=EDGE_CURVE('E3227',#2986,#2986,#2984,.T.);
#2988=ORIENTED_EDGE('',*,*,#2987,.F.);
#2989=EDGE_LOOP('',(#2988));
#2990=FACE_BOUND('',#2989,.T.);
#2991=ORIENTED_EDGE('',*,*,#2967,.T.);
#2992=EDGE_LOOP('',(#2991));
#2993=FACE_BOUND('',#2992,.T.);
#2994=ADVANCED_FACE('F1901',(#2990,#2993),#2979,.F.);
#2995=CARTESIAN_POINT('',(228.6,260.35,-76.2));
#2996=DIRECTION('',(0.,0.,-1.));
#2997=DIRECTION('',(-1.,0.,0.));
#2998=AXIS2_PLACEMENT_3D('',#2995,#2996,#2997);
#2999=CYLINDRICAL_SURFACE('',#2998,9.52500000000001);
#3000=ORIENTED_EDGE('',*,*,#653,.F.);
#3001=EDGE_LOOP('',(#3000));
#3002=FACE_BOUND('',#3001,.T.);
#3003=ORIENTED_EDGE('',*,*,#2987,.T.);
#3004=EDGE_LOOP('',(#3003));
#3005=FACE_BOUND('',#3004,.T.);
#3006=ADVANCED_FACE('F1807',(#3002,#3005),#2999,.F.);
#3007=CARTESIAN_POINT('',(250.825,288.925,-25.4));
#3008=DIRECTION('',(0.,0.,1.));
#3009=DIRECTION('',(1.,0.,0.));
#3010=AXIS2_PLACEMENT_3D('',#3007,#3008,#3009);
#3011=CONICAL_SURFACE('',#3010,3.17500000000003,0.1221730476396);
#3012=ORIENTED_EDGE('',*,*,#346,.T.);
#3013=DIRECTION('',(-0.121869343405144,0.,0.992546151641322));
#3014=VECTOR('',#3013,1.);
#3015=CARTESIAN_POINT('',(247.65,288.925,-25.4));
#3016=LINE('',#3015,#3014);
#3017=EDGE_CURVE('E3368',#122,#345,#3016,.T.);
#3018=ORIENTED_EDGE('',*,*,#3017,.F.);
#3019=ORIENTED_EDGE('',*,*,#123,.F.);
#3020=DIRECTION('',(0.,0.121869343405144,0.992546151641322));
#3021=VECTOR('',#3020,1.);
#3022=CARTESIAN_POINT('',(250.825,292.1,-25.4));
#3023=LINE('',#3022,#3021);
#3024=EDGE_CURVE('E3586',#120,#343,#3023,.T.);
#3025=ORIENTED_EDGE('',*,*,#3024,.T.);
#3026=EDGE_LOOP('',(#3012,#3018,#3019,#3025));
#3027=FACE_BOUND('',#3026,.T.);
#3028=ADVANCED_FACE('F1803',(#3027),#3011,.F.);
#3029=CARTESIAN_POINT('',(331.909563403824,292.1,-25.4));
#3030=DIRECTION('',(0.,0.992546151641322,-0.121869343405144));
#3031=DIRECTION('',(0.,0.121869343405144,0.992546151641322));
#3032=AXIS2_PLACEMENT_3D('',#3029,#3030,#3031);
#3033=PLANE('',#3032);
#3034=ORIENTED_EDGE('',*,*,#354,.T.);
#3035=ORIENTED_EDGE('',*,*,#3024,.F.);
#3036=ORIENTED_EDGE('',*,*,#316,.F.);
#3037=DIRECTION('',(0.,0.121869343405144,0.992546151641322));
#3038=VECTOR('',#3037,1.);
#3039=CARTESIAN_POINT('',(331.909563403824,292.1,-25.4));
#3040=LINE('',#3039,#3038);
#3041=EDGE_CURVE('E3361',#309,#353,#3040,.T.);
#3042=ORIENTED_EDGE('',*,*,#3041,.T.);
#3043=EDGE_LOOP('',(#3034,#3035,#3036,#3042));
#3044=FACE_BOUND('',#3043,.T.);
#3045=ADVANCED_FACE('F1806',(#3044),#3033,.F.);
#3046=CARTESIAN_POINT('',(331.909563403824,288.925,-25.4));
#3047=DIRECTION('',(0.,0.,1.));
#3048=DIRECTION('',(1.,0.,0.));
#3049=AXIS2_PLACEMENT_3D('',#3046,#3047,#3048);
#3050=CONICAL_SURFACE('',#3049,3.17500000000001,0.1221730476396);
#3051=ORIENTED_EDGE('',*,*,#363,.T.);
#3052=ORIENTED_EDGE('',*,*,#3041,.F.);
#3053=ORIENTED_EDGE('',*,*,#310,.F.);
#3054=DIRECTION('',(0.121869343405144,0.,0.992546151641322));
#3055=VECTOR('',#3054,1.);
#3056=CARTESIAN_POINT('',(335.084563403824,288.925,-25.4));
#3057=LINE('',#3056,#3055);
#3058=EDGE_CURVE('E3578',#300,#362,#3057,.T.);
#3059=ORIENTED_EDGE('',*,*,#3058,.T.);
#3060=EDGE_LOOP('',(#3051,#3052,#3053,#3059));
#3061=FACE_BOUND('',#3060,.T.);
#3062=ADVANCED_FACE('F1891',(#3061),#3050,.F.);
#3063=CARTESIAN_POINT('',(335.084563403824,220.400978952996,-25.4));
#3064=DIRECTION('',(0.992546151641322,0.,-0.121869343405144));
#3065=DIRECTION('',(-0.121869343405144,0.,-0.992546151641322));
#3066=AXIS2_PLACEMENT_3D('',#3063,#3064,#3065);
#3067=PLANE('',#3066);
#3068=ORIENTED_EDGE('',*,*,#371,.T.);
#3069=ORIENTED_EDGE('',*,*,#3058,.F.);
#3070=ORIENTED_EDGE('',*,*,#301,.F.);
#3071=DIRECTION('',(0.121869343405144,0.,0.992546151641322));
#3072=VECTOR('',#3071,1.);
#3073=CARTESIAN_POINT('',(335.084563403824,220.400978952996,-25.4));
#3074=LINE('',#3073,#3072);
#3075=EDGE_CURVE('E3572',#292,#370,#3074,.T.);
#3076=ORIENTED_EDGE('',*,*,#3075,.T.);
#3077=EDGE_LOOP('',(#3068,#3069,#3070,#3076));
#3078=FACE_BOUND('',#3077,.T.);
#3079=ADVANCED_FACE('F1887',(#3078),#3067,.F.);
#3080=CARTESIAN_POINT('',(338.259563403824,220.400978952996,-25.4));
#3081=DIRECTION('',(0.,0.,-1.));
#3082=DIRECTION('',(-1.,0.,0.));
#3083=AXIS2_PLACEMENT_3D('',#3080,#3081,#3082);
#3084=CONICAL_SURFACE('',#3083,3.17500000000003,0.1221730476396);
#3085=ORIENTED_EDGE('',*,*,#380,.T.);
#3086=ORIENTED_EDGE('',*,*,#3075,.F.);
#3087=ORIENTED_EDGE('',*,*,#293,.F.);
#3088=DIRECTION('',(0.,0.121869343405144,0.992546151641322));
#3089=VECTOR('',#3088,1.);
#3090=CARTESIAN_POINT('',(338.259563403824,217.225978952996,-25.4));
#3091=LINE('',#3090,#3089);
#3092=EDGE_CURVE('E3567',#283,#379,#3091,.T.);
#3093=ORIENTED_EDGE('',*,*,#3092,.T.);
#3094=EDGE_LOOP('',(#3085,#3086,#3087,#3093));
#3095=FACE_BOUND('',#3094,.T.);
#3096=ADVANCED_FACE('F1883',(#3095),#3084,.T.);
#3097=CARTESIAN_POINT('',(402.352375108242,217.225978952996,-25.4));
#3098=DIRECTION('',(0.,0.992546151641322,-0.121869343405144));
#3099=DIRECTION('',(0.,0.121869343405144,0.992546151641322));
#3100=AXIS2_PLACEMENT_3D('',#3097,#3098,#3099);
#3101=PLANE('',#3100);
#3102=ORIENTED_EDGE('',*,*,#388,.T.);
#3103=ORIENTED_EDGE('',*,*,#3092,.F.);
#3104=ORIENTED_EDGE('',*,*,#284,.F.);
#3105=DIRECTION('',(0.,0.121869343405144,0.992546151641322));
#3106=VECTOR('',#3105,1.);
#3107=CARTESIAN_POINT('',(402.352375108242,217.225978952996,-25.4));
#3108=LINE('',#3107,#3106);
#3109=EDGE_CURVE('E3560',#275,#387,#3108,.T.);
#3110=ORIENTED_EDGE('',*,*,#3109,.T.);
#3111=EDGE_LOOP('',(#3102,#3103,#3104,#3110));
#3112=FACE_BOUND('',#3111,.T.);
#3113=ADVANCED_FACE('F1879',(#3112),#3101,.F.);
#3114=CARTESIAN_POINT('',(402.352375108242,214.050978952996,-25.4));
#3115=DIRECTION('',(0.,0.,1.));
#3116=DIRECTION('',(1.,0.,0.));
#3117=AXIS2_PLACEMENT_3D('',#3114,#3115,#3116);
#3118=CONICAL_SURFACE('',#3117,3.175,0.1221730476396);
#3119=ORIENTED_EDGE('',*,*,#397,.T.);
#3120=ORIENTED_EDGE('',*,*,#3109,.F.);
#3121=ORIENTED_EDGE('',*,*,#276,.F.);
#3122=DIRECTION('',(0.121869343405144,0.,0.992546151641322));
#3123=VECTOR('',#3122,1.);
#3124=CARTESIAN_POINT('',(405.527375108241,214.050978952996,-25.4));
#3125=LINE('',#3124,#3123);
#3126=EDGE_CURVE('E3554',#266,#396,#3125,.T.);
#3127=ORIENTED_EDGE('',*,*,#3126,.T.);
#3128=EDGE_LOOP('',(#3119,#3120,#3121,#3127));
#3129=FACE_BOUND('',#3128,.T.);
#3130=ADVANCED_FACE('F1875',(#3129),#3118,.F.);
#3131=CARTESIAN_POINT('',(405.527375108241,169.600978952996,-25.4));
#3132=DIRECTION('',(0.992546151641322,0.,-0.121869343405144));
#3133=DIRECTION('',(-0.121869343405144,0.,-0.992546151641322));
#3134=AXIS2_PLACEMENT_3D('',#3131,#3132,#3133);
#3135=PLANE('',#3134);
#3136=ORIENTED_EDGE('',*,*,#405,.T.);
#3137=ORIENTED_EDGE('',*,*,#3126,.F.);
#3138=ORIENTED_EDGE('',*,*,#267,.F.);
#3139=DIRECTION('',(0.121869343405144,0.,0.992546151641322));
#3140=VECTOR('',#3139,1.);
#3141=CARTESIAN_POINT('',(405.527375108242,169.600978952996,-25.4));
#3142=LINE('',#3141,#3140);
#3143=EDGE_CURVE('E3549',#258,#404,#3142,.T.);
#3144=ORIENTED_EDGE('',*,*,#3143,.T.);
#3145=EDGE_LOOP('',(#3136,#3137,#3138,#3144));
#3146=FACE_BOUND('',#3145,.T.);
#3147=ADVANCED_FACE('F1871',(#3146),#3135,.F.);
#3148=CARTESIAN_POINT('',(402.352375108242,169.600978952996,-25.4));
#3149=DIRECTION('',(0.,0.,1.));
#3150=DIRECTION('',(1.,0.,0.));
#3151=AXIS2_PLACEMENT_3D('',#3148,#3149,#3150);
#3152=CONICAL_SURFACE('',#3151,3.17500000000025,0.1221730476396);
#3153=ORIENTED_EDGE('',*,*,#414,.T.);
#3154=ORIENTED_EDGE('',*,*,#3143,.F.);
#3155=ORIENTED_EDGE('',*,*,#259,.F.);
#3156=DIRECTION('',(0.,-0.121869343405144,0.992546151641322));
#3157=VECTOR('',#3156,1.);
#3158=CARTESIAN_POINT('',(402.352375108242,166.425978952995,-25.4));
#3159=LINE('',#3158,#3157);
#3160=EDGE_CURVE('E3543',#249,#413,#3159,.T.);
#3161=ORIENTED_EDGE('',*,*,#3160,.T.);
#3162=EDGE_LOOP('',(#3153,#3154,#3155,#3161));
#3163=FACE_BOUND('',#3162,.T.);
#3164=ADVANCED_FACE('F1867',(#3163),#3152,.F.);
#3165=CARTESIAN_POINT('',(338.259563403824,166.425978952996,-25.4));
#3166=DIRECTION('',(0.,-0.992546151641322,-0.121869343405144));
#3167=DIRECTION('',(0.,0.121869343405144,-0.992546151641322));
#3168=AXIS2_PLACEMENT_3D('',#3165,#3166,#3167);
#3169=PLANE('',#3168);
#3170=ORIENTED_EDGE('',*,*,#422,.T.);
#3171=ORIENTED_EDGE('',*,*,#3160,.F.);
#3172=ORIENTED_EDGE('',*,*,#250,.F.);
#3173=DIRECTION('',(0.,-0.121869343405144,0.992546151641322));
#3174=VECTOR('',#3173,1.);
#3175=CARTESIAN_POINT('',(338.259563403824,166.425978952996,-25.4));
#3176=LINE('',#3175,#3174);
#3177=EDGE_CURVE('E3537',#241,#421,#3176,.T.);
#3178=ORIENTED_EDGE('',*,*,#3177,.T.);
#3179=EDGE_LOOP('',(#3170,#3171,#3172,#3178));
#3180=FACE_BOUND('',#3179,.T.);
#3181=ADVANCED_FACE('F1863',(#3180),#3169,.F.);
#3182=CARTESIAN_POINT('',(338.259563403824,163.250978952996,-25.4));
#3183=DIRECTION('',(0.,0.,-1.));
#3184=DIRECTION('',(-1.,0.,0.));
#3185=AXIS2_PLACEMENT_3D('',#3182,#3183,#3184);
#3186=CONICAL_SURFACE('',#3185,3.17500000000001,0.1221730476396);
#3187=ORIENTED_EDGE('',*,*,#431,.T.);
#3188=ORIENTED_EDGE('',*,*,#3177,.F.);
#3189=ORIENTED_EDGE('',*,*,#242,.F.);
#3190=DIRECTION('',(0.121869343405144,0.,0.992546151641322));
#3191=VECTOR('',#3190,1.);
#3192=CARTESIAN_POINT('',(335.084563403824,163.250978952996,-25.4));
#3193=LINE('',#3192,#3191);
#3194=EDGE_CURVE('E3532',#232,#430,#3193,.T.);
#3195=ORIENTED_EDGE('',*,*,#3194,.T.);
#3196=EDGE_LOOP('',(#3187,#3188,#3189,#3195));
#3197=FACE_BOUND('',#3196,.T.);
#3198=ADVANCED_FACE('F1859',(#3197),#3186,.T.);
#3199=CARTESIAN_POINT('',(335.084563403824,111.125,-25.4));
#3200=DIRECTION('',(0.992546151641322,0.,-0.121869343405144));
#3201=DIRECTION('',(-0.121869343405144,0.,-0.992546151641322));
#3202=AXIS2_PLACEMENT_3D('',#3199,#3200,#3201);
#3203=PLANE('',#3202);
#3204=ORIENTED_EDGE('',*,*,#439,.T.);
#3205=ORIENTED_EDGE('',*,*,#3194,.F.);
#3206=ORIENTED_EDGE('',*,*,#233,.F.);
#3207=DIRECTION('',(0.121869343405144,0.,0.992546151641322));
#3208=VECTOR('',#3207,1.);
#3209=CARTESIAN_POINT('',(335.084563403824,111.125,-25.4));
#3210=LINE('',#3209,#3208);
#3211=EDGE_CURVE('E3527',#224,#438,#3210,.T.);
#3212=ORIENTED_EDGE('',*,*,#3211,.T.);
#3213=EDGE_LOOP('',(#3204,#3205,#3206,#3212));
#3214=FACE_BOUND('',#3213,.T.);
#3215=ADVANCED_FACE('F1855',(#3214),#3203,.F.);
#3216=CARTESIAN_POINT('',(331.909563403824,111.125,-25.4));
#3217=DIRECTION('',(0.,0.,1.));
#3218=DIRECTION('',(1.,0.,0.));
#3219=AXIS2_PLACEMENT_3D('',#3216,#3217,#3218);
#3220=CONICAL_SURFACE('',#3219,3.17499999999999,0.1221730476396);
#3221=ORIENTED_EDGE('',*,*,#448,.T.);
#3222=ORIENTED_EDGE('',*,*,#3211,.F.);
#3223=ORIENTED_EDGE('',*,*,#225,.F.);
#3224=DIRECTION('',(0.,-0.121869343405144,0.992546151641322));
#3225=VECTOR('',#3224,1.);
#3226=CARTESIAN_POINT('',(331.909563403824,107.95,-25.4));
#3227=LINE('',#3226,#3225);
#3228=EDGE_CURVE('E3521',#215,#447,#3227,.T.);
#3229=ORIENTED_EDGE('',*,*,#3228,.T.);
#3230=EDGE_LOOP('',(#3221,#3222,#3223,#3229));
#3231=FACE_BOUND('',#3230,.T.);
#3232=ADVANCED_FACE('F1851',(#3231),#3220,.F.);
#3233=CARTESIAN_POINT('',(250.825,107.95,-25.4));
#3234=DIRECTION('',(0.,-0.992546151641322,-0.121869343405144));
#3235=DIRECTION('',(0.,0.121869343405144,-0.992546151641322));
#3236=AXIS2_PLACEMENT_3D('',#3233,#3234,#3235);
#3237=PLANE('',#3236);
#3238=ORIENTED_EDGE('',*,*,#456,.T.);
#3239=ORIENTED_EDGE('',*,*,#3228,.F.);
#3240=ORIENTED_EDGE('',*,*,#216,.F.);
#3241=DIRECTION('',(0.,-0.121869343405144,0.992546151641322));
#3242=VECTOR('',#3241,1.);
#3243=CARTESIAN_POINT('',(250.825,107.95,-25.4));
#3244=LINE('',#3243,#3242);
#3245=EDGE_CURVE('E3516',#207,#455,#3244,.T.);
#3246=ORIENTED_EDGE('',*,*,#3245,.T.);
#3247=EDGE_LOOP('',(#3238,#3239,#3240,#3246));
#3248=FACE_BOUND('',#3247,.T.);
#3249=ADVANCED_FACE('F1847',(#3248),#3237,.F.);
#3250=CARTESIAN_POINT('',(250.825,111.125,-25.4));
#3251=DIRECTION('',(0.,0.,1.));
#3252=DIRECTION('',(1.,0.,0.));
#3253=AXIS2_PLACEMENT_3D('',#3250,#3251,#3252);
#3254=CONICAL_SURFACE('',#3253,3.175,0.1221730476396);
#3255=ORIENTED_EDGE('',*,*,#465,.T.);
#3256=ORIENTED_EDGE('',*,*,#3245,.F.);
#3257=ORIENTED_EDGE('',*,*,#208,.F.);
#3258=DIRECTION('',(-0.121869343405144,0.,0.992546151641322));
#3259=VECTOR('',#3258,1.);
#3260=CARTESIAN_POINT('',(247.65,111.125,-25.4));
#3261=LINE('',#3260,#3259);
#3262=EDGE_CURVE('E3510',#198,#464,#3261,.T.);
#3263=ORIENTED_EDGE('',*,*,#3262,.T.);
#3264=EDGE_LOOP('',(#3255,#3256,#3257,#3263));
#3265=FACE_BOUND('',#3264,.T.);
#3266=ADVANCED_FACE('F1843',(#3265),#3254,.F.);
#3267=CARTESIAN_POINT('',(247.65,163.250978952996,-25.4));
#3268=DIRECTION('',(-0.992546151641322,0.,-0.121869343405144));
#3269=DIRECTION('',(-0.121869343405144,0.,0.992546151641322));
#3270=AXIS2_PLACEMENT_3D('',#3267,#3268,#3269);
#3271=PLANE('',#3270);
#3272=ORIENTED_EDGE('',*,*,#473,.T.);
#3273=ORIENTED_EDGE('',*,*,#3262,.F.);
#3274=ORIENTED_EDGE('',*,*,#199,.F.);
#3275=DIRECTION('',(-0.121869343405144,0.,0.992546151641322));
#3276=VECTOR('',#3275,1.);
#3277=CARTESIAN_POINT('',(247.65,163.250978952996,-25.4));
#3278=LINE('',#3277,#3276);
#3279=EDGE_CURVE('E3504',#190,#472,#3278,.T.);
#3280=ORIENTED_EDGE('',*,*,#3279,.T.);
#3281=EDGE_LOOP('',(#3272,#3273,#3274,#3280));
#3282=FACE_BOUND('',#3281,.T.);
#3283=ADVANCED_FACE('F1839',(#3282),#3271,.F.);
#3284=CARTESIAN_POINT('',(244.475,163.250978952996,-25.4));
#3285=DIRECTION('',(0.,0.,-1.));
#3286=DIRECTION('',(-1.,0.,0.));
#3287=AXIS2_PLACEMENT_3D('',#3284,#3285,#3286);
#3288=CONICAL_SURFACE('',#3287,3.175,0.1221730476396);
#3289=ORIENTED_EDGE('',*,*,#482,.T.);
#3290=ORIENTED_EDGE('',*,*,#3279,.F.);
#3291=ORIENTED_EDGE('',*,*,#191,.F.);
#3292=DIRECTION('',(0.,-0.121869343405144,0.992546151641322));
#3293=VECTOR('',#3292,1.);
#3294=CARTESIAN_POINT('',(244.475,166.425978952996,-25.4));
#3295=LINE('',#3294,#3293);
#3296=EDGE_CURVE('E3499',#181,#481,#3295,.T.);
#3297=ORIENTED_EDGE('',*,*,#3296,.T.);
#3298=EDGE_LOOP('',(#3289,#3290,#3291,#3297));
#3299=FACE_BOUND('',#3298,.T.);
#3300=ADVANCED_FACE('F1835',(#3299),#3288,.T.);
#3301=CARTESIAN_POINT('',(174.625,166.425978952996,-25.4));
#3302=DIRECTION('',(0.,-0.992546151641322,-0.121869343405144));
#3303=DIRECTION('',(0.,0.121869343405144,-0.992546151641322));
#3304=AXIS2_PLACEMENT_3D('',#3301,#3302,#3303);
#3305=PLANE('',#3304);
#3306=ORIENTED_EDGE('',*,*,#490,.T.);
#3307=ORIENTED_EDGE('',*,*,#3296,.F.);
#3308=ORIENTED_EDGE('',*,*,#182,.F.);
#3309=DIRECTION('',(0.,-0.121869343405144,0.992546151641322));
#3310=VECTOR('',#3309,1.);
#3311=CARTESIAN_POINT('',(174.625,166.425978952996,-25.4));
#3312=LINE('',#3311,#3310);
#3313=EDGE_CURVE('E3494',#173,#489,#3312,.T.);
#3314=ORIENTED_EDGE('',*,*,#3313,.T.);
#3315=EDGE_LOOP('',(#3306,#3307,#3308,#3314));
#3316=FACE_BOUND('',#3315,.T.);
#3317=ADVANCED_FACE('F1831',(#3316),#3305,.F.);
#3318=CARTESIAN_POINT('',(174.625,169.600978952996,-25.4));
#3319=DIRECTION('',(0.,0.,1.));
#3320=DIRECTION('',(1.,0.,0.));
#3321=AXIS2_PLACEMENT_3D('',#3318,#3319,#3320);
#3322=CONICAL_SURFACE('',#3321,3.17500000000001,0.1221730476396);
#3323=ORIENTED_EDGE('',*,*,#499,.T.);
#3324=ORIENTED_EDGE('',*,*,#3313,.F.);
#3325=ORIENTED_EDGE('',*,*,#174,.F.);
#3326=DIRECTION('',(-0.121869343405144,0.,0.992546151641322));
#3327=VECTOR('',#3326,1.);
#3328=CARTESIAN_POINT('',(171.45,169.600978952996,-25.4));
#3329=LINE('',#3328,#3327);
#3330=EDGE_CURVE('E3488',#164,#498,#3329,.T.);
#3331=ORIENTED_EDGE('',*,*,#3330,.T.);
#3332=EDGE_LOOP('',(#3323,#3324,#3325,#3331));
#3333=FACE_BOUND('',#3332,.T.);
#3334=ADVANCED_FACE('F1827',(#3333),#3322,.F.);
#3335=CARTESIAN_POINT('',(171.45,214.050978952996,-25.4));
#3336=DIRECTION('',(-0.992546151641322,0.,-0.121869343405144));
#3337=DIRECTION('',(-0.121869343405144,0.,0.992546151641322));
#3338=AXIS2_PLACEMENT_3D('',#3335,#3336,#3337);
#3339=PLANE('',#3338);
#3340=ORIENTED_EDGE('',*,*,#507,.T.);
#3341=ORIENTED_EDGE('',*,*,#3330,.F.);
#3342=ORIENTED_EDGE('',*,*,#165,.F.);
#3343=DIRECTION('',(-0.121869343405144,0.,0.992546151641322));
#3344=VECTOR('',#3343,1.);
#3345=CARTESIAN_POINT('',(171.45,214.050978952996,-25.4));
#3346=LINE('',#3345,#3344);
#3347=EDGE_CURVE('E3483',#156,#506,#3346,.T.);
#3348=ORIENTED_EDGE('',*,*,#3347,.T.);
#3349=EDGE_LOOP('',(#3340,#3341,#3342,#3348));
#3350=FACE_BOUND('',#3349,.T.);
#3351=ADVANCED_FACE('F1823',(#3350),#3339,.F.);
#3352=CARTESIAN_POINT('',(174.625,214.050978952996,-25.4));
#3353=DIRECTION('',(0.,0.,1.));
#3354=DIRECTION('',(1.,0.,0.));
#3355=AXIS2_PLACEMENT_3D('',#3352,#3353,#3354);
#3356=CONICAL_SURFACE('',#3355,3.17500000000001,0.1221730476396);
#3357=ORIENTED_EDGE('',*,*,#516,.T.);
#3358=ORIENTED_EDGE('',*,*,#3347,.F.);
#3359=ORIENTED_EDGE('',*,*,#157,.F.);
#3360=DIRECTION('',(0.,0.121869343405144,0.992546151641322));
#3361=VECTOR('',#3360,1.);
#3362=CARTESIAN_POINT('',(174.625,217.225978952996,-25.4));
#3363=LINE('',#3362,#3361);
#3364=EDGE_CURVE('E3477',#147,#515,#3363,.T.);
#3365=ORIENTED_EDGE('',*,*,#3364,.T.);
#3366=EDGE_LOOP('',(#3357,#3358,#3359,#3365));
#3367=FACE_BOUND('',#3366,.T.);
#3368=ADVANCED_FACE('F1819',(#3367),#3356,.F.);
#3369=CARTESIAN_POINT('',(244.475,217.225978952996,-25.4));
#3370=DIRECTION('',(0.,0.992546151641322,-0.121869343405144));
#3371=DIRECTION('',(0.,0.121869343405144,0.992546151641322));
#3372=AXIS2_PLACEMENT_3D('',#3369,#3370,#3371);
#3373=PLANE('',#3372);
#3374=ORIENTED_EDGE('',*,*,#524,.T.);
#3375=ORIENTED_EDGE('',*,*,#3364,.F.);
#3376=ORIENTED_EDGE('',*,*,#148,.F.);
#3377=DIRECTION('',(0.,0.121869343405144,0.992546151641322));
#3378=VECTOR('',#3377,1.);
#3379=CARTESIAN_POINT('',(244.475,217.225978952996,-25.4));
#3380=LINE('',#3379,#3378);
#3381=EDGE_CURVE('E3471',#139,#523,#3380,.T.);
#3382=ORIENTED_EDGE('',*,*,#3381,.T.);
#3383=EDGE_LOOP('',(#3374,#3375,#3376,#3382));
#3384=FACE_BOUND('',#3383,.T.);
#3385=ADVANCED_FACE('F1815',(#3384),#3373,.F.);
#3386=CARTESIAN_POINT('',(244.475,220.400978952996,-25.4));
#3387=DIRECTION('',(0.,0.,-1.));
#3388=DIRECTION('',(-1.,0.,0.));
#3389=AXIS2_PLACEMENT_3D('',#3386,#3387,#3388);
#3390=CONICAL_SURFACE('',#3389,3.17500000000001,0.1221730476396);
#3391=ORIENTED_EDGE('',*,*,#533,.T.);
#3392=ORIENTED_EDGE('',*,*,#3381,.F.);
#3393=ORIENTED_EDGE('',*,*,#140,.F.);
#3394=DIRECTION('',(-0.121869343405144,0.,0.992546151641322));
#3395=VECTOR('',#3394,1.);
#3396=CARTESIAN_POINT('',(247.65,220.400978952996,-25.4));
#3397=LINE('',#3396,#3395);
#3398=EDGE_CURVE('E3467',#130,#532,#3397,.T.);
#3399=ORIENTED_EDGE('',*,*,#3398,.T.);
#3400=EDGE_LOOP('',(#3391,#3392,#3393,#3399));
#3401=FACE_BOUND('',#3400,.T.);
#3402=ADVANCED_FACE('F1811',(#3401),#3390,.T.);
#3403=CARTESIAN_POINT('',(247.65,288.925,-25.4));
#3404=DIRECTION('',(-0.992546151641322,0.,-0.121869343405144));
#3405=DIRECTION('',(-0.121869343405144,0.,0.992546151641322));
#3406=AXIS2_PLACEMENT_3D('',#3403,#3404,#3405);
#3407=PLANE('',#3406);
#3408=ORIENTED_EDGE('',*,*,#539,.T.);
#3409=ORIENTED_EDGE('',*,*,#3398,.F.);
#3410=ORIENTED_EDGE('',*,*,#131,.F.);
#3411=ORIENTED_EDGE('',*,*,#3017,.T.);
#3412=EDGE_LOOP('',(#3408,#3409,#3410,#3411));
#3413=FACE_BOUND('',#3412,.T.);
#3414=ADVANCED_FACE('F1797',(#3413),#3407,.F.);
#3415=CARTESIAN_POINT('',(285.75,198.175978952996,-38.1000000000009));
#3416=DIRECTION('',(0.,0.,-1.));
#3417=DIRECTION('',(1.,0.,0.));
#3418=AXIS2_PLACEMENT_3D('',#3415,#3416,#3417);
#3419=CONICAL_SURFACE('',#3418,12.7,0.1221730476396);
#3420=CARTESIAN_POINT('',(285.75,198.175978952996,-28.5750000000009));
#3421=DIRECTION('',(0.,0.,1.));
#3422=DIRECTION('',(1.,0.,0.));
#3423=AXIS2_PLACEMENT_3D('',#3420,#3421,#3422);
#3424=CIRCLE('',#3423,11.5304770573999);
#3425=CARTESIAN_POINT('',(297.2804770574,198.175978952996,-28.5750000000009));
#3426=VERTEX_POINT('',#3425);
#3427=EDGE_CURVE('E3878',#3426,#3426,#3424,.T.);
#3428=ORIENTED_EDGE('',*,*,#3427,.F.);
#3429=EDGE_LOOP('',(#3428));
#3430=FACE_BOUND('',#3429,.T.);
#3431=ORIENTED_EDGE('',*,*,#327,.T.);
#3432=EDGE_LOOP('',(#3431));
#3433=FACE_BOUND('',#3432,.T.);
#3434=ADVANCED_FACE('F1793',(#3430,#3433),#3419,.T.);
#3435=CARTESIAN_POINT('',(285.75,198.175978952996,-28.5750000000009));
#3436=DIRECTION('',(0.,0.,1.));
#3437=DIRECTION('',(1.,0.,0.));
#3438=AXIS2_PLACEMENT_3D('',#3435,#3436,#3437);
#3439=PLANE('',#3438);
#3440=CARTESIAN_POINT('',(285.75,198.175978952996,-28.5750000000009));
#3441=DIRECTION('',(0.,0.,1.));
#3442=DIRECTION('',(1.,0.,0.));
#3443=AXIS2_PLACEMENT_3D('',#3440,#3441,#3442);
#3444=CIRCLE('',#3443,5.18047705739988);
#3445=CARTESIAN_POINT('',(290.9304770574,198.175978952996,-28.5750000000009));
#3446=VERTEX_POINT('',#3445);
#3447=EDGE_CURVE('E3655',#3446,#3446,#3444,.T.);
#3448=ORIENTED_EDGE('',*,*,#3447,.F.);
#3449=EDGE_LOOP('',(#3448));
#3450=FACE_BOUND('',#3449,.T.);
#3451=ORIENTED_EDGE('',*,*,#3427,.T.);
#3452=EDGE_LOOP('',(#3451));
#3453=FACE_BOUND('',#3452,.T.);
#3454=ADVANCED_FACE('F1789',(#3450,#3453),#3439,.T.);
#3455=CARTESIAN_POINT('',(285.75,198.175978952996,-76.2000000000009));
#3456=DIRECTION('',(0.,0.,1.));
#3457=DIRECTION('',(1.,0.,0.));
#3458=AXIS2_PLACEMENT_3D('',#3455,#3456,#3457);
#3459=CYLINDRICAL_SURFACE('',#3458,5.18047705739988);
#3460=ORIENTED_EDGE('',*,*,#1691,.F.);
#3461=EDGE_LOOP('',(#3460));
#3462=FACE_BOUND('',#3461,.T.);
#3463=ORIENTED_EDGE('',*,*,#3447,.T.);
#3464=EDGE_LOOP('',(#3463));
#3465=FACE_BOUND('',#3464,.T.);
#3466=ADVANCED_FACE('F1785',(#3462,#3465),#3459,.F.);
#3467=CARTESIAN_POINT('',(440.7,25.6903263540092,-25.4000000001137));
#3468=DIRECTION('',(0.,0.,1.));
#3469=DIRECTION('',(1.,0.,0.));
#3470=AXIS2_PLACEMENT_3D('',#3467,#3468,#3469);
#3471=CYLINDRICAL_SURFACE('',#3470,12.7);
#3472=ORIENTED_EDGE('',*,*,#1582,.T.);
#3473=DIRECTION('',(0.,0.,1.));
#3474=VECTOR('',#3473,1.);
#3475=CARTESIAN_POINT('',(428.,25.6903263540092,-25.4000000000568));
#3476=LINE('',#3475,#3474);
#3477=CARTESIAN_POINT('',(428.,25.6903263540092,-25.4000000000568));
#3478=VERTEX_POINT('',#3477);
#3479=EDGE_CURVE('E3648',#3478,#1572,#3476,.T.);
#3480=ORIENTED_EDGE('',*,*,#3479,.F.);
#3481=CARTESIAN_POINT('',(440.7,25.6903263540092,-25.4000000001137));
#3482=DIRECTION('',(0.,0.,1.));
#3483=DIRECTION('',(1.,0.,0.));
#3484=AXIS2_PLACEMENT_3D('',#3481,#3482,#3483);
#3485=CIRCLE('',#3484,12.7);
#3486=CARTESIAN_POINT('',(438.,38.1,-25.4000000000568));
#3487=VERTEX_POINT('',#3486);
#3488=EDGE_CURVE('E874',#3487,#3478,#3485,.T.);
#3489=ORIENTED_EDGE('',*,*,#3488,.F.);
#3490=DIRECTION('',(0.,0.,1.));
#3491=VECTOR('',#3490,1.);
#3492=CARTESIAN_POINT('',(438.,38.1,-25.4000000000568));
#3493=LINE('',#3492,#3491);
#3494=EDGE_CURVE('E3660',#3487,#1581,#3493,.T.);
#3495=ORIENTED_EDGE('',*,*,#3494,.T.);
#3496=EDGE_LOOP('',(#3472,#3480,#3489,#3495));
#3497=FACE_BOUND('',#3496,.T.);
#3498=ADVANCED_FACE('F1771',(#3497),#3471,.F.);
#3499=CARTESIAN_POINT('',(498.,38.1,-25.4000000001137));
#3500=DIRECTION('',(0.,1.,0.));
#3501=DIRECTION('',(0.,0.,1.));
#3502=AXIS2_PLACEMENT_3D('',#3499,#3500,#3501);
#3503=PLANE('',#3502);
#3504=ORIENTED_EDGE('',*,*,#1590,.T.);
#3505=ORIENTED_EDGE('',*,*,#3494,.F.);
#3506=DIRECTION('',(-1.,0.,9.473903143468E-13));
#3507=VECTOR('',#3506,1.);
#3508=CARTESIAN_POINT('',(498.,38.1,-25.4000000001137));
#3509=LINE('',#3508,#3507);
#3510=CARTESIAN_POINT('',(498.,38.1,-25.4000000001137));
#3511=VERTEX_POINT('',#3510);
#3512=EDGE_CURVE('E901',#3511,#3487,#3509,.T.);
#3513=ORIENTED_EDGE('',*,*,#3512,.F.);
#3514=DIRECTION('',(0.,0.,1.));
#3515=VECTOR('',#3514,1.);
#3516=CARTESIAN_POINT('',(498.,38.1,-25.4000000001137));
#3517=LINE('',#3516,#3515);
#3518=EDGE_CURVE('E4289',#3511,#1589,#3517,.T.);
#3519=ORIENTED_EDGE('',*,*,#3518,.T.);
#3520=EDGE_LOOP('',(#3504,#3505,#3513,#3519));
#3521=FACE_BOUND('',#3520,.T.);
#3522=ADVANCED_FACE('F1767',(#3521),#3503,.F.);
#3523=CARTESIAN_POINT('',(495.3,25.6903263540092,-25.4000000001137));
#3524=DIRECTION('',(0.,0.,1.));
#3525=DIRECTION('',(1.,0.,0.));
#3526=AXIS2_PLACEMENT_3D('',#3523,#3524,#3525);
#3527=CYLINDRICAL_SURFACE('',#3526,12.7);
#3528=ORIENTED_EDGE('',*,*,#1599,.T.);
#3529=ORIENTED_EDGE('',*,*,#3518,.F.);
#3530=CARTESIAN_POINT('',(495.3,25.6903263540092,-25.4000000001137));
#3531=DIRECTION('',(0.,0.,1.));
#3532=DIRECTION('',(1.,0.,0.));
#3533=AXIS2_PLACEMENT_3D('',#3530,#3531,#3532);
#3534=CIRCLE('',#3533,12.7);
#3535=CARTESIAN_POINT('',(508.,25.6903263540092,-25.4000000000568));
#3536=VERTEX_POINT('',#3535);
#3537=EDGE_CURVE('E897',#3536,#3511,#3534,.T.);
#3538=ORIENTED_EDGE('',*,*,#3537,.F.);
#3539=DIRECTION('',(0.,0.,1.));
#3540=VECTOR('',#3539,1.);
#3541=CARTESIAN_POINT('',(508.,25.6903263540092,-25.4000000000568));
#3542=LINE('',#3541,#3540);
#3543=EDGE_CURVE('E4291',#3536,#1598,#3542,.T.);
#3544=ORIENTED_EDGE('',*,*,#3543,.T.);
#3545=EDGE_LOOP('',(#3528,#3529,#3538,#3544));
#3546=FACE_BOUND('',#3545,.T.);
#3547=ADVANCED_FACE('F1770',(#3546),#3527,.F.);
#3548=CARTESIAN_POINT('',(508.,0.,-25.4000000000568));
#3549=DIRECTION('',(1.,0.,0.));
#3550=DIRECTION('',(0.,0.,-1.));
#3551=AXIS2_PLACEMENT_3D('',#3548,#3549,#3550);
#3552=PLANE('',#3551);
#3553=ORIENTED_EDGE('',*,*,#1605,.T.);
#3554=ORIENTED_EDGE('',*,*,#3543,.F.);
#3555=DIRECTION('',(0.,1.,0.));
#3556=VECTOR('',#3555,1.);
#3557=CARTESIAN_POINT('',(508.,0.,-25.4000000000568));
#3558=LINE('',#3557,#3556);
#3559=EDGE_CURVE('E893',#1183,#3536,#3558,.T.);
#3560=ORIENTED_EDGE('',*,*,#3559,.F.);
#3561=ORIENTED_EDGE('',*,*,#1184,.T.);
#3562=EDGE_LOOP('',(#3553,#3554,#3560,#3561));
#3563=FACE_BOUND('',#3562,.T.);
#3564=ADVANCED_FACE('F1775',(#3563),#3552,.F.);
#3565=CARTESIAN_POINT('',(428.,25.6903263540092,-25.4000000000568));
#3566=DIRECTION('',(-1.,0.,0.));
#3567=DIRECTION('',(0.,0.,1.));
#3568=AXIS2_PLACEMENT_3D('',#3565,#3566,#3567);
#3569=PLANE('',#3568);
#3570=ORIENTED_EDGE('',*,*,#1573,.T.);
#3571=ORIENTED_EDGE('',*,*,#1200,.F.);
#3572=DIRECTION('',(0.,-1.,0.));
#3573=VECTOR('',#3572,1.);
#3574=CARTESIAN_POINT('',(428.,25.6903263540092,-25.4000000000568));
#3575=LINE('',#3574,#3573);
#3576=EDGE_CURVE('E878',#3478,#1191,#3575,.T.);
#3577=ORIENTED_EDGE('',*,*,#3576,.F.);
#3578=ORIENTED_EDGE('',*,*,#3479,.T.);
#3579=EDGE_LOOP('',(#3570,#3571,#3577,#3578));
#3580=FACE_BOUND('',#3579,.T.);
#3581=ADVANCED_FACE('F1765',(#3580),#3569,.F.);
#3582=CARTESIAN_POINT('',(440.7,25.6903263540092,-25.4000000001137));
#3583=DIRECTION('',(0.,0.,1.));
#3584=DIRECTION('',(1.,0.,0.));
#3585=AXIS2_PLACEMENT_3D('',#3582,#3583,#3584);
#3586=PLANE('',#3585);
#3587=ORIENTED_EDGE('',*,*,#3488,.T.);
#3588=ORIENTED_EDGE('',*,*,#3576,.T.);
#3589=ORIENTED_EDGE('',*,*,#1192,.T.);
#3590=ORIENTED_EDGE('',*,*,#3559,.T.);
#3591=ORIENTED_EDGE('',*,*,#3537,.T.);
#3592=ORIENTED_EDGE('',*,*,#3512,.T.);
#3593=EDGE_LOOP('',(#3587,#3588,#3589,#3590,#3591,#3592));
#3594=FACE_BOUND('',#3593,.T.);
#3595=ADVANCED_FACE('F1757',(#3594),#3586,.T.);
#3596=CARTESIAN_POINT('',(101.6,368.3,-25.4000000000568));
#3597=DIRECTION('',(-1.,0.,0.));
#3598=DIRECTION('',(0.,0.,1.));
#3599=AXIS2_PLACEMENT_3D('',#3596,#3597,#3598);
#3600=PLANE('',#3599);
#3601=ORIENTED_EDGE('',*,*,#1562,.F.);
#3602=DIRECTION('',(0.,0.,1.));
#3603=VECTOR('',#3602,1.);
#3604=CARTESIAN_POINT('',(101.6,381.,-25.4000000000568));
#3605=LINE('',#3604,#3603);
#3606=CARTESIAN_POINT('',(101.6,381.,-25.4000000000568));
#3607=VERTEX_POINT('',#3606);
#3608=EDGE_CURVE('E1088',#1555,#3607,#3605,.F.);
#3609=ORIENTED_EDGE('',*,*,#3608,.T.);
#3610=DIRECTION('',(0.,1.,0.));
#3611=VECTOR('',#3610,1.);
#3612=CARTESIAN_POINT('',(101.6,368.3,-25.4000000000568));
#3613=LINE('',#3612,#3611);
#3614=EDGE_CURVE('E920',#3607,#781,#3613,.T.);
#3615=ORIENTED_EDGE('',*,*,#3614,.T.);
#3616=ORIENTED_EDGE('',*,*,#782,.T.);
#3617=EDGE_LOOP('',(#3601,#3609,#3615,#3616));
#3618=FACE_BOUND('',#3617,.T.);
#3619=ADVANCED_FACE('F1170',(#3618),#3600,.F.);
#3620=CARTESIAN_POINT('',(181.6,368.3,-25.4000000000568));
#3621=DIRECTION('',(0.,0.,-1.));
#3622=DIRECTION('',(-1.,0.,0.));
#3623=AXIS2_PLACEMENT_3D('',#3620,#3621,#3622);
#3624=PLANE('',#3623);
#3625=DIRECTION('',(-1.,0.,0.));
#3626=VECTOR('',#3625,1.);
#3627=CARTESIAN_POINT('',(181.6,368.3,-25.4000000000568));
#3628=LINE('',#3627,#3626);
#3629=CARTESIAN_POINT('',(168.9,368.3,-25.4000000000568));
#3630=VERTEX_POINT('',#3629);
#3631=CARTESIAN_POINT('',(114.3,368.3,-25.4000000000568));
#3632=VERTEX_POINT('',#3631);
#3633=EDGE_CURVE('E910',#3630,#3632,#3628,.T.);
#3634=ORIENTED_EDGE('',*,*,#3633,.F.);
#3635=CARTESIAN_POINT('',(168.9,381.,-25.4000000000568));
#3636=DIRECTION('',(0.,0.,-1.));
#3637=DIRECTION('',(-1.,0.,0.));
#3638=AXIS2_PLACEMENT_3D('',#3635,#3636,#3637);
#3639=CIRCLE('',#3638,12.7);
#3640=CARTESIAN_POINT('',(181.6,381.,-25.4000000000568));
#3641=VERTEX_POINT('',#3640);
#3642=EDGE_CURVE('E4320',#3630,#3641,#3639,.F.);
#3643=ORIENTED_EDGE('',*,*,#3642,.T.);
#3644=DIRECTION('',(0.,1.,0.));
#3645=VECTOR('',#3644,1.);
#3646=CARTESIAN_POINT('',(181.6,368.3,-25.4000000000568));
#3647=LINE('',#3646,#3645);
#3648=EDGE_CURVE('E922',#3641,#789,#3647,.T.);
#3649=ORIENTED_EDGE('',*,*,#3648,.T.);
#3650=ORIENTED_EDGE('',*,*,#790,.T.);
#3651=ORIENTED_EDGE('',*,*,#3614,.F.);
#3652=CARTESIAN_POINT('',(114.3,381.,-25.4000000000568));
#3653=DIRECTION('',(0.,0.,-1.));
#3654=DIRECTION('',(-1.,0.,0.));
#3655=AXIS2_PLACEMENT_3D('',#3652,#3653,#3654);
#3656=CIRCLE('',#3655,12.7);
#3657=EDGE_CURVE('E1174',#3607,#3632,#3656,.F.);
#3658=ORIENTED_EDGE('',*,*,#3657,.T.);
#3659=EDGE_LOOP('',(#3634,#3643,#3649,#3650,#3651,#3658));
#3660=FACE_BOUND('',#3659,.T.);
#3661=ADVANCED_FACE('F1150',(#3660),#3624,.F.);
#3662=CARTESIAN_POINT('',(181.6,368.3,-5.6843418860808E-11));
#3663=DIRECTION('',(1.,0.,0.));
#3664=DIRECTION('',(0.,0.,-1.));
#3665=AXIS2_PLACEMENT_3D('',#3662,#3663,#3664);
#3666=PLANE('',#3665);
#3667=ORIENTED_EDGE('',*,*,#3648,.F.);
#3668=DIRECTION('',(0.,0.,-1.));
#3669=VECTOR('',#3668,1.);
#3670=CARTESIAN_POINT('',(181.6,381.,-5.6843418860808E-11));
#3671=LINE('',#3670,#3669);
#3672=EDGE_CURVE('E1510',#3641,#1615,#3671,.F.);
#3673=ORIENTED_EDGE('',*,*,#3672,.T.);
#3674=ORIENTED_EDGE('',*,*,#1616,.T.);
#3675=ORIENTED_EDGE('',*,*,#798,.T.);
#3676=EDGE_LOOP('',(#3667,#3673,#3674,#3675));
#3677=FACE_BOUND('',#3676,.T.);
#3678=ADVANCED_FACE('F1753',(#3677),#3666,.F.);
#3679=CARTESIAN_POINT('',(181.6,368.3,-5.6843418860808E-11));
#3680=DIRECTION('',(0.,1.,0.));
#3681=DIRECTION('',(0.,0.,1.));
#3682=AXIS2_PLACEMENT_3D('',#3679,#3680,#3681);
#3683=PLANE('',#3682);
#3684=ORIENTED_EDGE('',*,*,#1547,.T.);
#3685=DIRECTION('',(0.,0.,-1.));
#3686=VECTOR('',#3685,1.);
#3687=CARTESIAN_POINT('',(168.9,368.3,-5.6843418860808E-11));
#3688=LINE('',#3687,#3686);
#3689=EDGE_CURVE('E1175',#1546,#3630,#3688,.T.);
#3690=ORIENTED_EDGE('',*,*,#3689,.T.);
#3691=ORIENTED_EDGE('',*,*,#3633,.T.);
#3692=DIRECTION('',(0.,0.,1.));
#3693=VECTOR('',#3692,1.);
#3694=CARTESIAN_POINT('',(114.3,368.3,-5.6843418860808E-11));
#3695=LINE('',#3694,#3693);
#3696=EDGE_CURVE('E1080',#3632,#1544,#3695,.T.);
#3697=ORIENTED_EDGE('',*,*,#3696,.T.);
#3698=EDGE_LOOP('',(#3684,#3690,#3691,#3697));
#3699=FACE_BOUND('',#3698,.T.);
#3700=ADVANCED_FACE('F1691',(#3699),#3683,.T.);
#3701=CARTESIAN_POINT('',(0.,19.05,-19.05));
#3702=DIRECTION('',(-1.,0.,0.));
#3703=DIRECTION('',(0.,0.,1.));
#3704=AXIS2_PLACEMENT_3D('',#3701,#3702,#3703);
#3705=CONICAL_SURFACE('',#3704,6.35,0.1221730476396);
#3706=ORIENTED_EDGE('',*,*,#936,.T.);
#3707=DIRECTION('',(-0.992546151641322,0.,0.121869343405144));
#3708=VECTOR('',#3707,1.);
#3709=CARTESIAN_POINT('',(0.,19.05,-12.7));
#3710=LINE('',#3709,#3708);
#3711=CARTESIAN_POINT('',(15.7634365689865,19.05,-14.6355066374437));
#3712=VERTEX_POINT('',#3711);
#3713=EDGE_CURVE('E1099',#3712,#935,#3710,.T.);
#3714=ORIENTED_EDGE('',*,*,#3713,.F.);
#3715=CARTESIAN_POINT('',(15.7634365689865,19.05,-19.05));
#3716=DIRECTION('',(-1.,0.,0.));
#3717=DIRECTION('',(0.,0.,1.));
#3718=AXIS2_PLACEMENT_3D('',#3715,#3716,#3717);
#3719=CIRCLE('',#3718,4.41449336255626);
#3720=CARTESIAN_POINT('',(15.7634365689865,14.6355066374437,-19.05));
#3721=VERTEX_POINT('',#3720);
#3722=EDGE_CURVE('E1128',#3721,#3712,#3719,.T.);
#3723=ORIENTED_EDGE('',*,*,#3722,.F.);
#3724=DIRECTION('',(-0.992546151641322,-0.121869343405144,0.));
#3725=VECTOR('',#3724,1.);
#3726=CARTESIAN_POINT('',(0.,12.7,-19.05));
#3727=LINE('',#3726,#3725);
#3728=EDGE_CURVE('E1105',#3721,#933,#3727,.T.);
#3729=ORIENTED_EDGE('',*,*,#3728,.T.);
#3730=EDGE_LOOP('',(#3706,#3714,#3723,#3729));
#3731=FACE_BOUND('',#3730,.T.);
#3732=ADVANCED_FACE('F1687',(#3731),#3705,.F.);
#3733=CARTESIAN_POINT('',(0.,12.7,-107.95));
#3734=DIRECTION('',(0.121869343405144,-0.992546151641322,0.));
#3735=DIRECTION('',(0.992546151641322,0.121869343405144,0.));
#3736=AXIS2_PLACEMENT_3D('',#3733,#3734,#3735);
#3737=PLANE('',#3736);
#3738=ORIENTED_EDGE('',*,*,#944,.T.);
#3739=ORIENTED_EDGE('',*,*,#3728,.F.);
#3740=DIRECTION('',(0.,0.,1.));
#3741=VECTOR('',#3740,1.);
#3742=CARTESIAN_POINT('',(15.7634365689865,14.6355066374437,-19.05));
#3743=LINE('',#3742,#3741);
#3744=CARTESIAN_POINT('',(15.7634365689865,14.6355066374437,-107.95));
#3745=VERTEX_POINT('',#3744);
#3746=EDGE_CURVE('E1104',#3745,#3721,#3743,.T.);
#3747=ORIENTED_EDGE('',*,*,#3746,.F.);
#3748=DIRECTION('',(-0.992546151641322,-0.121869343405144,0.));
#3749=VECTOR('',#3748,1.);
#3750=CARTESIAN_POINT('',(0.,12.7,-107.95));
#3751=LINE('',#3750,#3749);
#3752=EDGE_CURVE('E3740',#3745,#943,#3751,.T.);
#3753=ORIENTED_EDGE('',*,*,#3752,.T.);
#3754=EDGE_LOOP('',(#3738,#3739,#3747,#3753));
#3755=FACE_BOUND('',#3754,.T.);
#3756=ADVANCED_FACE('F1690',(#3755),#3737,.F.);
#3757=CARTESIAN_POINT('',(0.,19.05,-107.95));
#3758=DIRECTION('',(-1.,0.,0.));
#3759=DIRECTION('',(0.,0.,1.));
#3760=AXIS2_PLACEMENT_3D('',#3757,#3758,#3759);
#3761=CONICAL_SURFACE('',#3760,6.35,0.1221730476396);
#3762=ORIENTED_EDGE('',*,*,#953,.T.);
#3763=ORIENTED_EDGE('',*,*,#3752,.F.);
#3764=CARTESIAN_POINT('',(15.7634365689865,19.05,-107.95));
#3765=DIRECTION('',(-1.,0.,0.));
#3766=DIRECTION('',(0.,0.,1.));
#3767=AXIS2_PLACEMENT_3D('',#3764,#3765,#3766);
#3768=CIRCLE('',#3767,4.41449336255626);
#3769=CARTESIAN_POINT('',(15.7634365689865,19.05,-112.364493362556));
#3770=VERTEX_POINT('',#3769);
#3771=EDGE_CURVE('E3746',#3770,#3745,#3768,.T.);
#3772=ORIENTED_EDGE('',*,*,#3771,.F.);
#3773=DIRECTION('',(-0.992546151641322,0.,-0.121869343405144));
#3774=VECTOR('',#3773,1.);
#3775=CARTESIAN_POINT('',(0.,19.05,-114.3));
#3776=LINE('',#3775,#3774);
#3777=EDGE_CURVE('E3754',#3770,#952,#3776,.T.);
#3778=ORIENTED_EDGE('',*,*,#3777,.T.);
#3779=EDGE_LOOP('',(#3762,#3763,#3772,#3778));
#3780=FACE_BOUND('',#3779,.T.);
#3781=ADVANCED_FACE('F1743',(#3780),#3761,.F.);
#3782=CARTESIAN_POINT('',(0.,82.55,-114.3));
#3783=DIRECTION('',(0.121869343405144,0.,-0.992546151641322));
#3784=DIRECTION('',(-0.992546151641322,0.,-0.121869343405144));
#3785=AXIS2_PLACEMENT_3D('',#3782,#3783,#3784);
#3786=PLANE('',#3785);
#3787=ORIENTED_EDGE('',*,*,#961,.T.);
#3788=ORIENTED_EDGE('',*,*,#3777,.F.);
#3789=DIRECTION('',(0.,-1.,0.));
#3790=VECTOR('',#3789,1.);
#3791=CARTESIAN_POINT('',(15.7634365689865,19.05,-112.364493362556));
#3792=LINE('',#3791,#3790);
#3793=CARTESIAN_POINT('',(15.7634365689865,82.55,-112.364493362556));
#3794=VERTEX_POINT('',#3793);
#3795=EDGE_CURVE('E3771',#3794,#3770,#3792,.T.);
#3796=ORIENTED_EDGE('',*,*,#3795,.F.);
#3797=DIRECTION('',(-0.992546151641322,0.,-0.121869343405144));
#3798=VECTOR('',#3797,1.);
#3799=CARTESIAN_POINT('',(0.,82.55,-114.3));
#3800=LINE('',#3799,#3798);
#3801=EDGE_CURVE('E3757',#3794,#960,#3800,.T.);
#3802=ORIENTED_EDGE('',*,*,#3801,.T.);
#3803=EDGE_LOOP('',(#3787,#3788,#3796,#3802));
#3804=FACE_BOUND('',#3803,.T.);
#3805=ADVANCED_FACE('F1739',(#3804),#3786,.F.);
#3806=CARTESIAN_POINT('',(0.,82.55,-107.95));
#3807=DIRECTION('',(-1.,0.,0.));
#3808=DIRECTION('',(0.,0.,1.));
#3809=AXIS2_PLACEMENT_3D('',#3806,#3807,#3808);
#3810=CONICAL_SURFACE('',#3809,6.35,0.1221730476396);
#3811=ORIENTED_EDGE('',*,*,#970,.T.);
#3812=ORIENTED_EDGE('',*,*,#3801,.F.);
#3813=CARTESIAN_POINT('',(15.7634365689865,82.55,-107.95));
#3814=DIRECTION('',(-1.,0.,0.));
#3815=DIRECTION('',(0.,0.,1.));
#3816=AXIS2_PLACEMENT_3D('',#3813,#3814,#3815);
#3817=CIRCLE('',#3816,4.41449336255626);
#3818=CARTESIAN_POINT('',(15.7634365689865,86.9644933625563,-107.95));
#3819=VERTEX_POINT('',#3818);
#3820=EDGE_CURVE('E3767',#3819,#3794,#3817,.T.);
#3821=ORIENTED_EDGE('',*,*,#3820,.F.);
#3822=DIRECTION('',(-0.992546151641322,0.121869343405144,0.));
#3823=VECTOR('',#3822,1.);
#3824=CARTESIAN_POINT('',(0.,88.9,-107.95));
#3825=LINE('',#3824,#3823);
#3826=EDGE_CURVE('E3760',#3819,#969,#3825,.T.);
#3827=ORIENTED_EDGE('',*,*,#3826,.T.);
#3828=EDGE_LOOP('',(#3811,#3812,#3821,#3827));
#3829=FACE_BOUND('',#3828,.T.);
#3830=ADVANCED_FACE('F1735',(#3829),#3810,.F.);
#3831=CARTESIAN_POINT('',(0.,88.9,-69.85));
#3832=DIRECTION('',(0.121869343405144,0.992546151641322,0.));
#3833=DIRECTION('',(-0.992546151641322,0.121869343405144,0.));
#3834=AXIS2_PLACEMENT_3D('',#3831,#3832,#3833);
#3835=PLANE('',#3834);
#3836=ORIENTED_EDGE('',*,*,#978,.T.);
#3837=ORIENTED_EDGE('',*,*,#3826,.F.);
#3838=DIRECTION('',(0.,0.,-1.));
#3839=VECTOR('',#3838,1.);
#3840=CARTESIAN_POINT('',(15.7634365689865,86.9644933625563,-19.05));
#3841=LINE('',#3840,#3839);
#3842=CARTESIAN_POINT('',(15.7634365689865,86.9644933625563,-69.85));
#3843=VERTEX_POINT('',#3842);
#3844=EDGE_CURVE('E3772',#3843,#3819,#3841,.T.);
#3845=ORIENTED_EDGE('',*,*,#3844,.F.);
#3846=DIRECTION('',(-0.992546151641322,0.121869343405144,0.));
#3847=VECTOR('',#3846,1.);
#3848=CARTESIAN_POINT('',(0.,88.9,-69.85));
#3849=LINE('',#3848,#3847);
#3850=EDGE_CURVE('E3783',#3843,#977,#3849,.T.);
#3851=ORIENTED_EDGE('',*,*,#3850,.T.);
#3852=EDGE_LOOP('',(#3836,#3837,#3845,#3851));
#3853=FACE_BOUND('',#3852,.T.);
#3854=ADVANCED_FACE('F1731',(#3853),#3835,.F.);
#3855=CARTESIAN_POINT('',(0.,95.25,-69.85));
#3856=DIRECTION('',(1.,0.,0.));
#3857=DIRECTION('',(0.,0.,-1.));
#3858=AXIS2_PLACEMENT_3D('',#3855,#3856,#3857);
#3859=CONICAL_SURFACE('',#3858,6.34999999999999,0.1221730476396);
#3860=ORIENTED_EDGE('',*,*,#987,.T.);
#3861=ORIENTED_EDGE('',*,*,#3850,.F.);
#3862=CARTESIAN_POINT('',(15.7634365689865,95.25,-69.85));
#3863=DIRECTION('',(-1.,0.,0.));
#3864=DIRECTION('',(0.,0.,1.));
#3865=AXIS2_PLACEMENT_3D('',#3862,#3863,#3864);
#3866=CIRCLE('',#3865,8.28550663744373);
#3867=CARTESIAN_POINT('',(15.7634365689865,95.25,-61.5644933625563));
#3868=VERTEX_POINT('',#3867);
#3869=EDGE_CURVE('E3777',#3868,#3843,#3866,.F.);
#3870=ORIENTED_EDGE('',*,*,#3869,.F.);
#3871=DIRECTION('',(-0.992546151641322,0.,-0.121869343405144));
#3872=VECTOR('',#3871,1.);
#3873=CARTESIAN_POINT('',(0.,95.25,-63.5));
#3874=LINE('',#3873,#3872);
#3875=EDGE_CURVE('E3785',#3868,#986,#3874,.T.);
#3876=ORIENTED_EDGE('',*,*,#3875,.T.);
#3877=EDGE_LOOP('',(#3860,#3861,#3870,#3876));
#3878=FACE_BOUND('',#3877,.T.);
#3879=ADVANCED_FACE('F1727',(#3878),#3859,.T.);
#3880=CARTESIAN_POINT('',(0.,323.85,-63.5));
#3881=DIRECTION('',(0.121869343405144,0.,-0.992546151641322));
#3882=DIRECTION('',(-0.992546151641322,0.,-0.121869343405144));
#3883=AXIS2_PLACEMENT_3D('',#3880,#3881,#3882);
#3884=PLANE('',#3883);
#3885=ORIENTED_EDGE('',*,*,#995,.T.);
#3886=ORIENTED_EDGE('',*,*,#3875,.F.);
#3887=DIRECTION('',(0.,-1.,0.));
#3888=VECTOR('',#3887,1.);
#3889=CARTESIAN_POINT('',(15.7634365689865,19.05,-61.5644933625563));
#3890=LINE('',#3889,#3888);
#3891=CARTESIAN_POINT('',(15.7634365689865,323.85,-61.5644933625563));
#3892=VERTEX_POINT('',#3891);
#3893=EDGE_CURVE('E3837',#3892,#3868,#3890,.T.);
#3894=ORIENTED_EDGE('',*,*,#3893,.F.);
#3895=DIRECTION('',(-0.992546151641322,0.,-0.121869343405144));
#3896=VECTOR('',#3895,1.);
#3897=CARTESIAN_POINT('',(0.,323.85,-63.5));
#3898=LINE('',#3897,#3896);
#3899=EDGE_CURVE('E3788',#3892,#994,#3898,.T.);
#3900=ORIENTED_EDGE('',*,*,#3899,.T.);
#3901=EDGE_LOOP('',(#3885,#3886,#3894,#3900));
#3902=FACE_BOUND('',#3901,.T.);
#3903=ADVANCED_FACE('F1723',(#3902),#3884,.F.);
#3904=CARTESIAN_POINT('',(0.,323.85,-69.85));
#3905=DIRECTION('',(1.,0.,0.));
#3906=DIRECTION('',(0.,0.,-1.));
#3907=AXIS2_PLACEMENT_3D('',#3904,#3905,#3906);
#3908=CONICAL_SURFACE('',#3907,6.34999999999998,0.1221730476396);
#3909=ORIENTED_EDGE('',*,*,#1004,.T.);
#3910=ORIENTED_EDGE('',*,*,#3899,.F.);
#3911=CARTESIAN_POINT('',(15.7634365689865,323.85,-69.85));
#3912=DIRECTION('',(-1.,0.,0.));
#3913=DIRECTION('',(0.,0.,1.));
#3914=AXIS2_PLACEMENT_3D('',#3911,#3912,#3913);
#3915=CIRCLE('',#3914,8.28550663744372);
#3916=CARTESIAN_POINT('',(15.7634365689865,332.135506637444,-69.85));
#3917=VERTEX_POINT('',#3916);
#3918=EDGE_CURVE('E3805',#3917,#3892,#3915,.F.);
#3919=ORIENTED_EDGE('',*,*,#3918,.F.);
#3920=DIRECTION('',(-0.992546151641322,-0.121869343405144,0.));
#3921=VECTOR('',#3920,1.);
#3922=CARTESIAN_POINT('',(0.,330.2,-69.85));
#3923=LINE('',#3922,#3921);
#3924=EDGE_CURVE('E3791',#3917,#1003,#3923,.T.);
#3925=ORIENTED_EDGE('',*,*,#3924,.T.);
#3926=EDGE_LOOP('',(#3909,#3910,#3919,#3925));
#3927=FACE_BOUND('',#3926,.T.);
#3928=ADVANCED_FACE('F1719',(#3927),#3908,.T.);
#3929=CARTESIAN_POINT('',(0.,330.2,-107.95));
#3930=DIRECTION('',(0.121869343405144,-0.992546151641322,0.));
#3931=DIRECTION('',(0.992546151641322,0.121869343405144,0.));
#3932=AXIS2_PLACEMENT_3D('',#3929,#3930,#3931);
#3933=PLANE('',#3932);
#3934=ORIENTED_EDGE('',*,*,#1012,.T.);
#3935=ORIENTED_EDGE('',*,*,#3924,.F.);
#3936=DIRECTION('',(0.,0.,1.));
#3937=VECTOR('',#3936,1.);
#3938=CARTESIAN_POINT('',(15.7634365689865,332.135506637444,-19.05));
#3939=LINE('',#3938,#3937);
#3940=CARTESIAN_POINT('',(15.7634365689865,332.135506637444,-107.95));
#3941=VERTEX_POINT('',#3940);
#3942=EDGE_CURVE('E3800',#3941,#3917,#3939,.T.);
#3943=ORIENTED_EDGE('',*,*,#3942,.F.);
#3944=DIRECTION('',(-0.992546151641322,-0.121869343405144,0.));
#3945=VECTOR('',#3944,1.);
#3946=CARTESIAN_POINT('',(0.,330.2,-107.95));
#3947=LINE('',#3946,#3945);
#3948=EDGE_CURVE('E3819',#3941,#1011,#3947,.T.);
#3949=ORIENTED_EDGE('',*,*,#3948,.T.);
#3950=EDGE_LOOP('',(#3934,#3935,#3943,#3949));
#3951=FACE_BOUND('',#3950,.T.);
#3952=ADVANCED_FACE('F1715',(#3951),#3933,.F.);
#3953=CARTESIAN_POINT('',(0.,336.55,-107.95));
#3954=DIRECTION('',(-1.,0.,0.));
#3955=DIRECTION('',(0.,0.,1.));
#3956=AXIS2_PLACEMENT_3D('',#3953,#3954,#3955);
#3957=CONICAL_SURFACE('',#3956,6.35000000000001,0.1221730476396);
#3958=ORIENTED_EDGE('',*,*,#1021,.T.);
#3959=ORIENTED_EDGE('',*,*,#3948,.F.);
#3960=CARTESIAN_POINT('',(15.7634365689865,336.55,-107.95));
#3961=DIRECTION('',(-1.,0.,0.));
#3962=DIRECTION('',(0.,0.,1.));
#3963=AXIS2_PLACEMENT_3D('',#3960,#3961,#3962);
#3964=CIRCLE('',#3963,4.41449336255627);
#3965=CARTESIAN_POINT('',(15.7634365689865,336.55,-112.364493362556));
#3966=VERTEX_POINT('',#3965);
#3967=EDGE_CURVE('E3806',#3966,#3941,#3964,.T.);
#3968=ORIENTED_EDGE('',*,*,#3967,.F.);
#3969=DIRECTION('',(-0.992546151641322,0.,-0.121869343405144));
#3970=VECTOR('',#3969,1.);
#3971=CARTESIAN_POINT('',(0.,336.55,-114.3));
#3972=LINE('',#3971,#3970);
#3973=EDGE_CURVE('E3816',#3966,#1020,#3972,.T.);
#3974=ORIENTED_EDGE('',*,*,#3973,.T.);
#3975=EDGE_LOOP('',(#3958,#3959,#3968,#3974));
#3976=FACE_BOUND('',#3975,.T.);
#3977=ADVANCED_FACE('F1711',(#3976),#3957,.F.);
#3978=CARTESIAN_POINT('',(0.,387.35,-114.3));
#3979=DIRECTION('',(0.121869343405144,0.,-0.992546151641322));
#3980=DIRECTION('',(-0.992546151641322,0.,-0.121869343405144));
#3981=AXIS2_PLACEMENT_3D('',#3978,#3979,#3980);
#3982=PLANE('',#3981);
#3983=ORIENTED_EDGE('',*,*,#1029,.T.);
#3984=ORIENTED_EDGE('',*,*,#3973,.F.);
#3985=DIRECTION('',(0.,-1.,0.));
#3986=VECTOR('',#3985,1.);
#3987=CARTESIAN_POINT('',(15.7634365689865,19.05,-112.364493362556));
#3988=LINE('',#3987,#3986);
#3989=CARTESIAN_POINT('',(15.7634365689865,387.35,-112.364493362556));
#3990=VERTEX_POINT('',#3989);
#3991=EDGE_CURVE('E3810',#3990,#3966,#3988,.T.);
#3992=ORIENTED_EDGE('',*,*,#3991,.F.);
#3993=DIRECTION('',(-0.992546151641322,0.,-0.121869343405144));
#3994=VECTOR('',#3993,1.);
#3995=CARTESIAN_POINT('',(0.,387.35,-114.3));
#3996=LINE('',#3995,#3994);
#3997=EDGE_CURVE('E3820',#3990,#1028,#3996,.T.);
#3998=ORIENTED_EDGE('',*,*,#3997,.T.);
#3999=EDGE_LOOP('',(#3983,#3984,#3992,#3998));
#4000=FACE_BOUND('',#3999,.T.);
#4001=ADVANCED_FACE('F1707',(#4000),#3982,.F.);
#4002=CARTESIAN_POINT('',(0.,387.35,-107.95));
#4003=DIRECTION('',(-1.,0.,0.));
#4004=DIRECTION('',(0.,0.,1.));
#4005=AXIS2_PLACEMENT_3D('',#4002,#4003,#4004);
#4006=CONICAL_SURFACE('',#4005,6.34999999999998,0.1221730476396);
#4007=ORIENTED_EDGE('',*,*,#1038,.T.);
#4008=ORIENTED_EDGE('',*,*,#3997,.F.);
#4009=CARTESIAN_POINT('',(15.7634365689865,387.35,-107.95));
#4010=DIRECTION('',(-1.,0.,0.));
#4011=DIRECTION('',(0.,0.,1.));
#4012=AXIS2_PLACEMENT_3D('',#4009,#4010,#4011);
#4013=CIRCLE('',#4012,4.41449336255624);
#4014=CARTESIAN_POINT('',(15.7634365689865,391.764493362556,-107.95));
#4015=VERTEX_POINT('',#4014);
#4016=EDGE_CURVE('E3849',#4015,#3990,#4013,.T.);
#4017=ORIENTED_EDGE('',*,*,#4016,.F.);
#4018=DIRECTION('',(-0.992546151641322,0.121869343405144,0.));
#4019=VECTOR('',#4018,1.);
#4020=CARTESIAN_POINT('',(0.,393.7,-107.95));
#4021=LINE('',#4020,#4019);
#4022=EDGE_CURVE('E3848',#4015,#1037,#4021,.T.);
#4023=ORIENTED_EDGE('',*,*,#4022,.T.);
#4024=EDGE_LOOP('',(#4007,#4008,#4017,#4023));
#4025=FACE_BOUND('',#4024,.T.);
#4026=ADVANCED_FACE('F1703',(#4025),#4006,.F.);
#4027=CARTESIAN_POINT('',(0.,393.7,-19.05));
#4028=DIRECTION('',(0.121869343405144,0.992546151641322,0.));
#4029=DIRECTION('',(-0.992546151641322,0.121869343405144,0.));
#4030=AXIS2_PLACEMENT_3D('',#4027,#4028,#4029);
#4031=PLANE('',#4030);
#4032=ORIENTED_EDGE('',*,*,#1046,.T.);
#4033=ORIENTED_EDGE('',*,*,#4022,.F.);
#4034=DIRECTION('',(0.,0.,-1.));
#4035=VECTOR('',#4034,1.);
#4036=CARTESIAN_POINT('',(15.7634365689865,391.764493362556,-19.05));
#4037=LINE('',#4036,#4035);
#4038=CARTESIAN_POINT('',(15.7634365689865,391.764493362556,-19.05));
#4039=VERTEX_POINT('',#4038);
#4040=EDGE_CURVE('E1121',#4039,#4015,#4037,.T.);
#4041=ORIENTED_EDGE('',*,*,#4040,.F.);
#4042=DIRECTION('',(-0.992546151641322,0.121869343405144,0.));
#4043=VECTOR('',#4042,1.);
#4044=CARTESIAN_POINT('',(0.,393.7,-19.05));
#4045=LINE('',#4044,#4043);
#4046=EDGE_CURVE('E1110',#4039,#1045,#4045,.T.);
#4047=ORIENTED_EDGE('',*,*,#4046,.T.);
#4048=EDGE_LOOP('',(#4032,#4033,#4041,#4047));
#4049=FACE_BOUND('',#4048,.T.);
#4050=ADVANCED_FACE('F1699',(#4049),#4031,.F.);
#4051=CARTESIAN_POINT('',(0.,387.35,-19.05));
#4052=DIRECTION('',(-1.,0.,0.));
#4053=DIRECTION('',(0.,0.,1.));
#4054=AXIS2_PLACEMENT_3D('',#4051,#4052,#4053);
#4055=CONICAL_SURFACE('',#4054,6.34999999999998,0.1221730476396);
#4056=ORIENTED_EDGE('',*,*,#1055,.T.);
#4057=ORIENTED_EDGE('',*,*,#4046,.F.);
#4058=CARTESIAN_POINT('',(15.7634365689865,387.35,-19.05));
#4059=DIRECTION('',(-1.,0.,0.));
#4060=DIRECTION('',(0.,0.,1.));
#4061=AXIS2_PLACEMENT_3D('',#4058,#4059,#4060);
#4062=CIRCLE('',#4061,4.41449336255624);
#4063=CARTESIAN_POINT('',(15.7634365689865,387.35,-14.6355066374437));
#4064=VERTEX_POINT('',#4063);
#4065=EDGE_CURVE('E1117',#4064,#4039,#4062,.T.);
#4066=ORIENTED_EDGE('',*,*,#4065,.F.);
#4067=DIRECTION('',(-0.992546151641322,0.,0.121869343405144));
#4068=VECTOR('',#4067,1.);
#4069=CARTESIAN_POINT('',(0.,387.35,-12.7));
#4070=LINE('',#4069,#4068);
#4071=EDGE_CURVE('E1103',#4064,#1054,#4070,.T.);
#4072=ORIENTED_EDGE('',*,*,#4071,.T.);
#4073=EDGE_LOOP('',(#4056,#4057,#4066,#4072));
#4074=FACE_BOUND('',#4073,.T.);
#4075=ADVANCED_FACE('F1695',(#4074),#4055,.F.);
#4076=CARTESIAN_POINT('',(0.,19.05,-12.7));
#4077=DIRECTION('',(0.121869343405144,0.,0.992546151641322));
#4078=DIRECTION('',(0.992546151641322,0.,-0.121869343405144));
#4079=AXIS2_PLACEMENT_3D('',#4076,#4077,#4078);
#4080=PLANE('',#4079);
#4081=ORIENTED_EDGE('',*,*,#1061,.T.);
#4082=ORIENTED_EDGE('',*,*,#4071,.F.);
#4083=DIRECTION('',(0.,1.,0.));
#4084=VECTOR('',#4083,1.);
#4085=CARTESIAN_POINT('',(15.7634365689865,19.05,-14.6355066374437));
#4086=LINE('',#4085,#4084);
#4087=EDGE_CURVE('E1122',#3712,#4064,#4086,.T.);
#4088=ORIENTED_EDGE('',*,*,#4087,.F.);
#4089=ORIENTED_EDGE('',*,*,#3713,.T.);
#4090=EDGE_LOOP('',(#4081,#4082,#4088,#4089));
#4091=FACE_BOUND('',#4090,.T.);
#4092=ADVANCED_FACE('F1685',(#4091),#4080,.F.);
#4093=CARTESIAN_POINT('',(15.7634365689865,19.05,-19.05));
#4094=DIRECTION('',(-1.,0.,0.));
#4095=DIRECTION('',(0.,0.,1.));
#4096=AXIS2_PLACEMENT_3D('',#4093,#4094,#4095);
#4097=PLANE('',#4096);
#4098=ORIENTED_EDGE('',*,*,#3722,.T.);
#4099=ORIENTED_EDGE('',*,*,#4087,.T.);
#4100=ORIENTED_EDGE('',*,*,#4065,.T.);
#4101=ORIENTED_EDGE('',*,*,#4040,.T.);
#4102=ORIENTED_EDGE('',*,*,#4016,.T.);
#4103=ORIENTED_EDGE('',*,*,#3991,.T.);
#4104=ORIENTED_EDGE('',*,*,#3967,.T.);
#4105=ORIENTED_EDGE('',*,*,#3942,.T.);
#4106=ORIENTED_EDGE('',*,*,#3918,.T.);
#4107=ORIENTED_EDGE('',*,*,#3893,.T.);
#4108=ORIENTED_EDGE('',*,*,#3869,.T.);
#4109=ORIENTED_EDGE('',*,*,#3844,.T.);
#4110=ORIENTED_EDGE('',*,*,#3820,.T.);
#4111=ORIENTED_EDGE('',*,*,#3795,.T.);
#4112=ORIENTED_EDGE('',*,*,#3771,.T.);
#4113=ORIENTED_EDGE('',*,*,#3746,.T.);
#4114=EDGE_LOOP('',(#4098,#4099,#4100,#4101,#4102,#4103,#4104,#4105,#4106,#4107,#4108,#4109,
#4110,#4111,#4112,#4113));
#4115=FACE_BOUND('',#4114,.T.);
#4116=ADVANCED_FACE('F1682',(#4115),#4097,.T.);
#4117=CARTESIAN_POINT('',(533.4,12.7,-38.0999999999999));
#4118=DIRECTION('',(0.,0.,1.));
#4119=DIRECTION('',(1.,0.,0.));
#4120=AXIS2_PLACEMENT_3D('',#4117,#4118,#4119);
#4121=PLANE('',#4120);
#4122=DIRECTION('',(-1.,0.,0.));
#4123=VECTOR('',#4122,1.);
#4124=CARTESIAN_POINT('',(533.4,12.7,-38.0999999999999));
#4125=LINE('',#4124,#4123);
#4126=CARTESIAN_POINT('',(520.7,12.7,-38.0999999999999));
#4127=VERTEX_POINT('',#4126);
#4128=CARTESIAN_POINT('',(38.1,12.7,-38.1));
#4129=VERTEX_POINT('',#4128);
#4130=EDGE_CURVE('E1068',#4127,#4129,#4125,.T.);
#4131=ORIENTED_EDGE('',*,*,#4130,.F.);
#4132=DIRECTION('',(0.,-1.,0.));
#4133=VECTOR('',#4132,1.);
#4134=CARTESIAN_POINT('',(520.7,12.7,-38.0999999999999));
#4135=LINE('',#4134,#4133);
#4136=EDGE_CURVE('E1003',#4127,#1214,#4135,.T.);
#4137=ORIENTED_EDGE('',*,*,#4136,.T.);
#4138=ORIENTED_EDGE('',*,*,#1217,.T.);
#4139=DIRECTION('',(0.,-1.,0.));
#4140=VECTOR('',#4139,1.);
#4141=CARTESIAN_POINT('',(38.1,12.7,-38.1));
#4142=LINE('',#4141,#4140);
#4143=EDGE_CURVE('E1000',#1216,#4129,#4142,.F.);
#4144=ORIENTED_EDGE('',*,*,#4143,.T.);
#4145=EDGE_LOOP('',(#4131,#4137,#4138,#4144));
#4146=FACE_BOUND('',#4145,.T.);
#4147=ADVANCED_FACE('F998',(#4146),#4121,.F.);
#4148=CARTESIAN_POINT('',(533.4,12.7,-101.6));
#4149=DIRECTION('',(1.,0.,0.));
#4150=DIRECTION('',(0.,0.,-1.));
#4151=AXIS2_PLACEMENT_3D('',#4148,#4149,#4150);
#4152=PLANE('',#4151);
#4153=DIRECTION('',(0.,0.,1.));
#4154=VECTOR('',#4153,1.);
#4155=CARTESIAN_POINT('',(533.4,12.7,-101.6));
#4156=LINE('',#4155,#4154);
#4157=CARTESIAN_POINT('',(533.4,12.7,-88.9));
#4158=VERTEX_POINT('',#4157);
#4159=CARTESIAN_POINT('',(533.4,12.7,-50.7999999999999));
#4160=VERTEX_POINT('',#4159);
#4161=EDGE_CURVE('E935',#4158,#4160,#4156,.T.);
#4162=ORIENTED_EDGE('',*,*,#4161,.F.);
#4163=DIRECTION('',(0.,-1.,0.));
#4164=VECTOR('',#4163,1.);
#4165=CARTESIAN_POINT('',(533.4,12.7,-88.9));
#4166=LINE('',#4165,#4164);
#4167=EDGE_CURVE('E1033',#4158,#1233,#4166,.T.);
#4168=ORIENTED_EDGE('',*,*,#4167,.T.);
#4169=ORIENTED_EDGE('',*,*,#1234,.T.);
#4170=DIRECTION('',(0.,-1.,0.));
#4171=VECTOR('',#4170,1.);
#4172=CARTESIAN_POINT('',(533.4,12.7,-50.7999999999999));
#4173=LINE('',#4172,#4171);
#4174=EDGE_CURVE('E1022',#1225,#4160,#4173,.F.);
#4175=ORIENTED_EDGE('',*,*,#4174,.T.);
#4176=EDGE_LOOP('',(#4162,#4168,#4169,#4175));
#4177=FACE_BOUND('',#4176,.T.);
#4178=ADVANCED_FACE('F1074',(#4177),#4152,.F.);
#4179=CARTESIAN_POINT('',(25.4,12.7,-101.6));
#4180=DIRECTION('',(0.,0.,-1.));
#4181=DIRECTION('',(-1.,0.,0.));
#4182=AXIS2_PLACEMENT_3D('',#4179,#4180,#4181);
#4183=PLANE('',#4182);
#4184=DIRECTION('',(1.,0.,0.));
#4185=VECTOR('',#4184,1.);
#4186=CARTESIAN_POINT('',(25.4,12.7,-101.6));
#4187=LINE('',#4186,#4185);
#4188=CARTESIAN_POINT('',(38.1,12.7,-101.6));
#4189=VERTEX_POINT('',#4188);
#4190=CARTESIAN_POINT('',(520.7,12.7,-101.6));
#4191=VERTEX_POINT('',#4190);
#4192=EDGE_CURVE('E931',#4189,#4191,#4187,.T.);
#4193=ORIENTED_EDGE('',*,*,#4192,.F.);
#4194=DIRECTION('',(0.,-1.,0.));
#4195=VECTOR('',#4194,1.);
#4196=CARTESIAN_POINT('',(38.1,12.7,-101.6));
#4197=LINE('',#4196,#4195);
#4198=EDGE_CURVE('E1047',#4189,#1250,#4197,.T.);
#4199=ORIENTED_EDGE('',*,*,#4198,.T.);
#4200=ORIENTED_EDGE('',*,*,#1251,.T.);
#4201=DIRECTION('',(0.,-1.,0.));
#4202=VECTOR('',#4201,1.);
#4203=CARTESIAN_POINT('',(520.7,12.7,-101.6));
#4204=LINE('',#4203,#4202);
#4205=EDGE_CURVE('E1038',#1242,#4191,#4204,.F.);
#4206=ORIENTED_EDGE('',*,*,#4205,.T.);
#4207=EDGE_LOOP('',(#4193,#4199,#4200,#4206));
#4208=FACE_BOUND('',#4207,.T.);
#4209=ADVANCED_FACE('F1062',(#4208),#4183,.F.);
#4210=CARTESIAN_POINT('',(25.4,12.7,-38.1));
#4211=DIRECTION('',(-1.,0.,0.));
#4212=DIRECTION('',(0.,0.,1.));
#4213=AXIS2_PLACEMENT_3D('',#4210,#4211,#4212);
#4214=PLANE('',#4213);
#4215=ORIENTED_EDGE('',*,*,#1268,.T.);
#4216=DIRECTION('',(0.,-1.,0.));
#4217=VECTOR('',#4216,1.);
#4218=CARTESIAN_POINT('',(25.4,12.7,-88.9));
#4219=LINE('',#4218,#4217);
#4220=CARTESIAN_POINT('',(25.4,12.7,-88.9));
#4221=VERTEX_POINT('',#4220);
#4222=EDGE_CURVE('E1051',#1259,#4221,#4219,.F.);
#4223=ORIENTED_EDGE('',*,*,#4222,.T.);
#4224=DIRECTION('',(0.,0.,-1.));
#4225=VECTOR('',#4224,1.);
#4226=CARTESIAN_POINT('',(25.4,12.7,-38.1));
#4227=LINE('',#4226,#4225);
#4228=CARTESIAN_POINT('',(25.4,12.7,-50.8));
#4229=VERTEX_POINT('',#4228);
#4230=EDGE_CURVE('E936',#4229,#4221,#4227,.T.);
#4231=ORIENTED_EDGE('',*,*,#4230,.F.);
#4232=DIRECTION('',(0.,-1.,0.));
#4233=VECTOR('',#4232,1.);
#4234=CARTESIAN_POINT('',(25.4,12.7,-50.8));
#4235=LINE('',#4234,#4233);
#4236=EDGE_CURVE('E1012',#4229,#1267,#4235,.T.);
#4237=ORIENTED_EDGE('',*,*,#4236,.T.);
#4238=EDGE_LOOP('',(#4215,#4223,#4231,#4237));
#4239=FACE_BOUND('',#4238,.T.);
#4240=ADVANCED_FACE('F1067',(#4239),#4214,.F.);
#4241=CARTESIAN_POINT('',(533.4,12.7,-38.0999999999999));
#4242=DIRECTION('',(0.,1.,0.));
#4243=DIRECTION('',(0.,0.,1.));
#4244=AXIS2_PLACEMENT_3D('',#4241,#4242,#4243);
#4245=PLANE('',#4244);
#4246=ORIENTED_EDGE('',*,*,#4230,.T.);
#4247=CARTESIAN_POINT('',(38.1,12.7,-88.9));
#4248=DIRECTION('',(0.,1.,0.));
#4249=DIRECTION('',(0.,0.,1.));
#4250=AXIS2_PLACEMENT_3D('',#4247,#4248,#4249);
#4251=CIRCLE('',#4250,12.7);
#4252=EDGE_CURVE('E47',#4221,#4189,#4251,.F.);
#4253=ORIENTED_EDGE('',*,*,#4252,.T.);
#4254=ORIENTED_EDGE('',*,*,#4192,.T.);
#4255=CARTESIAN_POINT('',(520.7,12.7,-88.9));
#4256=DIRECTION('',(0.,1.,0.));
#4257=DIRECTION('',(0.,0.,1.));
#4258=AXIS2_PLACEMENT_3D('',#4255,#4256,#4257);
#4259=CIRCLE('',#4258,12.7);
#4260=EDGE_CURVE('E1043',#4191,#4158,#4259,.F.);
#4261=ORIENTED_EDGE('',*,*,#4260,.T.);
#4262=ORIENTED_EDGE('',*,*,#4161,.T.);
#4263=CARTESIAN_POINT('',(520.7,12.7,-50.7999999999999));
#4264=DIRECTION('',(0.,1.,0.));
#4265=DIRECTION('',(0.,0.,1.));
#4266=AXIS2_PLACEMENT_3D('',#4263,#4264,#4265);
#4267=CIRCLE('',#4266,12.7);
#4268=EDGE_CURVE('E1081',#4160,#4127,#4267,.F.);
#4269=ORIENTED_EDGE('',*,*,#4268,.T.);
#4270=ORIENTED_EDGE('',*,*,#4130,.T.);
#4271=CARTESIAN_POINT('',(38.1,12.7,-50.8));
#4272=DIRECTION('',(0.,1.,0.));
#4273=DIRECTION('',(0.,0.,1.));
#4274=AXIS2_PLACEMENT_3D('',#4271,#4272,#4273);
#4275=CIRCLE('',#4274,12.7);
#4276=EDGE_CURVE('E1009',#4129,#4229,#4275,.F.);
#4277=ORIENTED_EDGE('',*,*,#4276,.T.);
#4278=EDGE_LOOP('',(#4246,#4253,#4254,#4261,#4262,#4269,#4270,#4277));
#4279=FACE_BOUND('',#4278,.T.);
#4280=ADVANCED_FACE('F1056',(#4279),#4245,.F.);
#4281=CARTESIAN_POINT('',(25.4,393.7,-101.6));
#4282=DIRECTION('',(-1.,0.,0.));
#4283=DIRECTION('',(0.,0.,1.));
#4284=AXIS2_PLACEMENT_3D('',#4281,#4282,#4283);
#4285=PLANE('',#4284);
#4286=DIRECTION('',(0.,0.,1.));
#4287=VECTOR('',#4286,1.);
#4288=CARTESIAN_POINT('',(25.4,393.7,-101.6));
#4289=LINE('',#4288,#4287);
#4290=CARTESIAN_POINT('',(25.4,393.7,-88.9));
#4291=VERTEX_POINT('',#4290);
#4292=CARTESIAN_POINT('',(25.4,393.7,-50.8));
#4293=VERTEX_POINT('',#4292);
#4294=EDGE_CURVE('E972',#4291,#4293,#4289,.T.);
#4295=ORIENTED_EDGE('',*,*,#4294,.F.);
#4296=DIRECTION('',(0.,1.,0.));
#4297=VECTOR('',#4296,1.);
#4298=CARTESIAN_POINT('',(25.4,393.7,-88.9));
#4299=LINE('',#4298,#4297);
#4300=EDGE_CURVE('E1560',#4291,#856,#4299,.T.);
#4301=ORIENTED_EDGE('',*,*,#4300,.T.);
#4302=ORIENTED_EDGE('',*,*,#859,.T.);
#4303=DIRECTION('',(0.,1.,0.));
#4304=VECTOR('',#4303,1.);
#4305=CARTESIAN_POINT('',(25.4,393.7,-50.8));
#4306=LINE('',#4305,#4304);
#4307=EDGE_CURVE('E1558',#858,#4293,#4306,.F.);
#4308=ORIENTED_EDGE('',*,*,#4307,.T.);
#4309=EDGE_LOOP('',(#4295,#4301,#4302,#4308));
#4310=FACE_BOUND('',#4309,.T.);
#4311=ADVANCED_FACE('F1579',(#4310),#4285,.F.);
#4312=CARTESIAN_POINT('',(533.4,393.7,-101.6));
#4313=DIRECTION('',(0.,0.,-1.));
#4314=DIRECTION('',(-1.,0.,0.));
#4315=AXIS2_PLACEMENT_3D('',#4312,#4313,#4314);
#4316=PLANE('',#4315);
#4317=ORIENTED_EDGE('',*,*,#876,.T.);
#4318=DIRECTION('',(0.,1.,0.));
#4319=VECTOR('',#4318,1.);
#4320=CARTESIAN_POINT('',(38.1,393.7,-101.6));
#4321=LINE('',#4320,#4319);
#4322=CARTESIAN_POINT('',(38.1,393.7,-101.6));
#4323=VERTEX_POINT('',#4322);
#4324=EDGE_CURVE('E1564',#867,#4323,#4321,.F.);
#4325=ORIENTED_EDGE('',*,*,#4324,.T.);
#4326=DIRECTION('',(-1.,0.,0.));
#4327=VECTOR('',#4326,1.);
#4328=CARTESIAN_POINT('',(533.4,393.7,-101.6));
#4329=LINE('',#4328,#4327);
#4330=CARTESIAN_POINT('',(520.7,393.7,-101.6));
#4331=VERTEX_POINT('',#4330);
#4332=EDGE_CURVE('E986',#4331,#4323,#4329,.T.);
#4333=ORIENTED_EDGE('',*,*,#4332,.F.);
#4334=DIRECTION('',(0.,1.,0.));
#4335=VECTOR('',#4334,1.);
#4336=CARTESIAN_POINT('',(520.7,393.7,-101.6));
#4337=LINE('',#4336,#4335);
#4338=EDGE_CURVE('E1509',#4331,#875,#4337,.T.);
#4339=ORIENTED_EDGE('',*,*,#4338,.T.);
#4340=EDGE_LOOP('',(#4317,#4325,#4333,#4339));
#4341=FACE_BOUND('',#4340,.T.);
#4342=ADVANCED_FACE('F1575',(#4341),#4316,.F.);
#4343=CARTESIAN_POINT('',(533.4,393.7,-38.1));
#4344=DIRECTION('',(1.,0.,0.));
#4345=DIRECTION('',(0.,0.,-1.));
#4346=AXIS2_PLACEMENT_3D('',#4343,#4344,#4345);
#4347=PLANE('',#4346);
#4348=DIRECTION('',(0.,0.,-1.));
#4349=VECTOR('',#4348,1.);
#4350=CARTESIAN_POINT('',(533.4,393.7,-38.1));
#4351=LINE('',#4350,#4349);
#4352=CARTESIAN_POINT('',(533.4,393.7,-50.8));
#4353=VERTEX_POINT('',#4352);
#4354=CARTESIAN_POINT('',(533.4,393.7,-88.9));
#4355=VERTEX_POINT('',#4354);
#4356=EDGE_CURVE('E984',#4353,#4355,#4351,.T.);
#4357=ORIENTED_EDGE('',*,*,#4356,.F.);
#4358=DIRECTION('',(0.,1.,0.));
#4359=VECTOR('',#4358,1.);
#4360=CARTESIAN_POINT('',(533.4,393.7,-50.8));
#4361=LINE('',#4360,#4359);
#4362=EDGE_CURVE('E1534',#4353,#892,#4361,.T.);
#4363=ORIENTED_EDGE('',*,*,#4362,.T.);
#4364=ORIENTED_EDGE('',*,*,#893,.T.);
#4365=DIRECTION('',(0.,1.,0.));
#4366=VECTOR('',#4365,1.);
#4367=CARTESIAN_POINT('',(533.4,393.7,-88.9));
#4368=LINE('',#4367,#4366);
#4369=EDGE_CURVE('E1514',#884,#4355,#4368,.F.);
#4370=ORIENTED_EDGE('',*,*,#4369,.T.);
#4371=EDGE_LOOP('',(#4357,#4363,#4364,#4370));
#4372=FACE_BOUND('',#4371,.T.);
#4373=ADVANCED_FACE('F1605',(#4372),#4347,.F.);
#4374=CARTESIAN_POINT('',(25.4,393.7,-38.1));
#4375=DIRECTION('',(0.,0.,1.));
#4376=DIRECTION('',(1.,0.,0.));
#4377=AXIS2_PLACEMENT_3D('',#4374,#4375,#4376);
#4378=PLANE('',#4377);
#4379=DIRECTION('',(1.,0.,0.));
#4380=VECTOR('',#4379,1.);
#4381=CARTESIAN_POINT('',(25.4,393.7,-38.1));
#4382=LINE('',#4381,#4380);
#4383=CARTESIAN_POINT('',(38.1,393.7,-38.1));
#4384=VERTEX_POINT('',#4383);
#4385=CARTESIAN_POINT('',(520.7,393.7,-38.1));
#4386=VERTEX_POINT('',#4385);
#4387=EDGE_CURVE('E978',#4384,#4386,#4382,.T.);
#4388=ORIENTED_EDGE('',*,*,#4387,.F.);
#4389=DIRECTION('',(0.,1.,0.));
#4390=VECTOR('',#4389,1.);
#4391=CARTESIAN_POINT('',(38.1,393.7,-38.1));
#4392=LINE('',#4391,#4390);
#4393=EDGE_CURVE('E1590',#4384,#909,#4392,.T.);
#4394=ORIENTED_EDGE('',*,*,#4393,.T.);
#4395=ORIENTED_EDGE('',*,*,#910,.T.);
#4396=DIRECTION('',(0.,1.,0.));
#4397=VECTOR('',#4396,1.);
#4398=CARTESIAN_POINT('',(520.7,393.7,-38.1));
#4399=LINE('',#4398,#4397);
#4400=EDGE_CURVE('E1539',#901,#4386,#4399,.F.);
#4401=ORIENTED_EDGE('',*,*,#4400,.T.);
#4402=EDGE_LOOP('',(#4388,#4394,#4395,#4401));
#4403=FACE_BOUND('',#4402,.T.);
#4404=ADVANCED_FACE('F1589',(#4403),#4378,.F.);
#4405=CARTESIAN_POINT('',(25.4,393.7,-38.1));
#4406=DIRECTION('',(0.,1.,0.));
#4407=DIRECTION('',(0.,0.,1.));
#4408=AXIS2_PLACEMENT_3D('',#4405,#4406,#4407);
#4409=PLANE('',#4408);
#4410=ORIENTED_EDGE('',*,*,#4332,.T.);
#4411=CARTESIAN_POINT('',(38.1,393.7,-88.9));
#4412=DIRECTION('',(0.,1.,0.));
#4413=DIRECTION('',(0.,0.,1.));
#4414=AXIS2_PLACEMENT_3D('',#4411,#4412,#4413);
#4415=CIRCLE('',#4414,12.7);
#4416=EDGE_CURVE('E1565',#4323,#4291,#4415,.T.);
#4417=ORIENTED_EDGE('',*,*,#4416,.T.);
#4418=ORIENTED_EDGE('',*,*,#4294,.T.);
#4419=CARTESIAN_POINT('',(38.1,393.7,-50.8));
#4420=DIRECTION('',(0.,1.,0.));
#4421=DIRECTION('',(0.,0.,1.));
#4422=AXIS2_PLACEMENT_3D('',#4419,#4420,#4421);
#4423=CIRCLE('',#4422,12.7);
#4424=EDGE_CURVE('E1553',#4293,#4384,#4423,.T.);
#4425=ORIENTED_EDGE('',*,*,#4424,.T.);
#4426=ORIENTED_EDGE('',*,*,#4387,.T.);
#4427=CARTESIAN_POINT('',(520.7,393.7,-50.8));
#4428=DIRECTION('',(0.,1.,0.));
#4429=DIRECTION('',(0.,0.,1.));
#4430=AXIS2_PLACEMENT_3D('',#4427,#4428,#4429);
#4431=CIRCLE('',#4430,12.7);
#4432=EDGE_CURVE('E1543',#4386,#4353,#4431,.T.);
#4433=ORIENTED_EDGE('',*,*,#4432,.T.);
#4434=ORIENTED_EDGE('',*,*,#4356,.T.);
#4435=CARTESIAN_POINT('',(520.7,393.7,-88.9));
#4436=DIRECTION('',(0.,1.,0.));
#4437=DIRECTION('',(0.,0.,1.));
#4438=AXIS2_PLACEMENT_3D('',#4435,#4436,#4437);
#4439=CIRCLE('',#4438,12.7);
#4440=EDGE_CURVE('E1609',#4355,#4331,#4439,.T.);
#4441=ORIENTED_EDGE('',*,*,#4440,.T.);
#4442=EDGE_LOOP('',(#4410,#4417,#4418,#4425,#4426,#4433,#4434,#4441));
#4443=FACE_BOUND('',#4442,.T.);
#4444=ADVANCED_FACE('F1583',(#4443),#4409,.T.);
#4445=CARTESIAN_POINT('',(95.25,298.45,-12.7));
#4446=DIRECTION('',(0.,0.,-1.));
#4447=DIRECTION('',(-1.,0.,0.));
#4448=AXIS2_PLACEMENT_3D('',#4445,#4446,#4447);
#4449=CYLINDRICAL_SURFACE('',#4448,6.35);
#4450=ORIENTED_EDGE('',*,*,#2229,.F.);
#4451=ORIENTED_EDGE('',*,*,#2125,.F.);
#4452=ORIENTED_EDGE('',*,*,#1476,.F.);
#4453=ORIENTED_EDGE('',*,*,#2094,.F.);
#4454=EDGE_LOOP('',(#4450,#4451,#4452,#4453));
#4455=FACE_BOUND('',#4454,.T.);
#4456=ADVANCED_FACE('F1657',(#4455),#4449,.F.);
#4457=CARTESIAN_POINT('',(95.25,107.95,-12.7));
#4458=DIRECTION('',(0.,0.,-1.));
#4459=DIRECTION('',(-1.,0.,0.));
#4460=AXIS2_PLACEMENT_3D('',#4457,#4458,#4459);
#4461=CYLINDRICAL_SURFACE('',#4460,6.35);
#4462=ORIENTED_EDGE('',*,*,#2221,.F.);
#4463=ORIENTED_EDGE('',*,*,#2156,.F.);
#4464=ORIENTED_EDGE('',*,*,#1491,.F.);
#4465=ORIENTED_EDGE('',*,*,#2118,.F.);
#4466=EDGE_LOOP('',(#4462,#4463,#4464,#4465));
#4467=FACE_BOUND('',#4466,.T.);
#4468=ADVANCED_FACE('F1653',(#4467),#4461,.F.);
#4469=CARTESIAN_POINT('',(57.15,107.95,-12.7));
#4470=DIRECTION('',(0.,0.,-1.));
#4471=DIRECTION('',(-1.,0.,0.));
#4472=AXIS2_PLACEMENT_3D('',#4469,#4470,#4471);
#4473=CYLINDRICAL_SURFACE('',#4472,6.35);
#4474=ORIENTED_EDGE('',*,*,#2213,.F.);
#4475=ORIENTED_EDGE('',*,*,#2063,.F.);
#4476=ORIENTED_EDGE('',*,*,#1442,.F.);
#4477=ORIENTED_EDGE('',*,*,#2149,.F.);
#4478=EDGE_LOOP('',(#4474,#4475,#4476,#4477));
#4479=FACE_BOUND('',#4478,.T.);
#4480=ADVANCED_FACE('F1649',(#4479),#4473,.F.);
#4481=CARTESIAN_POINT('',(57.15,298.45,-12.7));
#4482=DIRECTION('',(0.,0.,-1.));
#4483=DIRECTION('',(-1.,0.,0.));
#4484=AXIS2_PLACEMENT_3D('',#4481,#4482,#4483);
#4485=CYLINDRICAL_SURFACE('',#4484,6.35);
#4486=ORIENTED_EDGE('',*,*,#2205,.F.);
#4487=ORIENTED_EDGE('',*,*,#2080,.F.);
#4488=ORIENTED_EDGE('',*,*,#1459,.F.);
#4489=ORIENTED_EDGE('',*,*,#2056,.F.);
#4490=EDGE_LOOP('',(#4486,#4487,#4488,#4489));
#4491=FACE_BOUND('',#4490,.T.);
#4492=ADVANCED_FACE('F1645',(#4491),#4485,.F.);
#4493=CARTESIAN_POINT('',(552.45,298.45,-12.7));
#4494=DIRECTION('',(0.,0.,-1.));
#4495=DIRECTION('',(-1.,0.,0.));
#4496=AXIS2_PLACEMENT_3D('',#4493,#4494,#4495);
#4497=CYLINDRICAL_SURFACE('',#4496,6.35);
#4498=ORIENTED_EDGE('',*,*,#2542,.F.);
#4499=ORIENTED_EDGE('',*,*,#2438,.F.);
#4500=ORIENTED_EDGE('',*,*,#1406,.F.);
#4501=ORIENTED_EDGE('',*,*,#2407,.F.);
#4502=EDGE_LOOP('',(#4498,#4499,#4500,#4501));
#4503=FACE_BOUND('',#4502,.T.);
#4504=ADVANCED_FACE('F1641',(#4503),#4497,.F.);
#4505=CARTESIAN_POINT('',(552.45,107.95,-12.7));
#4506=DIRECTION('',(0.,0.,-1.));
#4507=DIRECTION('',(-1.,0.,0.));
#4508=AXIS2_PLACEMENT_3D('',#4505,#4506,#4507);
#4509=CYLINDRICAL_SURFACE('',#4508,6.35);
#4510=ORIENTED_EDGE('',*,*,#2534,.F.);
#4511=ORIENTED_EDGE('',*,*,#2469,.F.);
#4512=ORIENTED_EDGE('',*,*,#1421,.F.);
#4513=ORIENTED_EDGE('',*,*,#2431,.F.);
#4514=EDGE_LOOP('',(#4510,#4511,#4512,#4513));
#4515=FACE_BOUND('',#4514,.T.);
#4516=ADVANCED_FACE('F1637',(#4515),#4509,.F.);
#4517=CARTESIAN_POINT('',(514.35,107.95,-12.7));
#4518=DIRECTION('',(0.,0.,-1.));
#4519=DIRECTION('',(-1.,0.,0.));
#4520=AXIS2_PLACEMENT_3D('',#4517,#4518,#4519);
#4521=CYLINDRICAL_SURFACE('',#4520,6.35);
#4522=ORIENTED_EDGE('',*,*,#2526,.F.);
#4523=ORIENTED_EDGE('',*,*,#2376,.F.);
#4524=ORIENTED_EDGE('',*,*,#1372,.F.);
#4525=ORIENTED_EDGE('',*,*,#2462,.F.);
#4526=EDGE_LOOP('',(#4522,#4523,#4524,#4525));
#4527=FACE_BOUND('',#4526,.T.);
#4528=ADVANCED_FACE('F1633',(#4527),#4521,.F.);
#4529=CARTESIAN_POINT('',(514.35,298.45,-12.7));
#4530=DIRECTION('',(0.,0.,-1.));
#4531=DIRECTION('',(-1.,0.,0.));
#4532=AXIS2_PLACEMENT_3D('',#4529,#4530,#4531);
#4533=CYLINDRICAL_SURFACE('',#4532,6.35);
#4534=ORIENTED_EDGE('',*,*,#2518,.F.);
#4535=ORIENTED_EDGE('',*,*,#2393,.F.);
#4536=ORIENTED_EDGE('',*,*,#1389,.F.);
#4537=ORIENTED_EDGE('',*,*,#2369,.F.);
#4538=EDGE_LOOP('',(#4534,#4535,#4536,#4537));
#4539=FACE_BOUND('',#4538,.T.);
#4540=ADVANCED_FACE('F1630',(#4539),#4533,.F.);
#4541=CARTESIAN_POINT('',(38.1,12.7,-50.8));
#4542=DIRECTION('',(0.,1.,0.));
#4543=DIRECTION('',(0.,0.,1.));
#4544=AXIS2_PLACEMENT_3D('',#4541,#4542,#4543);
#4545=CYLINDRICAL_SURFACE('',#4544,12.7);
#4546=ORIENTED_EDGE('',*,*,#4276,.F.);
#4547=ORIENTED_EDGE('',*,*,#4143,.F.);
#4548=ORIENTED_EDGE('',*,*,#1275,.F.);
#4549=ORIENTED_EDGE('',*,*,#4236,.F.);
#4550=EDGE_LOOP('',(#4546,#4547,#4548,#4549));
#4551=FACE_BOUND('',#4550,.T.);
#4552=ADVANCED_FACE('F1011',(#4551),#4545,.F.);
#4553=CARTESIAN_POINT('',(520.7,12.7,-50.7999999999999));
#4554=DIRECTION('',(0.,1.,0.));
#4555=DIRECTION('',(0.,0.,1.));
#4556=AXIS2_PLACEMENT_3D('',#4553,#4554,#4555);
#4557=CYLINDRICAL_SURFACE('',#4556,12.7);
#4558=ORIENTED_EDGE('',*,*,#4268,.F.);
#4559=ORIENTED_EDGE('',*,*,#4174,.F.);
#4560=ORIENTED_EDGE('',*,*,#1226,.F.);
#4561=ORIENTED_EDGE('',*,*,#4136,.F.);
#4562=EDGE_LOOP('',(#4558,#4559,#4560,#4561));
#4563=FACE_BOUND('',#4562,.T.);
#4564=ADVANCED_FACE('F1083',(#4563),#4557,.F.);
#4565=CARTESIAN_POINT('',(114.3,381.,-5.6843418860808E-11));
#4566=DIRECTION('',(0.,0.,1.));
#4567=DIRECTION('',(1.,0.,0.));
#4568=AXIS2_PLACEMENT_3D('',#4565,#4566,#4567);
#4569=CYLINDRICAL_SURFACE('',#4568,12.7);
#4570=ORIENTED_EDGE('',*,*,#3657,.F.);
#4571=ORIENTED_EDGE('',*,*,#3608,.F.);
#4572=ORIENTED_EDGE('',*,*,#1556,.F.);
#4573=ORIENTED_EDGE('',*,*,#3696,.F.);
#4574=EDGE_LOOP('',(#4570,#4571,#4572,#4573));
#4575=FACE_BOUND('',#4574,.T.);
#4576=ADVANCED_FACE('F1172',(#4575),#4569,.F.);
#4577=CARTESIAN_POINT('',(168.9,381.,-5.6843418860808E-11));
#4578=DIRECTION('',(0.,0.,-1.));
#4579=DIRECTION('',(-1.,0.,0.));
#4580=AXIS2_PLACEMENT_3D('',#4577,#4578,#4579);
#4581=CYLINDRICAL_SURFACE('',#4580,12.7);
#4582=ORIENTED_EDGE('',*,*,#1623,.F.);
#4583=ORIENTED_EDGE('',*,*,#3672,.F.);
#4584=ORIENTED_EDGE('',*,*,#3642,.F.);
#4585=ORIENTED_EDGE('',*,*,#3689,.F.);
#4586=EDGE_LOOP('',(#4582,#4583,#4584,#4585));
#4587=FACE_BOUND('',#4586,.T.);
#4588=ADVANCED_FACE('F1613',(#4587),#4581,.F.);
#4589=CARTESIAN_POINT('',(520.7,393.7,-88.9));
#4590=DIRECTION('',(0.,-1.,0.));
#4591=DIRECTION('',(0.,0.,-1.));
#4592=AXIS2_PLACEMENT_3D('',#4589,#4590,#4591);
#4593=CYLINDRICAL_SURFACE('',#4592,12.7);
#4594=ORIENTED_EDGE('',*,*,#4440,.F.);
#4595=ORIENTED_EDGE('',*,*,#4369,.F.);
#4596=ORIENTED_EDGE('',*,*,#885,.F.);
#4597=ORIENTED_EDGE('',*,*,#4338,.F.);
#4598=EDGE_LOOP('',(#4594,#4595,#4596,#4597));
#4599=FACE_BOUND('',#4598,.T.);
#4600=ADVANCED_FACE('F1610',(#4599),#4593,.F.);
#4601=CARTESIAN_POINT('',(520.7,393.7,-50.8));
#4602=DIRECTION('',(0.,-1.,0.));
#4603=DIRECTION('',(0.,0.,-1.));
#4604=AXIS2_PLACEMENT_3D('',#4601,#4602,#4603);
#4605=CYLINDRICAL_SURFACE('',#4604,12.7);
#4606=ORIENTED_EDGE('',*,*,#4432,.F.);
#4607=ORIENTED_EDGE('',*,*,#4400,.F.);
#4608=ORIENTED_EDGE('',*,*,#902,.F.);
#4609=ORIENTED_EDGE('',*,*,#4362,.F.);
#4610=EDGE_LOOP('',(#4606,#4607,#4608,#4609));
#4611=FACE_BOUND('',#4610,.T.);
#4612=ADVANCED_FACE('F1601',(#4611),#4605,.F.);
#4613=CARTESIAN_POINT('',(38.1,393.7,-50.8));
#4614=DIRECTION('',(0.,-1.,0.));
#4615=DIRECTION('',(0.,0.,-1.));
#4616=AXIS2_PLACEMENT_3D('',#4613,#4614,#4615);
#4617=CYLINDRICAL_SURFACE('',#4616,12.7);
#4618=ORIENTED_EDGE('',*,*,#4424,.F.);
#4619=ORIENTED_EDGE('',*,*,#4307,.F.);
#4620=ORIENTED_EDGE('',*,*,#917,.F.);
#4621=ORIENTED_EDGE('',*,*,#4393,.F.);
#4622=EDGE_LOOP('',(#4618,#4619,#4620,#4621));
#4623=FACE_BOUND('',#4622,.T.);
#4624=ADVANCED_FACE('F1594',(#4623),#4617,.F.);
#4625=CARTESIAN_POINT('',(38.1,393.7,-88.9));
#4626=DIRECTION('',(0.,-1.,0.));
#4627=DIRECTION('',(0.,0.,-1.));
#4628=AXIS2_PLACEMENT_3D('',#4625,#4626,#4627);
#4629=CYLINDRICAL_SURFACE('',#4628,12.7);
#4630=ORIENTED_EDGE('',*,*,#4416,.F.);
#4631=ORIENTED_EDGE('',*,*,#4324,.F.);
#4632=ORIENTED_EDGE('',*,*,#868,.F.);
#4633=ORIENTED_EDGE('',*,*,#4300,.F.);
#4634=EDGE_LOOP('',(#4630,#4631,#4632,#4633));
#4635=FACE_BOUND('',#4634,.T.);
#4636=ADVANCED_FACE('F1577',(#4635),#4629,.F.);
#4637=CARTESIAN_POINT('',(520.7,12.7,-88.9));
#4638=DIRECTION('',(0.,1.,0.));
#4639=DIRECTION('',(0.,0.,1.));
#4640=AXIS2_PLACEMENT_3D('',#4637,#4638,#4639);
#4641=CYLINDRICAL_SURFACE('',#4640,12.7);
#4642=ORIENTED_EDGE('',*,*,#4260,.F.);
#4643=ORIENTED_EDGE('',*,*,#4205,.F.);
#4644=ORIENTED_EDGE('',*,*,#1243,.F.);
#4645=ORIENTED_EDGE('',*,*,#4167,.F.);
#4646=EDGE_LOOP('',(#4642,#4643,#4644,#4645));
#4647=FACE_BOUND('',#4646,.T.);
#4648=ADVANCED_FACE('F2729',(#4647),#4641,.F.);
#4649=CARTESIAN_POINT('',(38.1,12.7,-88.9));
#4650=DIRECTION('',(0.,1.,0.));
#4651=DIRECTION('',(0.,0.,1.));
#4652=AXIS2_PLACEMENT_3D('',#4649,#4650,#4651);
#4653=CYLINDRICAL_SURFACE('',#4652,12.7);
#4654=ORIENTED_EDGE('',*,*,#4252,.F.);
#4655=ORIENTED_EDGE('',*,*,#4222,.F.);
#4656=ORIENTED_EDGE('',*,*,#1260,.F.);
#4657=ORIENTED_EDGE('',*,*,#4198,.F.);
#4658=EDGE_LOOP('',(#4654,#4655,#4656,#4657));
#4659=FACE_BOUND('',#4658,.T.);
#4660=ADVANCED_FACE('F1065',(#4659),#4653,.F.);
#4661=CARTESIAN_POINT('',(670.956146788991,406.4,-48.7717322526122));
#4662=DIRECTION('',(0.,0.,-1.));
#4663=DIRECTION('',(-1.,0.,0.));
#4664=AXIS2_PLACEMENT_3D('',#4661,#4662,#4663);
#4665=PLANE('',#4664);
#4666=ORIENTED_EDGE('',*,*,#54,.T.);
#4667=ORIENTED_EDGE('',*,*,#749,.F.);
#4668=DIRECTION('',(0.,-1.,0.));
#4669=VECTOR('',#4668,1.);
#4670=CARTESIAN_POINT('',(632.856146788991,406.4,-48.7717322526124));
#4671=LINE('',#4670,#4669);
#4672=EDGE_CURVE('E3131',#748,#1120,#4671,.T.);
#4673=ORIENTED_EDGE('',*,*,#4672,.T.);
#4674=ORIENTED_EDGE('',*,*,#1121,.T.);
#4675=EDGE_LOOP('',(#4666,#4667,#4673,#4674));
#4676=FACE_BOUND('',#4675,.T.);
#4677=ADVANCED_FACE('F2747',(#4676),#4665,.F.);
#4678=CARTESIAN_POINT('',(632.856146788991,406.4,-48.7717322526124));
#4679=DIRECTION('',(1.,0.,0.));
#4680=DIRECTION('',(0.,0.,-1.));
#4681=AXIS2_PLACEMENT_3D('',#4678,#4679,#4680);
#4682=PLANE('',#4681);
#4683=ORIENTED_EDGE('',*,*,#1129,.T.);
#4684=ORIENTED_EDGE('',*,*,#4672,.F.);
#4685=ORIENTED_EDGE('',*,*,#847,.F.);
#4686=DIRECTION('',(0.,-1.,0.));
#4687=VECTOR('',#4686,1.);
#4688=CARTESIAN_POINT('',(632.856146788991,406.4,-58.2967322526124));
#4689=LINE('',#4688,#4687);
#4690=EDGE_CURVE('E4216',#840,#1128,#4689,.T.);
#4691=ORIENTED_EDGE('',*,*,#4690,.T.);
#4692=EDGE_LOOP('',(#4683,#4684,#4685,#4691));
#4693=FACE_BOUND('',#4692,.T.);
#4694=ADVANCED_FACE('F2757',(#4693),#4682,.F.);
#4695=CARTESIAN_POINT('',(632.856146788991,406.4,-58.2967322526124));
#4696=DIRECTION('',(0.,0.,-1.));
#4697=DIRECTION('',(-1.,0.,0.));
#4698=AXIS2_PLACEMENT_3D('',#4695,#4696,#4697);
#4699=PLANE('',#4698);
#4700=ORIENTED_EDGE('',*,*,#1137,.T.);
#4701=ORIENTED_EDGE('',*,*,#4690,.F.);
#4702=ORIENTED_EDGE('',*,*,#841,.F.);
#4703=DIRECTION('',(0.,-1.,0.));
#4704=VECTOR('',#4703,1.);
#4705=CARTESIAN_POINT('',(611.821771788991,406.4,-58.2967322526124));
#4706=LINE('',#4705,#4704);
#4707=EDGE_CURVE('E4211',#832,#1136,#4706,.T.);
#4708=ORIENTED_EDGE('',*,*,#4707,.T.);
#4709=EDGE_LOOP('',(#4700,#4701,#4702,#4708));
#4710=FACE_BOUND('',#4709,.T.);
#4711=ADVANCED_FACE('F2768',(#4710),#4699,.F.);
#4712=CARTESIAN_POINT('',(611.821771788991,406.4,-13.8467322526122));
#4713=DIRECTION('',(-1.,0.,0.));
#4714=DIRECTION('',(0.,0.,1.));
#4715=AXIS2_PLACEMENT_3D('',#4712,#4713,#4714);
#4716=PLANE('',#4715);
#4717=ORIENTED_EDGE('',*,*,#1145,.T.);
#4718=ORIENTED_EDGE('',*,*,#4707,.F.);
#4719=ORIENTED_EDGE('',*,*,#833,.F.);
#4720=DIRECTION('',(0.,-1.,0.));
#4721=VECTOR('',#4720,1.);
#4722=CARTESIAN_POINT('',(611.821771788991,406.4,-13.8467322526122));
#4723=LINE('',#4722,#4721);
#4724=EDGE_CURVE('E4209',#824,#1144,#4723,.T.);
#4725=ORIENTED_EDGE('',*,*,#4724,.T.);
#4726=EDGE_LOOP('',(#4717,#4718,#4719,#4725));
#4727=FACE_BOUND('',#4726,.T.);
#4728=ADVANCED_FACE('F2779',(#4727),#4716,.F.);
#4729=CARTESIAN_POINT('',(632.856146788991,406.4,-13.8467322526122));
#4730=DIRECTION('',(0.,0.,1.));
#4731=DIRECTION('',(1.,0.,0.));
#4732=AXIS2_PLACEMENT_3D('',#4729,#4730,#4731);
#4733=PLANE('',#4732);
#4734=ORIENTED_EDGE('',*,*,#1153,.T.);
#4735=ORIENTED_EDGE('',*,*,#4724,.F.);
#4736=ORIENTED_EDGE('',*,*,#825,.F.);
#4737=DIRECTION('',(0.,-1.,0.));
#4738=VECTOR('',#4737,1.);
#4739=CARTESIAN_POINT('',(632.856146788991,406.4,-13.8467322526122));
#4740=LINE('',#4739,#4738);
#4741=EDGE_CURVE('E718',#816,#1152,#4740,.T.);
#4742=ORIENTED_EDGE('',*,*,#4741,.T.);
#4743=EDGE_LOOP('',(#4734,#4735,#4736,#4742));
#4744=FACE_BOUND('',#4743,.T.);
#4745=ADVANCED_FACE('F2789',(#4744),#4733,.F.);
#4746=CARTESIAN_POINT('',(632.856146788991,406.4,-13.8467322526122));
#4747=DIRECTION('',(1.,0.,0.));
#4748=DIRECTION('',(0.,0.,-1.));
#4749=AXIS2_PLACEMENT_3D('',#4746,#4747,#4748);
#4750=PLANE('',#4749);
#4751=ORIENTED_EDGE('',*,*,#1161,.T.);
#4752=ORIENTED_EDGE('',*,*,#4741,.F.);
#4753=ORIENTED_EDGE('',*,*,#817,.F.);
#4754=DIRECTION('',(0.,-1.,0.));
#4755=VECTOR('',#4754,1.);
#4756=CARTESIAN_POINT('',(632.856146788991,406.4,-23.3717322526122));
#4757=LINE('',#4756,#4755);
#4758=EDGE_CURVE('E703',#808,#1160,#4757,.T.);
#4759=ORIENTED_EDGE('',*,*,#4758,.T.);
#4760=EDGE_LOOP('',(#4751,#4752,#4753,#4759));
#4761=FACE_BOUND('',#4760,.T.);
#4762=ADVANCED_FACE('F713',(#4761),#4750,.F.);
#4763=CARTESIAN_POINT('',(670.956146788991,406.4,-23.3717322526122));
#4764=DIRECTION('',(0.,0.,1.));
#4765=DIRECTION('',(1.,0.,0.));
#4766=AXIS2_PLACEMENT_3D('',#4763,#4764,#4765);
#4767=PLANE('',#4766);
#4768=ORIENTED_EDGE('',*,*,#719,.T.);
#4769=ORIENTED_EDGE('',*,*,#1167,.T.);
#4770=ORIENTED_EDGE('',*,*,#4758,.F.);
#4771=ORIENTED_EDGE('',*,*,#809,.F.);
#4772=EDGE_LOOP('',(#4768,#4769,#4770,#4771));
#4773=FACE_BOUND('',#4772,.T.);
#4774=ADVANCED_FACE('F702',(#4773),#4767,.F.);
#4775=CARTESIAN_POINT('',(658.256146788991,44.45,-88.9));
#4776=DIRECTION('',(1.,0.,0.));
#4777=DIRECTION('',(0.,0.,-1.));
#4778=AXIS2_PLACEMENT_3D('',#4775,#4776,#4777);
#4779=CYLINDRICAL_SURFACE('',#4778,3.17500000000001);
#4780=CARTESIAN_POINT('',(653.176146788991,44.45,-88.9));
#4781=DIRECTION('',(1.,0.,0.));
#4782=DIRECTION('',(0.,0.,-1.));
#4783=AXIS2_PLACEMENT_3D('',#4780,#4781,#4782);
#4784=CIRCLE('',#4783,3.17500000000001);
#4785=CARTESIAN_POINT('',(653.176146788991,44.45,-92.075));
#4786=VERTEX_POINT('',#4785);
#4787=EDGE_CURVE('E741',#4786,#4786,#4784,.T.);
#4788=ORIENTED_EDGE('',*,*,#4787,.F.);
#4789=EDGE_LOOP('',(#4788));
#4790=FACE_BOUND('',#4789,.T.);
#4791=ORIENTED_EDGE('',*,*,#42,.T.);
#4792=EDGE_LOOP('',(#4791));
#4793=FACE_BOUND('',#4792,.T.);
#4794=ADVANCED_FACE('F752',(#4790,#4793),#4779,.F.);
#4795=CARTESIAN_POINT('',(653.176146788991,44.45,-88.9));
#4796=DIRECTION('',(-1.,0.,0.));
#4797=DIRECTION('',(0.,0.,1.));
#4798=AXIS2_PLACEMENT_3D('',#4795,#4796,#4797);
#4799=PLANE('',#4798);
#4800=ORIENTED_EDGE('',*,*,#4787,.T.);
#4801=EDGE_LOOP('',(#4800));
#4802=FACE_BOUND('',#4801,.T.);
#4803=ADVANCED_FACE('F2824',(#4802),#4799,.F.);
#4804=CARTESIAN_POINT('',(658.256146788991,361.95,-88.9));
#4805=DIRECTION('',(1.,0.,0.));
#4806=DIRECTION('',(0.,0.,-1.));
#4807=AXIS2_PLACEMENT_3D('',#4804,#4805,#4806);
#4808=CYLINDRICAL_SURFACE('',#4807,3.17500000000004);
#4809=CARTESIAN_POINT('',(653.176146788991,361.95,-88.9));
#4810=DIRECTION('',(1.,0.,0.));
#4811=DIRECTION('',(0.,0.,-1.));
#4812=AXIS2_PLACEMENT_3D('',#4809,#4810,#4811);
#4813=CIRCLE('',#4812,3.17500000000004);
#4814=CARTESIAN_POINT('',(653.176146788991,361.95,-92.075));
#4815=VERTEX_POINT('',#4814);
#4816=EDGE_CURVE('E2861',#4815,#4815,#4813,.T.);
#4817=ORIENTED_EDGE('',*,*,#4816,.F.);
#4818=EDGE_LOOP('',(#4817));
#4819=FACE_BOUND('',#4818,.T.);
#4820=ORIENTED_EDGE('',*,*,#31,.T.);
#4821=EDGE_LOOP('',(#4820));
#4822=FACE_BOUND('',#4821,.T.);
#4823=ADVANCED_FACE('F2834',(#4819,#4822),#4808,.F.);
#4824=CARTESIAN_POINT('',(653.176146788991,361.95,-88.9));
#4825=DIRECTION('',(-1.,0.,0.));
#4826=DIRECTION('',(0.,0.,1.));
#4827=AXIS2_PLACEMENT_3D('',#4824,#4825,#4826);
#4828=PLANE('',#4827);
#4829=ORIENTED_EDGE('',*,*,#4816,.T.);
#4830=EDGE_LOOP('',(#4829));
#4831=FACE_BOUND('',#4830,.T.);
#4832=ADVANCED_FACE('F2844',(#4831),#4828,.F.);
#4833=CLOSED_SHELL('',(#108,#331,#657,#710,#737,#921,#1109,#1279,#1627,#1661,#1678,#1816,#1828,
#1848,#1868,#1880,#1900,#1920,#1932,#1952,#1972,#1984,#2004,#2024,#2036,#2067,#2098,#2129,#2160,
#2233,#2253,#2273,#2285,#2305,#2325,#2337,#2349,#2380,#2411,#2442,#2473,#2546,#2566,#2586,#2598,
#2618,#2638,#2650,#2662,#2684,#2701,#2718,#2735,#2752,#2769,#2786,#2798,#2818,#2838,#2850,#2870,
#2890,#2902,#2922,#2942,#2954,#2974,#2994,#3006,#3028,#3045,#3062,#3079,#3096,#3113,#3130,#3147,
#3164,#3181,#3198,#3215,#3232,#3249,#3266,#3283,#3300,#3317,#3334,#3351,#3368,#3385,#3402,#3414,
#3434,#3454,#3466,#3498,#3522,#3547,#3564,#3581,#3595,#3619,#3661,#3678,#3700,#3732,#3756,#3781,
#3805,#3830,#3854,#3879,#3903,#3928,#3952,#3977,#4001,#4026,#4050,#4075,#4092,#4116,#4147,#4178,
#4209,#4240,#4280,#4311,#4342,#4373,#4404,#4444,#4456,#4468,#4480,#4492,#4504,#4516,#4528,#4540,
#4552,#4564,#4576,#4588,#4600,#4612,#4624,#4636,#4648,#4660,#4677,#4694,#4711,#4728,#4745,#4762,
#4774,#4794,#4803,#4823,#4832));
#4834=MANIFOLD_SOLID_BREP('B2',#4833);
#4835=ADVANCED_BREP_SHAPE_REPRESENTATION('',(#18,#4834),#14);
#4836=SHAPE_DEFINITION_REPRESENTATION(#9,#4835);
ENDSEC;
END-ISO-10303-21;
